VERSION 5.8 ;
BUSBITCHARS "[]" ;
DIVIDERCHAR "/" ;
UNITS
    DATABASE MICRONS 1000 ;
END UNITS

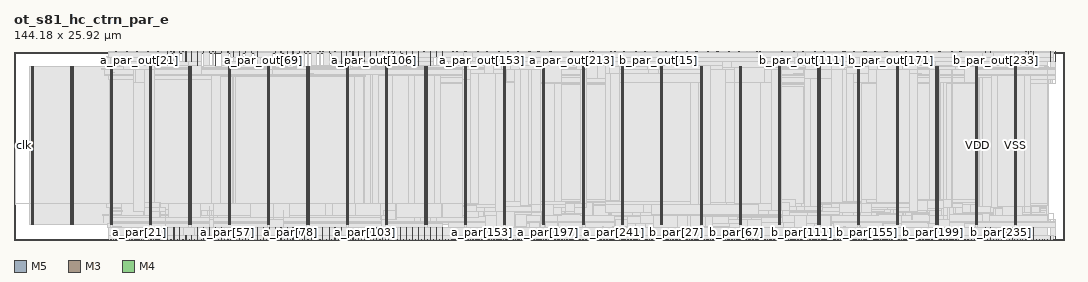
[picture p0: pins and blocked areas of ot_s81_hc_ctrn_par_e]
MACRO ot_s81_hc_ctrn_par_e
  FOREIGN ot_s81_hc_ctrn_par_e 0 0 ;
  CLASS BLOCK ;
  SIZE 144.18 BY 25.92 ;
  PIN a_par[0]
    DIRECTION INPUT ;
    USE SIGNAL ;
    PORT
      LAYER M5 ;
        RECT  13.008 0 13.032 0.084 ;
    END
  END a_par[0]
  PIN a_par[100]
    DIRECTION INPUT ;
    USE SIGNAL ;
    PORT
      LAYER M5 ;
        RECT  46.896 0 46.92 0.084 ;
    END
  END a_par[100]
  PIN a_par[101]
    DIRECTION INPUT ;
    USE SIGNAL ;
    PORT
      LAYER M3 ;
        RECT  47.304 0 47.322 0.038 ;
    END
    PORT
      LAYER M3 ;
        RECT  47.304 0.012 47.322 0.571 ;
    END
  END a_par[101]
  PIN a_par[102]
    DIRECTION INPUT ;
    USE SIGNAL ;
    PORT
      LAYER M5 ;
        RECT  47.76 0 47.784 0.084 ;
    END
  END a_par[102]
  PIN a_par[103]
    DIRECTION INPUT ;
    USE SIGNAL ;
    PORT
      LAYER M3 ;
        RECT  48.168 0 48.186 0.038 ;
    END
    PORT
      LAYER M3 ;
        RECT  48.168 0.012 48.186 0.091 ;
    END
  END a_par[103]
  PIN a_par[104]
    DIRECTION INPUT ;
    USE SIGNAL ;
    PORT
      LAYER M5 ;
        RECT  48.528 0 48.552 0.084 ;
    END
  END a_par[104]
  PIN a_par[105]
    DIRECTION INPUT ;
    USE SIGNAL ;
    PORT
      LAYER M3 ;
        RECT  48.96 0 48.978 0.038 ;
    END
    PORT
      LAYER M3 ;
        RECT  48.96 0.012 48.978 0.091 ;
    END
  END a_par[105]
  PIN a_par[106]
    DIRECTION INPUT ;
    USE SIGNAL ;
    PORT
      LAYER M5 ;
        RECT  49.392 0 49.416 0.084 ;
    END
  END a_par[106]
  PIN a_par[107]
    DIRECTION INPUT ;
    USE SIGNAL ;
    PORT
      LAYER M3 ;
        RECT  49.824 0 49.842 0.038 ;
    END
    PORT
      LAYER M3 ;
        RECT  49.824 0.012 49.842 1.723 ;
    END
  END a_par[107]
  PIN a_par[108]
    DIRECTION INPUT ;
    USE SIGNAL ;
    PORT
      LAYER M5 ;
        RECT  50.256 0 50.28 0.084 ;
    END
  END a_par[108]
  PIN a_par[109]
    DIRECTION INPUT ;
    USE SIGNAL ;
    PORT
      LAYER M3 ;
        RECT  50.58 0 50.598 0.038 ;
    END
    PORT
      LAYER M3 ;
        RECT  50.58 0.012 50.598 1.723 ;
    END
  END a_par[109]
  PIN a_par[10]
    DIRECTION INPUT ;
    USE SIGNAL ;
    PORT
      LAYER M5 ;
        RECT  15.024 0 15.048 0.084 ;
    END
  END a_par[10]
  PIN a_par[110]
    DIRECTION INPUT ;
    USE SIGNAL ;
    PORT
      LAYER M5 ;
        RECT  51.024 0 51.048 0.084 ;
    END
  END a_par[110]
  PIN a_par[111]
    DIRECTION INPUT ;
    USE SIGNAL ;
    PORT
      LAYER M3 ;
        RECT  51.444 0 51.462 0.038 ;
    END
    PORT
      LAYER M3 ;
        RECT  51.444 0.012 51.462 0.091 ;
    END
  END a_par[111]
  PIN a_par[112]
    DIRECTION INPUT ;
    USE SIGNAL ;
    PORT
      LAYER M5 ;
        RECT  51.888 0 51.912 0.084 ;
    END
  END a_par[112]
  PIN a_par[113]
    DIRECTION INPUT ;
    USE SIGNAL ;
    PORT
      LAYER M3 ;
        RECT  52.2 0 52.218 0.038 ;
    END
    PORT
      LAYER M3 ;
        RECT  52.2 0.012 52.218 0.091 ;
    END
  END a_par[113]
  PIN a_par[114]
    DIRECTION INPUT ;
    USE SIGNAL ;
    PORT
      LAYER M5 ;
        RECT  52.656 0 52.68 0.084 ;
    END
  END a_par[114]
  PIN a_par[115]
    DIRECTION INPUT ;
    USE SIGNAL ;
    PORT
      LAYER M3 ;
        RECT  53.064 0 53.082 0.038 ;
    END
    PORT
      LAYER M3 ;
        RECT  53.064 0.012 53.082 1.723 ;
    END
  END a_par[115]
  PIN a_par[116]
    DIRECTION INPUT ;
    USE SIGNAL ;
    PORT
      LAYER M5 ;
        RECT  53.52 0 53.544 0.084 ;
    END
  END a_par[116]
  PIN a_par[117]
    DIRECTION INPUT ;
    USE SIGNAL ;
    PORT
      LAYER M3 ;
        RECT  53.856 0 53.874 0.038 ;
    END
    PORT
      LAYER M3 ;
        RECT  53.856 0.012 53.874 1.723 ;
    END
  END a_par[117]
  PIN a_par[118]
    DIRECTION INPUT ;
    USE SIGNAL ;
    PORT
      LAYER M5 ;
        RECT  54.288 0 54.312 0.084 ;
    END
  END a_par[118]
  PIN a_par[119]
    DIRECTION INPUT ;
    USE SIGNAL ;
    PORT
      LAYER M3 ;
        RECT  54.72 0 54.738 0.038 ;
    END
    PORT
      LAYER M3 ;
        RECT  54.72 0.012 54.738 1.723 ;
    END
  END a_par[119]
  PIN a_par[11]
    DIRECTION INPUT ;
    USE SIGNAL ;
    PORT
      LAYER M3 ;
        RECT  15.264 0 15.282 0.038 ;
    END
  END a_par[11]
  PIN a_par[120]
    DIRECTION INPUT ;
    USE SIGNAL ;
    PORT
      LAYER M5 ;
        RECT  55.152 0 55.176 0.084 ;
    END
  END a_par[120]
  PIN a_par[121]
    DIRECTION INPUT ;
    USE SIGNAL ;
    PORT
      LAYER M3 ;
        RECT  55.476 0 55.494 0.038 ;
    END
    PORT
      LAYER M3 ;
        RECT  55.476 0.012 55.494 1.723 ;
    END
  END a_par[121]
  PIN a_par[122]
    DIRECTION INPUT ;
    USE SIGNAL ;
    PORT
      LAYER M5 ;
        RECT  55.92 0 55.944 0.084 ;
    END
  END a_par[122]
  PIN a_par[123]
    DIRECTION INPUT ;
    USE SIGNAL ;
    PORT
      LAYER M3 ;
        RECT  56.34 0 56.358 0.038 ;
    END
    PORT
      LAYER M3 ;
        RECT  56.34 0.012 56.358 1.723 ;
    END
  END a_par[123]
  PIN a_par[124]
    DIRECTION INPUT ;
    USE SIGNAL ;
    PORT
      LAYER M5 ;
        RECT  56.784 0 56.808 0.084 ;
    END
  END a_par[124]
  PIN a_par[125]
    DIRECTION INPUT ;
    USE SIGNAL ;
    PORT
      LAYER M3 ;
        RECT  57.204 0 57.222 0.038 ;
    END
    PORT
      LAYER M3 ;
        RECT  57.204 0.012 57.222 1.723 ;
    END
  END a_par[125]
  PIN a_par[126]
    DIRECTION INPUT ;
    USE SIGNAL ;
    PORT
      LAYER M5 ;
        RECT  57.552 0 57.576 0.084 ;
    END
  END a_par[126]
  PIN a_par[127]
    DIRECTION INPUT ;
    USE SIGNAL ;
    PORT
      LAYER M3 ;
        RECT  57.96 0 57.978 0.038 ;
    END
    PORT
      LAYER M3 ;
        RECT  57.96 0.012 57.978 1.723 ;
    END
  END a_par[127]
  PIN a_par[128]
    DIRECTION INPUT ;
    USE SIGNAL ;
    PORT
      LAYER M5 ;
        RECT  58.416 0 58.44 0.084 ;
    END
  END a_par[128]
  PIN a_par[129]
    DIRECTION INPUT ;
    USE SIGNAL ;
    PORT
      LAYER M3 ;
        RECT  58.824 0 58.842 0.038 ;
    END
    PORT
      LAYER M3 ;
        RECT  58.824 0.012 58.842 1.723 ;
    END
  END a_par[129]
  PIN a_par[12]
    DIRECTION INPUT ;
    USE SIGNAL ;
    PORT
      LAYER M5 ;
        RECT  15.504 0 15.528 0.084 ;
    END
  END a_par[12]
  PIN a_par[130]
    DIRECTION INPUT ;
    USE SIGNAL ;
    PORT
      LAYER M5 ;
        RECT  59.184 0 59.208 0.084 ;
    END
  END a_par[130]
  PIN a_par[131]
    DIRECTION INPUT ;
    USE SIGNAL ;
    PORT
      LAYER M3 ;
        RECT  59.616 0 59.634 0.038 ;
    END
  END a_par[131]
  PIN a_par[132]
    DIRECTION INPUT ;
    USE SIGNAL ;
    PORT
      LAYER M5 ;
        RECT  60.048 0 60.072 0.084 ;
    END
  END a_par[132]
  PIN a_par[133]
    DIRECTION INPUT ;
    USE SIGNAL ;
    PORT
      LAYER M3 ;
        RECT  60.264 0 60.282 0.038 ;
    END
  END a_par[133]
  PIN a_par[134]
    DIRECTION INPUT ;
    USE SIGNAL ;
    PORT
      LAYER M5 ;
        RECT  60.432 0 60.456 0.084 ;
    END
  END a_par[134]
  PIN a_par[135]
    DIRECTION INPUT ;
    USE SIGNAL ;
    PORT
      LAYER M3 ;
        RECT  60.66 0 60.678 0.038 ;
    END
  END a_par[135]
  PIN a_par[136]
    DIRECTION INPUT ;
    USE SIGNAL ;
    PORT
      LAYER M5 ;
        RECT  60.816 0 60.84 0.084 ;
    END
  END a_par[136]
  PIN a_par[137]
    DIRECTION INPUT ;
    USE SIGNAL ;
    PORT
      LAYER M3 ;
        RECT  61.056 0 61.074 0.038 ;
    END
  END a_par[137]
  PIN a_par[138]
    DIRECTION INPUT ;
    USE SIGNAL ;
    PORT
      LAYER M5 ;
        RECT  61.296 0 61.32 0.084 ;
    END
  END a_par[138]
  PIN a_par[139]
    DIRECTION INPUT ;
    USE SIGNAL ;
    PORT
      LAYER M3 ;
        RECT  61.416 0 61.434 0.038 ;
    END
  END a_par[139]
  PIN a_par[13]
    DIRECTION INPUT ;
    USE SIGNAL ;
    PORT
      LAYER M3 ;
        RECT  15.624 0 15.642 0.038 ;
    END
  END a_par[13]
  PIN a_par[140]
    DIRECTION INPUT ;
    USE SIGNAL ;
    PORT
      LAYER M5 ;
        RECT  61.68 0 61.704 0.084 ;
    END
  END a_par[140]
  PIN a_par[141]
    DIRECTION INPUT ;
    USE SIGNAL ;
    PORT
      LAYER M3 ;
        RECT  61.92 0 61.938 0.038 ;
    END
  END a_par[141]
  PIN a_par[142]
    DIRECTION INPUT ;
    USE SIGNAL ;
    PORT
      LAYER M5 ;
        RECT  62.064 0 62.088 0.084 ;
    END
  END a_par[142]
  PIN a_par[143]
    DIRECTION INPUT ;
    USE SIGNAL ;
    PORT
      LAYER M3 ;
        RECT  62.28 0 62.298 0.038 ;
    END
  END a_par[143]
  PIN a_par[144]
    DIRECTION INPUT ;
    USE SIGNAL ;
    PORT
      LAYER M5 ;
        RECT  62.448 0 62.472 0.084 ;
    END
  END a_par[144]
  PIN a_par[145]
    DIRECTION INPUT ;
    USE SIGNAL ;
    PORT
      LAYER M3 ;
        RECT  62.676 0 62.694 0.038 ;
    END
  END a_par[145]
  PIN a_par[146]
    DIRECTION INPUT ;
    USE SIGNAL ;
    PORT
      LAYER M5 ;
        RECT  62.928 0 62.952 0.084 ;
    END
  END a_par[146]
  PIN a_par[147]
    DIRECTION INPUT ;
    USE SIGNAL ;
    PORT
      LAYER M3 ;
        RECT  63.072 0 63.09 0.038 ;
    END
  END a_par[147]
  PIN a_par[148]
    DIRECTION INPUT ;
    USE SIGNAL ;
    PORT
      LAYER M5 ;
        RECT  63.312 0 63.336 0.084 ;
    END
  END a_par[148]
  PIN a_par[149]
    DIRECTION INPUT ;
    USE SIGNAL ;
    PORT
      LAYER M3 ;
        RECT  63.54 0 63.558 0.038 ;
    END
  END a_par[149]
  PIN a_par[14]
    DIRECTION INPUT ;
    USE SIGNAL ;
    PORT
      LAYER M5 ;
        RECT  15.888 0 15.912 0.084 ;
    END
  END a_par[14]
  PIN a_par[150]
    DIRECTION INPUT ;
    USE SIGNAL ;
    PORT
      LAYER M5 ;
        RECT  63.696 0 63.72 0.084 ;
    END
  END a_par[150]
  PIN a_par[151]
    DIRECTION INPUT ;
    USE SIGNAL ;
    PORT
      LAYER M3 ;
        RECT  63.936 0 63.954 0.038 ;
    END
  END a_par[151]
  PIN a_par[152]
    DIRECTION INPUT ;
    USE SIGNAL ;
    PORT
      LAYER M5 ;
        RECT  64.176 0 64.2 0.084 ;
    END
  END a_par[152]
  PIN a_par[153]
    DIRECTION INPUT ;
    USE SIGNAL ;
    PORT
      LAYER M3 ;
        RECT  64.296 0 64.314 0.038 ;
    END
  END a_par[153]
  PIN a_par[154]
    DIRECTION INPUT ;
    USE SIGNAL ;
    PORT
      LAYER M5 ;
        RECT  64.56 0 64.584 0.084 ;
    END
  END a_par[154]
  PIN a_par[155]
    DIRECTION INPUT ;
    USE SIGNAL ;
    PORT
      LAYER M3 ;
        RECT  64.692 0 64.71 0.038 ;
    END
  END a_par[155]
  PIN a_par[156]
    DIRECTION INPUT ;
    USE SIGNAL ;
    PORT
      LAYER M5 ;
        RECT  64.944 0 64.968 0.084 ;
    END
  END a_par[156]
  PIN a_par[157]
    DIRECTION INPUT ;
    USE SIGNAL ;
    PORT
      LAYER M3 ;
        RECT  65.16 0 65.178 0.038 ;
    END
  END a_par[157]
  PIN a_par[158]
    DIRECTION INPUT ;
    USE SIGNAL ;
    PORT
      LAYER M5 ;
        RECT  65.328 0 65.352 0.084 ;
    END
  END a_par[158]
  PIN a_par[159]
    DIRECTION INPUT ;
    USE SIGNAL ;
    PORT
      LAYER M3 ;
        RECT  65.556 0 65.574 0.038 ;
    END
  END a_par[159]
  PIN a_par[15]
    DIRECTION INPUT ;
    USE SIGNAL ;
    PORT
      LAYER M3 ;
        RECT  16.128 0 16.146 0.038 ;
    END
  END a_par[15]
  PIN a_par[160]
    DIRECTION INPUT ;
    USE SIGNAL ;
    PORT
      LAYER M5 ;
        RECT  65.808 0 65.832 0.084 ;
    END
  END a_par[160]
  PIN a_par[161]
    DIRECTION INPUT ;
    USE SIGNAL ;
    PORT
      LAYER M3 ;
        RECT  65.952 0 65.97 0.038 ;
    END
  END a_par[161]
  PIN a_par[162]
    DIRECTION INPUT ;
    USE SIGNAL ;
    PORT
      LAYER M5 ;
        RECT  66.192 0 66.216 0.084 ;
    END
  END a_par[162]
  PIN a_par[163]
    DIRECTION INPUT ;
    USE SIGNAL ;
    PORT
      LAYER M3 ;
        RECT  66.42 0 66.438 0.038 ;
    END
  END a_par[163]
  PIN a_par[164]
    DIRECTION INPUT ;
    USE SIGNAL ;
    PORT
      LAYER M5 ;
        RECT  66.576 0 66.6 0.084 ;
    END
  END a_par[164]
  PIN a_par[165]
    DIRECTION INPUT ;
    USE SIGNAL ;
    PORT
      LAYER M3 ;
        RECT  66.816 0 66.834 0.038 ;
    END
  END a_par[165]
  PIN a_par[166]
    DIRECTION INPUT ;
    USE SIGNAL ;
    PORT
      LAYER M5 ;
        RECT  66.96 0 66.984 0.084 ;
    END
  END a_par[166]
  PIN a_par[167]
    DIRECTION INPUT ;
    USE SIGNAL ;
    PORT
      LAYER M3 ;
        RECT  67.176 0 67.194 0.038 ;
    END
  END a_par[167]
  PIN a_par[168]
    DIRECTION INPUT ;
    USE SIGNAL ;
    PORT
      LAYER M5 ;
        RECT  67.44 0 67.464 0.084 ;
    END
  END a_par[168]
  PIN a_par[169]
    DIRECTION INPUT ;
    USE SIGNAL ;
    PORT
      LAYER M3 ;
        RECT  67.572 0 67.59 0.038 ;
    END
  END a_par[169]
  PIN a_par[16]
    DIRECTION INPUT ;
    USE SIGNAL ;
    PORT
      LAYER M5 ;
        RECT  16.272 0 16.296 0.084 ;
    END
  END a_par[16]
  PIN a_par[170]
    DIRECTION INPUT ;
    USE SIGNAL ;
    PORT
      LAYER M5 ;
        RECT  67.824 0 67.848 0.084 ;
    END
  END a_par[170]
  PIN a_par[171]
    DIRECTION INPUT ;
    USE SIGNAL ;
    PORT
      LAYER M3 ;
        RECT  68.04 0 68.058 0.038 ;
    END
  END a_par[171]
  PIN a_par[172]
    DIRECTION INPUT ;
    USE SIGNAL ;
    PORT
      LAYER M5 ;
        RECT  68.208 0 68.232 0.084 ;
    END
  END a_par[172]
  PIN a_par[173]
    DIRECTION INPUT ;
    USE SIGNAL ;
    PORT
      LAYER M3 ;
        RECT  68.436 0 68.454 0.038 ;
    END
  END a_par[173]
  PIN a_par[174]
    DIRECTION INPUT ;
    USE SIGNAL ;
    PORT
      LAYER M5 ;
        RECT  68.592 0 68.616 0.084 ;
    END
  END a_par[174]
  PIN a_par[175]
    DIRECTION INPUT ;
    USE SIGNAL ;
    PORT
      LAYER M3 ;
        RECT  68.832 0 68.85 0.038 ;
    END
  END a_par[175]
  PIN a_par[176]
    DIRECTION INPUT ;
    USE SIGNAL ;
    PORT
      LAYER M5 ;
        RECT  69.072 0 69.096 0.084 ;
    END
  END a_par[176]
  PIN a_par[177]
    DIRECTION INPUT ;
    USE SIGNAL ;
    PORT
      LAYER M3 ;
        RECT  69.192 0 69.21 0.038 ;
    END
  END a_par[177]
  PIN a_par[178]
    DIRECTION INPUT ;
    USE SIGNAL ;
    PORT
      LAYER M5 ;
        RECT  69.456 0 69.48 0.084 ;
    END
  END a_par[178]
  PIN a_par[179]
    DIRECTION INPUT ;
    USE SIGNAL ;
    PORT
      LAYER M3 ;
        RECT  69.696 0 69.714 0.038 ;
    END
  END a_par[179]
  PIN a_par[17]
    DIRECTION INPUT ;
    USE SIGNAL ;
    PORT
      LAYER M3 ;
        RECT  16.488 0 16.506 0.038 ;
    END
  END a_par[17]
  PIN a_par[180]
    DIRECTION INPUT ;
    USE SIGNAL ;
    PORT
      LAYER M5 ;
        RECT  69.84 0 69.864 0.084 ;
    END
  END a_par[180]
  PIN a_par[181]
    DIRECTION INPUT ;
    USE SIGNAL ;
    PORT
      LAYER M3 ;
        RECT  70.056 0 70.074 0.038 ;
    END
  END a_par[181]
  PIN a_par[182]
    DIRECTION INPUT ;
    USE SIGNAL ;
    PORT
      LAYER M5 ;
        RECT  70.32 0 70.344 0.084 ;
    END
  END a_par[182]
  PIN a_par[183]
    DIRECTION INPUT ;
    USE SIGNAL ;
    PORT
      LAYER M3 ;
        RECT  70.452 0 70.47 0.038 ;
    END
  END a_par[183]
  PIN a_par[184]
    DIRECTION INPUT ;
    USE SIGNAL ;
    PORT
      LAYER M5 ;
        RECT  70.704 0 70.728 0.084 ;
    END
  END a_par[184]
  PIN a_par[185]
    DIRECTION INPUT ;
    USE SIGNAL ;
    PORT
      LAYER M3 ;
        RECT  70.848 0 70.866 0.038 ;
    END
  END a_par[185]
  PIN a_par[186]
    DIRECTION INPUT ;
    USE SIGNAL ;
    PORT
      LAYER M5 ;
        RECT  71.088 0 71.112 0.084 ;
    END
  END a_par[186]
  PIN a_par[187]
    DIRECTION INPUT ;
    USE SIGNAL ;
    PORT
      LAYER M3 ;
        RECT  71.316 0 71.334 0.038 ;
    END
  END a_par[187]
  PIN a_par[188]
    DIRECTION INPUT ;
    USE SIGNAL ;
    PORT
      LAYER M5 ;
        RECT  71.472 0 71.496 0.084 ;
    END
  END a_par[188]
  PIN a_par[189]
    DIRECTION INPUT ;
    USE SIGNAL ;
    PORT
      LAYER M3 ;
        RECT  71.712 0 71.73 0.038 ;
    END
  END a_par[189]
  PIN a_par[18]
    DIRECTION INPUT ;
    USE SIGNAL ;
    PORT
      LAYER M5 ;
        RECT  16.656 0 16.68 0.084 ;
    END
  END a_par[18]
  PIN a_par[190]
    DIRECTION INPUT ;
    USE SIGNAL ;
    PORT
      LAYER M5 ;
        RECT  71.952 0 71.976 0.084 ;
    END
  END a_par[190]
  PIN a_par[191]
    DIRECTION INPUT ;
    USE SIGNAL ;
    PORT
      LAYER M3 ;
        RECT  72.072 0 72.09 0.038 ;
    END
  END a_par[191]
  PIN a_par[192]
    DIRECTION INPUT ;
    USE SIGNAL ;
    PORT
      LAYER M5 ;
        RECT  72.336 0 72.36 0.084 ;
    END
  END a_par[192]
  PIN a_par[193]
    DIRECTION INPUT ;
    USE SIGNAL ;
    PORT
      LAYER M3 ;
        RECT  72.468 0 72.486 0.038 ;
    END
  END a_par[193]
  PIN a_par[194]
    DIRECTION INPUT ;
    USE SIGNAL ;
    PORT
      LAYER M5 ;
        RECT  72.72 0 72.744 0.084 ;
    END
  END a_par[194]
  PIN a_par[195]
    DIRECTION INPUT ;
    USE SIGNAL ;
    PORT
      LAYER M3 ;
        RECT  72.936 0 72.954 0.038 ;
    END
  END a_par[195]
  PIN a_par[196]
    DIRECTION INPUT ;
    USE SIGNAL ;
    PORT
      LAYER M5 ;
        RECT  73.104 0 73.128 0.084 ;
    END
  END a_par[196]
  PIN a_par[197]
    DIRECTION INPUT ;
    USE SIGNAL ;
    PORT
      LAYER M3 ;
        RECT  73.332 0 73.35 0.038 ;
    END
  END a_par[197]
  PIN a_par[198]
    DIRECTION INPUT ;
    USE SIGNAL ;
    PORT
      LAYER M5 ;
        RECT  73.584 0 73.608 0.084 ;
    END
  END a_par[198]
  PIN a_par[199]
    DIRECTION INPUT ;
    USE SIGNAL ;
    PORT
      LAYER M3 ;
        RECT  73.728 0 73.746 0.038 ;
    END
  END a_par[199]
  PIN a_par[19]
    DIRECTION INPUT ;
    USE SIGNAL ;
    PORT
      LAYER M3 ;
        RECT  16.884 0 16.902 0.038 ;
    END
  END a_par[19]
  PIN a_par[1]
    DIRECTION INPUT ;
    USE SIGNAL ;
    PORT
      LAYER M3 ;
        RECT  13.248 0 13.266 0.038 ;
    END
  END a_par[1]
  PIN a_par[200]
    DIRECTION INPUT ;
    USE SIGNAL ;
    PORT
      LAYER M5 ;
        RECT  73.968 0 73.992 0.084 ;
    END
  END a_par[200]
  PIN a_par[201]
    DIRECTION INPUT ;
    USE SIGNAL ;
    PORT
      LAYER M3 ;
        RECT  74.196 0 74.214 0.038 ;
    END
  END a_par[201]
  PIN a_par[202]
    DIRECTION INPUT ;
    USE SIGNAL ;
    PORT
      LAYER M5 ;
        RECT  74.352 0 74.376 0.084 ;
    END
  END a_par[202]
  PIN a_par[203]
    DIRECTION INPUT ;
    USE SIGNAL ;
    PORT
      LAYER M3 ;
        RECT  74.592 0 74.61 0.038 ;
    END
  END a_par[203]
  PIN a_par[204]
    DIRECTION INPUT ;
    USE SIGNAL ;
    PORT
      LAYER M5 ;
        RECT  74.736 0 74.76 0.084 ;
    END
  END a_par[204]
  PIN a_par[205]
    DIRECTION INPUT ;
    USE SIGNAL ;
    PORT
      LAYER M3 ;
        RECT  74.952 0 74.97 0.038 ;
    END
  END a_par[205]
  PIN a_par[206]
    DIRECTION INPUT ;
    USE SIGNAL ;
    PORT
      LAYER M5 ;
        RECT  75.216 0 75.24 0.084 ;
    END
  END a_par[206]
  PIN a_par[207]
    DIRECTION INPUT ;
    USE SIGNAL ;
    PORT
      LAYER M3 ;
        RECT  75.348 0 75.366 0.038 ;
    END
  END a_par[207]
  PIN a_par[208]
    DIRECTION INPUT ;
    USE SIGNAL ;
    PORT
      LAYER M5 ;
        RECT  75.6 0 75.624 0.084 ;
    END
  END a_par[208]
  PIN a_par[209]
    DIRECTION INPUT ;
    USE SIGNAL ;
    PORT
      LAYER M3 ;
        RECT  75.816 0 75.834 0.038 ;
    END
  END a_par[209]
  PIN a_par[20]
    DIRECTION INPUT ;
    USE SIGNAL ;
    PORT
      LAYER M5 ;
        RECT  17.136 0 17.16 0.084 ;
    END
  END a_par[20]
  PIN a_par[210]
    DIRECTION INPUT ;
    USE SIGNAL ;
    PORT
      LAYER M5 ;
        RECT  75.984 0 76.008 0.084 ;
    END
  END a_par[210]
  PIN a_par[211]
    DIRECTION INPUT ;
    USE SIGNAL ;
    PORT
      LAYER M3 ;
        RECT  76.212 0 76.23 0.038 ;
    END
  END a_par[211]
  PIN a_par[212]
    DIRECTION INPUT ;
    USE SIGNAL ;
    PORT
      LAYER M5 ;
        RECT  76.464 0 76.488 0.084 ;
    END
  END a_par[212]
  PIN a_par[213]
    DIRECTION INPUT ;
    USE SIGNAL ;
    PORT
      LAYER M3 ;
        RECT  76.608 0 76.626 0.038 ;
    END
  END a_par[213]
  PIN a_par[214]
    DIRECTION INPUT ;
    USE SIGNAL ;
    PORT
      LAYER M5 ;
        RECT  76.848 0 76.872 0.084 ;
    END
  END a_par[214]
  PIN a_par[215]
    DIRECTION INPUT ;
    USE SIGNAL ;
    PORT
      LAYER M3 ;
        RECT  76.968 0 76.986 0.038 ;
    END
  END a_par[215]
  PIN a_par[216]
    DIRECTION INPUT ;
    USE SIGNAL ;
    PORT
      LAYER M5 ;
        RECT  77.232 0 77.256 0.084 ;
    END
  END a_par[216]
  PIN a_par[217]
    DIRECTION INPUT ;
    USE SIGNAL ;
    PORT
      LAYER M3 ;
        RECT  77.472 0 77.49 0.038 ;
    END
  END a_par[217]
  PIN a_par[218]
    DIRECTION INPUT ;
    USE SIGNAL ;
    PORT
      LAYER M5 ;
        RECT  77.616 0 77.64 0.084 ;
    END
  END a_par[218]
  PIN a_par[219]
    DIRECTION INPUT ;
    USE SIGNAL ;
    PORT
      LAYER M3 ;
        RECT  77.832 0 77.85 0.038 ;
    END
  END a_par[219]
  PIN a_par[21]
    DIRECTION INPUT ;
    USE SIGNAL ;
    PORT
      LAYER M3 ;
        RECT  17.28 0 17.298 0.038 ;
    END
  END a_par[21]
  PIN a_par[220]
    DIRECTION INPUT ;
    USE SIGNAL ;
    PORT
      LAYER M5 ;
        RECT  78.096 0 78.12 0.084 ;
    END
  END a_par[220]
  PIN a_par[221]
    DIRECTION INPUT ;
    USE SIGNAL ;
    PORT
      LAYER M3 ;
        RECT  78.228 0 78.246 0.038 ;
    END
  END a_par[221]
  PIN a_par[222]
    DIRECTION INPUT ;
    USE SIGNAL ;
    PORT
      LAYER M5 ;
        RECT  78.48 0 78.504 0.084 ;
    END
  END a_par[222]
  PIN a_par[223]
    DIRECTION INPUT ;
    USE SIGNAL ;
    PORT
      LAYER M3 ;
        RECT  78.624 0 78.642 0.038 ;
    END
  END a_par[223]
  PIN a_par[224]
    DIRECTION INPUT ;
    USE SIGNAL ;
    PORT
      LAYER M5 ;
        RECT  78.864 0 78.888 0.084 ;
    END
  END a_par[224]
  PIN a_par[225]
    DIRECTION INPUT ;
    USE SIGNAL ;
    PORT
      LAYER M3 ;
        RECT  79.092 0 79.11 0.038 ;
    END
  END a_par[225]
  PIN a_par[226]
    DIRECTION INPUT ;
    USE SIGNAL ;
    PORT
      LAYER M5 ;
        RECT  79.248 0 79.272 0.084 ;
    END
  END a_par[226]
  PIN a_par[227]
    DIRECTION INPUT ;
    USE SIGNAL ;
    PORT
      LAYER M3 ;
        RECT  79.488 0 79.506 0.038 ;
    END
  END a_par[227]
  PIN a_par[228]
    DIRECTION INPUT ;
    USE SIGNAL ;
    PORT
      LAYER M5 ;
        RECT  79.728 0 79.752 0.084 ;
    END
  END a_par[228]
  PIN a_par[229]
    DIRECTION INPUT ;
    USE SIGNAL ;
    PORT
      LAYER M3 ;
        RECT  79.848 0 79.866 0.038 ;
    END
  END a_par[229]
  PIN a_par[22]
    DIRECTION INPUT ;
    USE SIGNAL ;
    PORT
      LAYER M5 ;
        RECT  17.52 0 17.544 0.084 ;
    END
  END a_par[22]
  PIN a_par[230]
    DIRECTION INPUT ;
    USE SIGNAL ;
    PORT
      LAYER M5 ;
        RECT  80.112 0 80.136 0.084 ;
    END
  END a_par[230]
  PIN a_par[231]
    DIRECTION INPUT ;
    USE SIGNAL ;
    PORT
      LAYER M3 ;
        RECT  80.352 0 80.37 0.038 ;
    END
  END a_par[231]
  PIN a_par[232]
    DIRECTION INPUT ;
    USE SIGNAL ;
    PORT
      LAYER M5 ;
        RECT  80.496 0 80.52 0.084 ;
    END
  END a_par[232]
  PIN a_par[233]
    DIRECTION INPUT ;
    USE SIGNAL ;
    PORT
      LAYER M3 ;
        RECT  80.712 0 80.73 0.038 ;
    END
  END a_par[233]
  PIN a_par[234]
    DIRECTION INPUT ;
    USE SIGNAL ;
    PORT
      LAYER M5 ;
        RECT  80.88 0 80.904 0.084 ;
    END
  END a_par[234]
  PIN a_par[235]
    DIRECTION INPUT ;
    USE SIGNAL ;
    PORT
      LAYER M3 ;
        RECT  81.108 0 81.126 0.038 ;
    END
  END a_par[235]
  PIN a_par[236]
    DIRECTION INPUT ;
    USE SIGNAL ;
    PORT
      LAYER M5 ;
        RECT  81.36 0 81.384 0.084 ;
    END
  END a_par[236]
  PIN a_par[237]
    DIRECTION INPUT ;
    USE SIGNAL ;
    PORT
      LAYER M3 ;
        RECT  81.504 0 81.522 0.038 ;
    END
  END a_par[237]
  PIN a_par[238]
    DIRECTION INPUT ;
    USE SIGNAL ;
    PORT
      LAYER M5 ;
        RECT  81.744 0 81.768 0.084 ;
    END
  END a_par[238]
  PIN a_par[239]
    DIRECTION INPUT ;
    USE SIGNAL ;
    PORT
      LAYER M3 ;
        RECT  81.972 0 81.99 0.038 ;
    END
  END a_par[239]
  PIN a_par[23]
    DIRECTION INPUT ;
    USE SIGNAL ;
    PORT
      LAYER M3 ;
        RECT  17.748 0 17.766 0.038 ;
    END
  END a_par[23]
  PIN a_par[240]
    DIRECTION INPUT ;
    USE SIGNAL ;
    PORT
      LAYER M5 ;
        RECT  82.128 0 82.152 0.084 ;
    END
  END a_par[240]
  PIN a_par[241]
    DIRECTION INPUT ;
    USE SIGNAL ;
    PORT
      LAYER M3 ;
        RECT  82.368 0 82.386 0.038 ;
    END
  END a_par[241]
  PIN a_par[242]
    DIRECTION INPUT ;
    USE SIGNAL ;
    PORT
      LAYER M5 ;
        RECT  82.512 0 82.536 0.084 ;
    END
  END a_par[242]
  PIN a_par[243]
    DIRECTION INPUT ;
    USE SIGNAL ;
    PORT
      LAYER M3 ;
        RECT  82.728 0 82.746 0.038 ;
    END
  END a_par[243]
  PIN a_par[244]
    DIRECTION INPUT ;
    USE SIGNAL ;
    PORT
      LAYER M5 ;
        RECT  82.992 0 83.016 0.084 ;
    END
  END a_par[244]
  PIN a_par[245]
    DIRECTION INPUT ;
    USE SIGNAL ;
    PORT
      LAYER M3 ;
        RECT  83.124 0 83.142 0.038 ;
    END
  END a_par[245]
  PIN a_par[246]
    DIRECTION INPUT ;
    USE SIGNAL ;
    PORT
      LAYER M5 ;
        RECT  83.376 0 83.4 0.084 ;
    END
  END a_par[246]
  PIN a_par[247]
    DIRECTION INPUT ;
    USE SIGNAL ;
    PORT
      LAYER M3 ;
        RECT  83.592 0 83.61 0.038 ;
    END
  END a_par[247]
  PIN a_par[248]
    DIRECTION INPUT ;
    USE SIGNAL ;
    PORT
      LAYER M5 ;
        RECT  83.76 0 83.784 0.084 ;
    END
  END a_par[248]
  PIN a_par[249]
    DIRECTION INPUT ;
    USE SIGNAL ;
    PORT
      LAYER M3 ;
        RECT  83.988 0 84.006 0.038 ;
    END
  END a_par[249]
  PIN a_par[24]
    DIRECTION INPUT ;
    USE SIGNAL ;
    PORT
      LAYER M5 ;
        RECT  17.904 0 17.928 0.084 ;
    END
  END a_par[24]
  PIN a_par[250]
    DIRECTION INPUT ;
    USE SIGNAL ;
    PORT
      LAYER M5 ;
        RECT  84.24 0 84.264 0.084 ;
    END
  END a_par[250]
  PIN a_par[251]
    DIRECTION INPUT ;
    USE SIGNAL ;
    PORT
      LAYER M3 ;
        RECT  84.384 0 84.402 0.038 ;
    END
  END a_par[251]
  PIN a_par[252]
    DIRECTION INPUT ;
    USE SIGNAL ;
    PORT
      LAYER M5 ;
        RECT  84.624 0 84.648 0.084 ;
    END
  END a_par[252]
  PIN a_par[253]
    DIRECTION INPUT ;
    USE SIGNAL ;
    PORT
      LAYER M3 ;
        RECT  84.744 0 84.762 0.038 ;
    END
  END a_par[253]
  PIN a_par[254]
    DIRECTION INPUT ;
    USE SIGNAL ;
    PORT
      LAYER M5 ;
        RECT  85.008 0 85.032 0.084 ;
    END
  END a_par[254]
  PIN a_par[255]
    DIRECTION INPUT ;
    USE SIGNAL ;
    PORT
      LAYER M3 ;
        RECT  85.248 0 85.266 0.038 ;
    END
  END a_par[255]
  PIN a_par[25]
    DIRECTION INPUT ;
    USE SIGNAL ;
    PORT
      LAYER M3 ;
        RECT  18.144 0 18.162 0.038 ;
    END
  END a_par[25]
  PIN a_par[26]
    DIRECTION INPUT ;
    USE SIGNAL ;
    PORT
      LAYER M5 ;
        RECT  18.384 0 18.408 0.084 ;
    END
  END a_par[26]
  PIN a_par[27]
    DIRECTION INPUT ;
    USE SIGNAL ;
    PORT
      LAYER M3 ;
        RECT  18.504 0 18.522 0.038 ;
    END
  END a_par[27]
  PIN a_par[28]
    DIRECTION INPUT ;
    USE SIGNAL ;
    PORT
      LAYER M5 ;
        RECT  18.768 0 18.792 0.084 ;
    END
  END a_par[28]
  PIN a_par[29]
    DIRECTION INPUT ;
    USE SIGNAL ;
    PORT
      LAYER M3 ;
        RECT  18.9 0 18.918 0.038 ;
    END
  END a_par[29]
  PIN a_par[2]
    DIRECTION INPUT ;
    USE SIGNAL ;
    PORT
      LAYER M5 ;
        RECT  13.392 0 13.416 0.084 ;
    END
  END a_par[2]
  PIN a_par[30]
    DIRECTION INPUT ;
    USE SIGNAL ;
    PORT
      LAYER M5 ;
        RECT  19.152 0 19.176 0.084 ;
    END
  END a_par[30]
  PIN a_par[31]
    DIRECTION INPUT ;
    USE SIGNAL ;
    PORT
      LAYER M3 ;
        RECT  19.368 0 19.386 0.038 ;
    END
  END a_par[31]
  PIN a_par[32]
    DIRECTION INPUT ;
    USE SIGNAL ;
    PORT
      LAYER M5 ;
        RECT  19.536 0 19.56 0.084 ;
    END
  END a_par[32]
  PIN a_par[33]
    DIRECTION INPUT ;
    USE SIGNAL ;
    PORT
      LAYER M3 ;
        RECT  19.764 0 19.782 0.038 ;
    END
  END a_par[33]
  PIN a_par[34]
    DIRECTION INPUT ;
    USE SIGNAL ;
    PORT
      LAYER M5 ;
        RECT  20.016 0 20.04 0.084 ;
    END
  END a_par[34]
  PIN a_par[35]
    DIRECTION INPUT ;
    USE SIGNAL ;
    PORT
      LAYER M3 ;
        RECT  20.34 0 20.358 0.038 ;
    END
  END a_par[35]
  PIN a_par[36]
    DIRECTION INPUT ;
    USE SIGNAL ;
    PORT
      LAYER M5 ;
        RECT  20.688 0 20.712 0.084 ;
    END
  END a_par[36]
  PIN a_par[37]
    DIRECTION INPUT ;
    USE SIGNAL ;
    PORT
      LAYER M3 ;
        RECT  21.096 0 21.114 0.038 ;
    END
    PORT
      LAYER M3 ;
        RECT  21.096 0.012 21.114 1.723 ;
    END
  END a_par[37]
  PIN a_par[38]
    DIRECTION INPUT ;
    USE SIGNAL ;
    PORT
      LAYER M5 ;
        RECT  21.552 0 21.576 0.084 ;
    END
  END a_par[38]
  PIN a_par[39]
    DIRECTION INPUT ;
    USE SIGNAL ;
    PORT
      LAYER M3 ;
        RECT  21.96 0 21.978 0.038 ;
    END
    PORT
      LAYER M3 ;
        RECT  21.96 0.012 21.978 1.723 ;
    END
  END a_par[39]
  PIN a_par[3]
    DIRECTION INPUT ;
    USE SIGNAL ;
    PORT
      LAYER M3 ;
        RECT  13.608 0 13.626 0.038 ;
    END
  END a_par[3]
  PIN a_par[40]
    DIRECTION INPUT ;
    USE SIGNAL ;
    PORT
      LAYER M5 ;
        RECT  22.416 0 22.44 0.084 ;
    END
  END a_par[40]
  PIN a_par[41]
    DIRECTION INPUT ;
    USE SIGNAL ;
    PORT
      LAYER M3 ;
        RECT  22.752 0 22.77 0.038 ;
    END
    PORT
      LAYER M3 ;
        RECT  22.752 0.012 22.77 1.723 ;
    END
  END a_par[41]
  PIN a_par[42]
    DIRECTION INPUT ;
    USE SIGNAL ;
    PORT
      LAYER M5 ;
        RECT  23.184 0 23.208 0.084 ;
    END
  END a_par[42]
  PIN a_par[43]
    DIRECTION INPUT ;
    USE SIGNAL ;
    PORT
      LAYER M3 ;
        RECT  23.616 0 23.634 0.038 ;
    END
    PORT
      LAYER M3 ;
        RECT  23.616 0.012 23.634 0.571 ;
    END
  END a_par[43]
  PIN a_par[44]
    DIRECTION INPUT ;
    USE SIGNAL ;
    PORT
      LAYER M5 ;
        RECT  24.048 0 24.072 0.084 ;
    END
  END a_par[44]
  PIN a_par[45]
    DIRECTION INPUT ;
    USE SIGNAL ;
    PORT
      LAYER M3 ;
        RECT  24.372 0 24.39 0.038 ;
    END
    PORT
      LAYER M3 ;
        RECT  24.372 0.012 24.39 0.571 ;
    END
  END a_par[45]
  PIN a_par[46]
    DIRECTION INPUT ;
    USE SIGNAL ;
    PORT
      LAYER M5 ;
        RECT  24.816 0 24.84 0.084 ;
    END
  END a_par[46]
  PIN a_par[47]
    DIRECTION INPUT ;
    USE SIGNAL ;
    PORT
      LAYER M3 ;
        RECT  25.236 0 25.254 0.038 ;
    END
    PORT
      LAYER M3 ;
        RECT  25.236 0.012 25.254 1.723 ;
    END
  END a_par[47]
  PIN a_par[48]
    DIRECTION INPUT ;
    USE SIGNAL ;
    PORT
      LAYER M5 ;
        RECT  25.68 0 25.704 0.084 ;
    END
  END a_par[48]
  PIN a_par[49]
    DIRECTION INPUT ;
    USE SIGNAL ;
    PORT
      LAYER M3 ;
        RECT  25.992 0 26.01 0.038 ;
    END
    PORT
      LAYER M3 ;
        RECT  25.992 0.012 26.01 1.723 ;
    END
  END a_par[49]
  PIN a_par[4]
    DIRECTION INPUT ;
    USE SIGNAL ;
    PORT
      LAYER M5 ;
        RECT  13.872 0 13.896 0.084 ;
    END
  END a_par[4]
  PIN a_par[50]
    DIRECTION INPUT ;
    USE SIGNAL ;
    PORT
      LAYER M5 ;
        RECT  26.448 0 26.472 0.084 ;
    END
  END a_par[50]
  PIN a_par[51]
    DIRECTION INPUT ;
    USE SIGNAL ;
    PORT
      LAYER M3 ;
        RECT  26.856 0 26.874 0.038 ;
    END
    PORT
      LAYER M3 ;
        RECT  26.856 0.012 26.874 1.723 ;
    END
  END a_par[51]
  PIN a_par[52]
    DIRECTION INPUT ;
    USE SIGNAL ;
    PORT
      LAYER M5 ;
        RECT  27.312 0 27.336 0.084 ;
    END
  END a_par[52]
  PIN a_par[53]
    DIRECTION INPUT ;
    USE SIGNAL ;
    PORT
      LAYER M3 ;
        RECT  27.648 0 27.666 0.038 ;
    END
    PORT
      LAYER M3 ;
        RECT  27.648 0.012 27.666 1.723 ;
    END
  END a_par[53]
  PIN a_par[54]
    DIRECTION INPUT ;
    USE SIGNAL ;
    PORT
      LAYER M5 ;
        RECT  28.08 0 28.104 0.084 ;
    END
  END a_par[54]
  PIN a_par[55]
    DIRECTION INPUT ;
    USE SIGNAL ;
    PORT
      LAYER M3 ;
        RECT  28.512 0 28.53 0.038 ;
    END
    PORT
      LAYER M3 ;
        RECT  28.512 0.012 28.53 1.723 ;
    END
  END a_par[55]
  PIN a_par[56]
    DIRECTION INPUT ;
    USE SIGNAL ;
    PORT
      LAYER M5 ;
        RECT  28.944 0 28.968 0.084 ;
    END
  END a_par[56]
  PIN a_par[57]
    DIRECTION INPUT ;
    USE SIGNAL ;
    PORT
      LAYER M3 ;
        RECT  29.376 0 29.394 0.038 ;
    END
    PORT
      LAYER M3 ;
        RECT  29.376 0.012 29.394 0.091 ;
    END
  END a_par[57]
  PIN a_par[58]
    DIRECTION INPUT ;
    USE SIGNAL ;
    PORT
      LAYER M5 ;
        RECT  29.712 0 29.736 0.084 ;
    END
  END a_par[58]
  PIN a_par[59]
    DIRECTION INPUT ;
    USE SIGNAL ;
    PORT
      LAYER M3 ;
        RECT  30.132 0 30.15 0.038 ;
    END
    PORT
      LAYER M3 ;
        RECT  30.132 0.012 30.15 0.091 ;
    END
  END a_par[59]
  PIN a_par[5]
    DIRECTION INPUT ;
    USE SIGNAL ;
    PORT
      LAYER M3 ;
        RECT  14.004 0 14.022 0.038 ;
    END
  END a_par[5]
  PIN a_par[60]
    DIRECTION INPUT ;
    USE SIGNAL ;
    PORT
      LAYER M5 ;
        RECT  30.576 0 30.6 0.084 ;
    END
  END a_par[60]
  PIN a_par[61]
    DIRECTION INPUT ;
    USE SIGNAL ;
    PORT
      LAYER M3 ;
        RECT  30.996 0 31.014 0.038 ;
    END
    PORT
      LAYER M3 ;
        RECT  30.996 0.012 31.014 1.723 ;
    END
  END a_par[61]
  PIN a_par[62]
    DIRECTION INPUT ;
    USE SIGNAL ;
    PORT
      LAYER M5 ;
        RECT  31.344 0 31.368 0.084 ;
    END
  END a_par[62]
  PIN a_par[63]
    DIRECTION INPUT ;
    USE SIGNAL ;
    PORT
      LAYER M3 ;
        RECT  31.752 0 31.77 0.038 ;
    END
    PORT
      LAYER M3 ;
        RECT  31.752 0.012 31.77 1.723 ;
    END
  END a_par[63]
  PIN a_par[64]
    DIRECTION INPUT ;
    USE SIGNAL ;
    PORT
      LAYER M5 ;
        RECT  32.208 0 32.232 0.084 ;
    END
  END a_par[64]
  PIN a_par[65]
    DIRECTION INPUT ;
    USE SIGNAL ;
    PORT
      LAYER M3 ;
        RECT  32.616 0 32.634 0.038 ;
    END
    PORT
      LAYER M3 ;
        RECT  32.616 0.012 32.634 1.723 ;
    END
  END a_par[65]
  PIN a_par[66]
    DIRECTION INPUT ;
    USE SIGNAL ;
    PORT
      LAYER M5 ;
        RECT  32.976 0 33 0.084 ;
    END
  END a_par[66]
  PIN a_par[67]
    DIRECTION INPUT ;
    USE SIGNAL ;
    PORT
      LAYER M3 ;
        RECT  33.408 0 33.426 0.038 ;
    END
    PORT
      LAYER M3 ;
        RECT  33.408 0.012 33.426 1.723 ;
    END
  END a_par[67]
  PIN a_par[68]
    DIRECTION INPUT ;
    USE SIGNAL ;
    PORT
      LAYER M5 ;
        RECT  33.84 0 33.864 0.084 ;
    END
  END a_par[68]
  PIN a_par[69]
    DIRECTION INPUT ;
    USE SIGNAL ;
    PORT
      LAYER M3 ;
        RECT  34.272 0 34.29 0.038 ;
    END
    PORT
      LAYER M3 ;
        RECT  34.272 0.012 34.29 1.723 ;
    END
  END a_par[69]
  PIN a_par[6]
    DIRECTION INPUT ;
    USE SIGNAL ;
    PORT
      LAYER M5 ;
        RECT  14.256 0 14.28 0.084 ;
    END
  END a_par[6]
  PIN a_par[70]
    DIRECTION INPUT ;
    USE SIGNAL ;
    PORT
      LAYER M5 ;
        RECT  34.608 0 34.632 0.084 ;
    END
  END a_par[70]
  PIN a_par[71]
    DIRECTION INPUT ;
    USE SIGNAL ;
    PORT
      LAYER M3 ;
        RECT  35.028 0 35.046 0.038 ;
    END
    PORT
      LAYER M3 ;
        RECT  35.028 0.012 35.046 1.723 ;
    END
  END a_par[71]
  PIN a_par[72]
    DIRECTION INPUT ;
    USE SIGNAL ;
    PORT
      LAYER M5 ;
        RECT  35.472 0 35.496 0.084 ;
    END
  END a_par[72]
  PIN a_par[73]
    DIRECTION INPUT ;
    USE SIGNAL ;
    PORT
      LAYER M3 ;
        RECT  35.892 0 35.91 0.038 ;
    END
    PORT
      LAYER M3 ;
        RECT  35.892 0.012 35.91 1.723 ;
    END
  END a_par[73]
  PIN a_par[74]
    DIRECTION INPUT ;
    USE SIGNAL ;
    PORT
      LAYER M5 ;
        RECT  36.336 0 36.36 0.084 ;
    END
  END a_par[74]
  PIN a_par[75]
    DIRECTION INPUT ;
    USE SIGNAL ;
    PORT
      LAYER M3 ;
        RECT  36.648 0 36.666 0.038 ;
    END
    PORT
      LAYER M3 ;
        RECT  36.648 0.012 36.666 1.723 ;
    END
  END a_par[75]
  PIN a_par[76]
    DIRECTION INPUT ;
    USE SIGNAL ;
    PORT
      LAYER M5 ;
        RECT  37.104 0 37.128 0.084 ;
    END
  END a_par[76]
  PIN a_par[77]
    DIRECTION INPUT ;
    USE SIGNAL ;
    PORT
      LAYER M3 ;
        RECT  37.512 0 37.53 0.038 ;
    END
    PORT
      LAYER M3 ;
        RECT  37.512 0.012 37.53 1.723 ;
    END
  END a_par[77]
  PIN a_par[78]
    DIRECTION INPUT ;
    USE SIGNAL ;
    PORT
      LAYER M5 ;
        RECT  37.968 0 37.992 0.084 ;
    END
  END a_par[78]
  PIN a_par[79]
    DIRECTION INPUT ;
    USE SIGNAL ;
    PORT
      LAYER M3 ;
        RECT  38.304 0 38.322 0.038 ;
    END
    PORT
      LAYER M3 ;
        RECT  38.304 0.012 38.322 1.723 ;
    END
  END a_par[79]
  PIN a_par[7]
    DIRECTION INPUT ;
    USE SIGNAL ;
    PORT
      LAYER M3 ;
        RECT  14.4 0 14.418 0.038 ;
    END
  END a_par[7]
  PIN a_par[80]
    DIRECTION INPUT ;
    USE SIGNAL ;
    PORT
      LAYER M5 ;
        RECT  38.736 0 38.76 0.084 ;
    END
  END a_par[80]
  PIN a_par[81]
    DIRECTION INPUT ;
    USE SIGNAL ;
    PORT
      LAYER M3 ;
        RECT  39.168 0 39.186 0.038 ;
    END
    PORT
      LAYER M3 ;
        RECT  39.168 0.012 39.186 1.723 ;
    END
  END a_par[81]
  PIN a_par[82]
    DIRECTION INPUT ;
    USE SIGNAL ;
    PORT
      LAYER M5 ;
        RECT  39.6 0 39.624 0.084 ;
    END
  END a_par[82]
  PIN a_par[83]
    DIRECTION INPUT ;
    USE SIGNAL ;
    PORT
      LAYER M3 ;
        RECT  39.924 0 39.942 0.038 ;
    END
    PORT
      LAYER M3 ;
        RECT  39.924 0.012 39.942 1.723 ;
    END
  END a_par[83]
  PIN a_par[84]
    DIRECTION INPUT ;
    USE SIGNAL ;
    PORT
      LAYER M5 ;
        RECT  40.368 0 40.392 0.084 ;
    END
  END a_par[84]
  PIN a_par[85]
    DIRECTION INPUT ;
    USE SIGNAL ;
    PORT
      LAYER M3 ;
        RECT  40.788 0 40.806 0.038 ;
    END
    PORT
      LAYER M3 ;
        RECT  40.788 0.012 40.806 1.723 ;
    END
  END a_par[85]
  PIN a_par[86]
    DIRECTION INPUT ;
    USE SIGNAL ;
    PORT
      LAYER M5 ;
        RECT  41.232 0 41.256 0.084 ;
    END
  END a_par[86]
  PIN a_par[87]
    DIRECTION INPUT ;
    USE SIGNAL ;
    PORT
      LAYER M3 ;
        RECT  41.544 0 41.562 0.038 ;
    END
    PORT
      LAYER M3 ;
        RECT  41.544 0.012 41.562 1.723 ;
    END
  END a_par[87]
  PIN a_par[88]
    DIRECTION INPUT ;
    USE SIGNAL ;
    PORT
      LAYER M5 ;
        RECT  42 0 42.024 0.084 ;
    END
  END a_par[88]
  PIN a_par[89]
    DIRECTION INPUT ;
    USE SIGNAL ;
    PORT
      LAYER M3 ;
        RECT  42.408 0 42.426 0.038 ;
    END
    PORT
      LAYER M3 ;
        RECT  42.408 0.012 42.426 1.723 ;
    END
  END a_par[89]
  PIN a_par[8]
    DIRECTION INPUT ;
    USE SIGNAL ;
    PORT
      LAYER M5 ;
        RECT  14.64 0 14.664 0.084 ;
    END
  END a_par[8]
  PIN a_par[90]
    DIRECTION INPUT ;
    USE SIGNAL ;
    PORT
      LAYER M5 ;
        RECT  42.864 0 42.888 0.084 ;
    END
  END a_par[90]
  PIN a_par[91]
    DIRECTION INPUT ;
    USE SIGNAL ;
    PORT
      LAYER M3 ;
        RECT  43.272 0 43.29 0.038 ;
    END
    PORT
      LAYER M3 ;
        RECT  43.272 0.012 43.29 1.723 ;
    END
  END a_par[91]
  PIN a_par[92]
    DIRECTION INPUT ;
    USE SIGNAL ;
    PORT
      LAYER M5 ;
        RECT  43.632 0 43.656 0.084 ;
    END
  END a_par[92]
  PIN a_par[93]
    DIRECTION INPUT ;
    USE SIGNAL ;
    PORT
      LAYER M3 ;
        RECT  44.064 0 44.082 0.038 ;
    END
    PORT
      LAYER M3 ;
        RECT  44.064 0.012 44.082 1.723 ;
    END
  END a_par[93]
  PIN a_par[94]
    DIRECTION INPUT ;
    USE SIGNAL ;
    PORT
      LAYER M5 ;
        RECT  44.496 0 44.52 0.084 ;
    END
  END a_par[94]
  PIN a_par[95]
    DIRECTION INPUT ;
    USE SIGNAL ;
    PORT
      LAYER M3 ;
        RECT  44.928 0 44.946 0.038 ;
    END
    PORT
      LAYER M3 ;
        RECT  44.928 0.012 44.946 1.723 ;
    END
  END a_par[95]
  PIN a_par[96]
    DIRECTION INPUT ;
    USE SIGNAL ;
    PORT
      LAYER M5 ;
        RECT  45.264 0 45.288 0.084 ;
    END
  END a_par[96]
  PIN a_par[97]
    DIRECTION INPUT ;
    USE SIGNAL ;
    PORT
      LAYER M3 ;
        RECT  45.684 0 45.702 0.038 ;
    END
    PORT
      LAYER M3 ;
        RECT  45.684 0.012 45.702 0.031 ;
    END
    PORT
      LAYER M3 ;
        RECT  45.684 0.031 45.774 0.059 ;
    END
  END a_par[97]
  PIN a_par[98]
    DIRECTION INPUT ;
    USE SIGNAL ;
    PORT
      LAYER M5 ;
        RECT  46.128 0 46.152 0.084 ;
    END
  END a_par[98]
  PIN a_par[99]
    DIRECTION INPUT ;
    USE SIGNAL ;
    PORT
      LAYER M3 ;
        RECT  46.548 0 46.566 0.038 ;
    END
    PORT
      LAYER M3 ;
        RECT  46.548 0.012 46.566 0.571 ;
    END
  END a_par[99]
  PIN a_par[9]
    DIRECTION INPUT ;
    USE SIGNAL ;
    PORT
      LAYER M3 ;
        RECT  14.868 0 14.886 0.038 ;
    END
  END a_par[9]
  PIN a_par_out[0]
    DIRECTION OUTPUT ;
    USE SIGNAL ;
    PORT
      LAYER M5 ;
        RECT  13.008 25.836 13.032 25.92 ;
    END
  END a_par_out[0]
  PIN a_par_out[100]
    DIRECTION OUTPUT ;
    USE SIGNAL ;
    PORT
      LAYER M5 ;
        RECT  46.896 25.836 46.92 25.92 ;
    END
  END a_par_out[100]
  PIN a_par_out[101]
    DIRECTION OUTPUT ;
    USE SIGNAL ;
    PORT
      LAYER M3 ;
        RECT  47.304 25.882 47.322 25.92 ;
    END
    PORT
      LAYER M3 ;
        RECT  47.304 24.509 47.322 25.901 ;
    END
  END a_par_out[101]
  PIN a_par_out[102]
    DIRECTION OUTPUT ;
    USE SIGNAL ;
    PORT
      LAYER M5 ;
        RECT  47.76 25.836 47.784 25.92 ;
    END
  END a_par_out[102]
  PIN a_par_out[103]
    DIRECTION OUTPUT ;
    USE SIGNAL ;
    PORT
      LAYER M3 ;
        RECT  48.168 25.882 48.186 25.92 ;
    END
    PORT
      LAYER M3 ;
        RECT  48.168 24.509 48.186 25.901 ;
    END
  END a_par_out[103]
  PIN a_par_out[104]
    DIRECTION OUTPUT ;
    USE SIGNAL ;
    PORT
      LAYER M5 ;
        RECT  48.528 25.836 48.552 25.92 ;
    END
  END a_par_out[104]
  PIN a_par_out[105]
    DIRECTION OUTPUT ;
    USE SIGNAL ;
    PORT
      LAYER M3 ;
        RECT  48.96 25.882 48.978 25.92 ;
    END
    PORT
      LAYER M3 ;
        RECT  48.96 24.509 48.978 25.901 ;
    END
  END a_par_out[105]
  PIN a_par_out[106]
    DIRECTION OUTPUT ;
    USE SIGNAL ;
    PORT
      LAYER M5 ;
        RECT  49.392 25.836 49.416 25.92 ;
    END
  END a_par_out[106]
  PIN a_par_out[107]
    DIRECTION OUTPUT ;
    USE SIGNAL ;
    PORT
      LAYER M3 ;
        RECT  49.824 25.882 49.842 25.92 ;
    END
    PORT
      LAYER M3 ;
        RECT  49.824 24.509 49.842 25.901 ;
    END
  END a_par_out[107]
  PIN a_par_out[108]
    DIRECTION OUTPUT ;
    USE SIGNAL ;
    PORT
      LAYER M5 ;
        RECT  50.256 25.836 50.28 25.92 ;
    END
  END a_par_out[108]
  PIN a_par_out[109]
    DIRECTION OUTPUT ;
    USE SIGNAL ;
    PORT
      LAYER M3 ;
        RECT  50.58 25.882 50.598 25.92 ;
    END
    PORT
      LAYER M3 ;
        RECT  50.58 25.861 50.706 25.889 ;
    END
    PORT
      LAYER M3 ;
        RECT  50.58 25.889 50.598 25.901 ;
    END
  END a_par_out[109]
  PIN a_par_out[10]
    DIRECTION OUTPUT ;
    USE SIGNAL ;
    PORT
      LAYER M5 ;
        RECT  15.024 25.836 15.048 25.92 ;
    END
  END a_par_out[10]
  PIN a_par_out[110]
    DIRECTION OUTPUT ;
    USE SIGNAL ;
    PORT
      LAYER M5 ;
        RECT  51.024 25.836 51.048 25.92 ;
    END
  END a_par_out[110]
  PIN a_par_out[111]
    DIRECTION OUTPUT ;
    USE SIGNAL ;
    PORT
      LAYER M3 ;
        RECT  51.444 25.882 51.462 25.92 ;
    END
    PORT
      LAYER M3 ;
        RECT  51.444 24.461 51.462 25.901 ;
    END
  END a_par_out[111]
  PIN a_par_out[112]
    DIRECTION OUTPUT ;
    USE SIGNAL ;
    PORT
      LAYER M5 ;
        RECT  51.888 25.836 51.912 25.92 ;
    END
  END a_par_out[112]
  PIN a_par_out[113]
    DIRECTION OUTPUT ;
    USE SIGNAL ;
    PORT
      LAYER M3 ;
        RECT  52.2 25.882 52.218 25.92 ;
    END
    PORT
      LAYER M3 ;
        RECT  52.2 25.805 52.218 25.901 ;
    END
  END a_par_out[113]
  PIN a_par_out[114]
    DIRECTION OUTPUT ;
    USE SIGNAL ;
    PORT
      LAYER M5 ;
        RECT  52.656 25.836 52.68 25.92 ;
    END
  END a_par_out[114]
  PIN a_par_out[115]
    DIRECTION OUTPUT ;
    USE SIGNAL ;
    PORT
      LAYER M3 ;
        RECT  53.064 25.882 53.082 25.92 ;
    END
    PORT
      LAYER M3 ;
        RECT  53.064 25.805 53.082 25.901 ;
    END
  END a_par_out[115]
  PIN a_par_out[116]
    DIRECTION OUTPUT ;
    USE SIGNAL ;
    PORT
      LAYER M5 ;
        RECT  53.52 25.836 53.544 25.92 ;
    END
  END a_par_out[116]
  PIN a_par_out[117]
    DIRECTION OUTPUT ;
    USE SIGNAL ;
    PORT
      LAYER M3 ;
        RECT  53.856 25.882 53.874 25.92 ;
    END
    PORT
      LAYER M3 ;
        RECT  53.856 23.933 53.874 25.901 ;
    END
  END a_par_out[117]
  PIN a_par_out[118]
    DIRECTION OUTPUT ;
    USE SIGNAL ;
    PORT
      LAYER M5 ;
        RECT  54.288 25.836 54.312 25.92 ;
    END
  END a_par_out[118]
  PIN a_par_out[119]
    DIRECTION OUTPUT ;
    USE SIGNAL ;
    PORT
      LAYER M3 ;
        RECT  54.72 25.882 54.738 25.92 ;
    END
    PORT
      LAYER M3 ;
        RECT  54.72 24.509 54.738 25.901 ;
    END
  END a_par_out[119]
  PIN a_par_out[11]
    DIRECTION OUTPUT ;
    USE SIGNAL ;
    PORT
      LAYER M3 ;
        RECT  15.264 25.882 15.282 25.92 ;
    END
  END a_par_out[11]
  PIN a_par_out[120]
    DIRECTION OUTPUT ;
    USE SIGNAL ;
    PORT
      LAYER M5 ;
        RECT  55.152 25.836 55.176 25.92 ;
    END
  END a_par_out[120]
  PIN a_par_out[121]
    DIRECTION OUTPUT ;
    USE SIGNAL ;
    PORT
      LAYER M3 ;
        RECT  55.476 25.882 55.494 25.92 ;
    END
    PORT
      LAYER M3 ;
        RECT  55.476 23.933 55.494 25.901 ;
    END
  END a_par_out[121]
  PIN a_par_out[122]
    DIRECTION OUTPUT ;
    USE SIGNAL ;
    PORT
      LAYER M5 ;
        RECT  55.92 25.836 55.944 25.92 ;
    END
  END a_par_out[122]
  PIN a_par_out[123]
    DIRECTION OUTPUT ;
    USE SIGNAL ;
    PORT
      LAYER M3 ;
        RECT  56.34 25.882 56.358 25.92 ;
    END
    PORT
      LAYER M3 ;
        RECT  56.268 25.861 56.358 25.889 ;
    END
    PORT
      LAYER M3 ;
        RECT  56.34 25.889 56.358 25.901 ;
    END
  END a_par_out[123]
  PIN a_par_out[124]
    DIRECTION OUTPUT ;
    USE SIGNAL ;
    PORT
      LAYER M5 ;
        RECT  56.784 25.836 56.808 25.92 ;
    END
  END a_par_out[124]
  PIN a_par_out[125]
    DIRECTION OUTPUT ;
    USE SIGNAL ;
    PORT
      LAYER M3 ;
        RECT  57.204 25.882 57.222 25.92 ;
    END
    PORT
      LAYER M3 ;
        RECT  57.204 23.933 57.222 25.901 ;
    END
  END a_par_out[125]
  PIN a_par_out[126]
    DIRECTION OUTPUT ;
    USE SIGNAL ;
    PORT
      LAYER M5 ;
        RECT  57.552 25.836 57.576 25.92 ;
    END
  END a_par_out[126]
  PIN a_par_out[127]
    DIRECTION OUTPUT ;
    USE SIGNAL ;
    PORT
      LAYER M3 ;
        RECT  57.96 25.882 57.978 25.92 ;
    END
    PORT
      LAYER M3 ;
        RECT  57.96 25.133 57.978 25.901 ;
    END
  END a_par_out[127]
  PIN a_par_out[128]
    DIRECTION OUTPUT ;
    USE SIGNAL ;
    PORT
      LAYER M5 ;
        RECT  58.416 25.836 58.44 25.92 ;
    END
  END a_par_out[128]
  PIN a_par_out[129]
    DIRECTION OUTPUT ;
    USE SIGNAL ;
    PORT
      LAYER M3 ;
        RECT  58.824 25.882 58.842 25.92 ;
    END
    PORT
      LAYER M3 ;
        RECT  58.824 25.133 58.842 25.901 ;
    END
  END a_par_out[129]
  PIN a_par_out[12]
    DIRECTION OUTPUT ;
    USE SIGNAL ;
    PORT
      LAYER M5 ;
        RECT  15.504 25.836 15.528 25.92 ;
    END
  END a_par_out[12]
  PIN a_par_out[130]
    DIRECTION OUTPUT ;
    USE SIGNAL ;
    PORT
      LAYER M5 ;
        RECT  59.184 25.836 59.208 25.92 ;
    END
  END a_par_out[130]
  PIN a_par_out[131]
    DIRECTION OUTPUT ;
    USE SIGNAL ;
    PORT
      LAYER M3 ;
        RECT  59.616 25.882 59.634 25.92 ;
    END
  END a_par_out[131]
  PIN a_par_out[132]
    DIRECTION OUTPUT ;
    USE SIGNAL ;
    PORT
      LAYER M5 ;
        RECT  60.048 25.836 60.072 25.92 ;
    END
  END a_par_out[132]
  PIN a_par_out[133]
    DIRECTION OUTPUT ;
    USE SIGNAL ;
    PORT
      LAYER M3 ;
        RECT  60.264 25.882 60.282 25.92 ;
    END
  END a_par_out[133]
  PIN a_par_out[134]
    DIRECTION OUTPUT ;
    USE SIGNAL ;
    PORT
      LAYER M5 ;
        RECT  60.432 25.836 60.456 25.92 ;
    END
  END a_par_out[134]
  PIN a_par_out[135]
    DIRECTION OUTPUT ;
    USE SIGNAL ;
    PORT
      LAYER M3 ;
        RECT  60.66 25.882 60.678 25.92 ;
    END
  END a_par_out[135]
  PIN a_par_out[136]
    DIRECTION OUTPUT ;
    USE SIGNAL ;
    PORT
      LAYER M5 ;
        RECT  60.816 25.836 60.84 25.92 ;
    END
  END a_par_out[136]
  PIN a_par_out[137]
    DIRECTION OUTPUT ;
    USE SIGNAL ;
    PORT
      LAYER M3 ;
        RECT  61.056 25.882 61.074 25.92 ;
    END
  END a_par_out[137]
  PIN a_par_out[138]
    DIRECTION OUTPUT ;
    USE SIGNAL ;
    PORT
      LAYER M5 ;
        RECT  61.296 25.836 61.32 25.92 ;
    END
  END a_par_out[138]
  PIN a_par_out[139]
    DIRECTION OUTPUT ;
    USE SIGNAL ;
    PORT
      LAYER M3 ;
        RECT  61.416 25.882 61.434 25.92 ;
    END
  END a_par_out[139]
  PIN a_par_out[13]
    DIRECTION OUTPUT ;
    USE SIGNAL ;
    PORT
      LAYER M3 ;
        RECT  15.624 25.882 15.642 25.92 ;
    END
  END a_par_out[13]
  PIN a_par_out[140]
    DIRECTION OUTPUT ;
    USE SIGNAL ;
    PORT
      LAYER M5 ;
        RECT  61.68 25.836 61.704 25.92 ;
    END
  END a_par_out[140]
  PIN a_par_out[141]
    DIRECTION OUTPUT ;
    USE SIGNAL ;
    PORT
      LAYER M3 ;
        RECT  61.92 25.882 61.938 25.92 ;
    END
  END a_par_out[141]
  PIN a_par_out[142]
    DIRECTION OUTPUT ;
    USE SIGNAL ;
    PORT
      LAYER M5 ;
        RECT  62.064 25.836 62.088 25.92 ;
    END
  END a_par_out[142]
  PIN a_par_out[143]
    DIRECTION OUTPUT ;
    USE SIGNAL ;
    PORT
      LAYER M3 ;
        RECT  62.28 25.882 62.298 25.92 ;
    END
  END a_par_out[143]
  PIN a_par_out[144]
    DIRECTION OUTPUT ;
    USE SIGNAL ;
    PORT
      LAYER M5 ;
        RECT  62.448 25.836 62.472 25.92 ;
    END
  END a_par_out[144]
  PIN a_par_out[145]
    DIRECTION OUTPUT ;
    USE SIGNAL ;
    PORT
      LAYER M3 ;
        RECT  62.676 25.882 62.694 25.92 ;
    END
  END a_par_out[145]
  PIN a_par_out[146]
    DIRECTION OUTPUT ;
    USE SIGNAL ;
    PORT
      LAYER M5 ;
        RECT  62.928 25.836 62.952 25.92 ;
    END
  END a_par_out[146]
  PIN a_par_out[147]
    DIRECTION OUTPUT ;
    USE SIGNAL ;
    PORT
      LAYER M3 ;
        RECT  63.072 25.882 63.09 25.92 ;
    END
  END a_par_out[147]
  PIN a_par_out[148]
    DIRECTION OUTPUT ;
    USE SIGNAL ;
    PORT
      LAYER M5 ;
        RECT  63.312 25.836 63.336 25.92 ;
    END
  END a_par_out[148]
  PIN a_par_out[149]
    DIRECTION OUTPUT ;
    USE SIGNAL ;
    PORT
      LAYER M3 ;
        RECT  63.54 25.882 63.558 25.92 ;
    END
  END a_par_out[149]
  PIN a_par_out[14]
    DIRECTION OUTPUT ;
    USE SIGNAL ;
    PORT
      LAYER M5 ;
        RECT  15.888 25.836 15.912 25.92 ;
    END
  END a_par_out[14]
  PIN a_par_out[150]
    DIRECTION OUTPUT ;
    USE SIGNAL ;
    PORT
      LAYER M5 ;
        RECT  63.696 25.836 63.72 25.92 ;
    END
  END a_par_out[150]
  PIN a_par_out[151]
    DIRECTION OUTPUT ;
    USE SIGNAL ;
    PORT
      LAYER M3 ;
        RECT  63.936 25.882 63.954 25.92 ;
    END
  END a_par_out[151]
  PIN a_par_out[152]
    DIRECTION OUTPUT ;
    USE SIGNAL ;
    PORT
      LAYER M5 ;
        RECT  64.176 25.836 64.2 25.92 ;
    END
  END a_par_out[152]
  PIN a_par_out[153]
    DIRECTION OUTPUT ;
    USE SIGNAL ;
    PORT
      LAYER M3 ;
        RECT  64.296 25.882 64.314 25.92 ;
    END
  END a_par_out[153]
  PIN a_par_out[154]
    DIRECTION OUTPUT ;
    USE SIGNAL ;
    PORT
      LAYER M5 ;
        RECT  64.56 25.836 64.584 25.92 ;
    END
  END a_par_out[154]
  PIN a_par_out[155]
    DIRECTION OUTPUT ;
    USE SIGNAL ;
    PORT
      LAYER M3 ;
        RECT  64.692 25.882 64.71 25.92 ;
    END
  END a_par_out[155]
  PIN a_par_out[156]
    DIRECTION OUTPUT ;
    USE SIGNAL ;
    PORT
      LAYER M5 ;
        RECT  64.944 25.836 64.968 25.92 ;
    END
  END a_par_out[156]
  PIN a_par_out[157]
    DIRECTION OUTPUT ;
    USE SIGNAL ;
    PORT
      LAYER M3 ;
        RECT  65.16 25.882 65.178 25.92 ;
    END
  END a_par_out[157]
  PIN a_par_out[158]
    DIRECTION OUTPUT ;
    USE SIGNAL ;
    PORT
      LAYER M5 ;
        RECT  65.328 25.836 65.352 25.92 ;
    END
  END a_par_out[158]
  PIN a_par_out[159]
    DIRECTION OUTPUT ;
    USE SIGNAL ;
    PORT
      LAYER M3 ;
        RECT  65.556 25.882 65.574 25.92 ;
    END
  END a_par_out[159]
  PIN a_par_out[15]
    DIRECTION OUTPUT ;
    USE SIGNAL ;
    PORT
      LAYER M3 ;
        RECT  16.128 25.882 16.146 25.92 ;
    END
  END a_par_out[15]
  PIN a_par_out[160]
    DIRECTION OUTPUT ;
    USE SIGNAL ;
    PORT
      LAYER M5 ;
        RECT  65.808 25.836 65.832 25.92 ;
    END
  END a_par_out[160]
  PIN a_par_out[161]
    DIRECTION OUTPUT ;
    USE SIGNAL ;
    PORT
      LAYER M3 ;
        RECT  65.952 25.882 65.97 25.92 ;
    END
  END a_par_out[161]
  PIN a_par_out[162]
    DIRECTION OUTPUT ;
    USE SIGNAL ;
    PORT
      LAYER M5 ;
        RECT  66.192 25.836 66.216 25.92 ;
    END
  END a_par_out[162]
  PIN a_par_out[163]
    DIRECTION OUTPUT ;
    USE SIGNAL ;
    PORT
      LAYER M3 ;
        RECT  66.42 25.882 66.438 25.92 ;
    END
  END a_par_out[163]
  PIN a_par_out[164]
    DIRECTION OUTPUT ;
    USE SIGNAL ;
    PORT
      LAYER M5 ;
        RECT  66.576 25.836 66.6 25.92 ;
    END
  END a_par_out[164]
  PIN a_par_out[165]
    DIRECTION OUTPUT ;
    USE SIGNAL ;
    PORT
      LAYER M3 ;
        RECT  66.816 25.882 66.834 25.92 ;
    END
  END a_par_out[165]
  PIN a_par_out[166]
    DIRECTION OUTPUT ;
    USE SIGNAL ;
    PORT
      LAYER M5 ;
        RECT  66.96 25.836 66.984 25.92 ;
    END
  END a_par_out[166]
  PIN a_par_out[167]
    DIRECTION OUTPUT ;
    USE SIGNAL ;
    PORT
      LAYER M3 ;
        RECT  67.176 25.882 67.194 25.92 ;
    END
  END a_par_out[167]
  PIN a_par_out[168]
    DIRECTION OUTPUT ;
    USE SIGNAL ;
    PORT
      LAYER M5 ;
        RECT  67.44 25.836 67.464 25.92 ;
    END
  END a_par_out[168]
  PIN a_par_out[169]
    DIRECTION OUTPUT ;
    USE SIGNAL ;
    PORT
      LAYER M3 ;
        RECT  67.572 25.882 67.59 25.92 ;
    END
  END a_par_out[169]
  PIN a_par_out[16]
    DIRECTION OUTPUT ;
    USE SIGNAL ;
    PORT
      LAYER M5 ;
        RECT  16.272 25.836 16.296 25.92 ;
    END
  END a_par_out[16]
  PIN a_par_out[170]
    DIRECTION OUTPUT ;
    USE SIGNAL ;
    PORT
      LAYER M5 ;
        RECT  67.824 25.836 67.848 25.92 ;
    END
  END a_par_out[170]
  PIN a_par_out[171]
    DIRECTION OUTPUT ;
    USE SIGNAL ;
    PORT
      LAYER M3 ;
        RECT  68.04 25.882 68.058 25.92 ;
    END
  END a_par_out[171]
  PIN a_par_out[172]
    DIRECTION OUTPUT ;
    USE SIGNAL ;
    PORT
      LAYER M5 ;
        RECT  68.208 25.836 68.232 25.92 ;
    END
  END a_par_out[172]
  PIN a_par_out[173]
    DIRECTION OUTPUT ;
    USE SIGNAL ;
    PORT
      LAYER M3 ;
        RECT  68.436 25.882 68.454 25.92 ;
    END
  END a_par_out[173]
  PIN a_par_out[174]
    DIRECTION OUTPUT ;
    USE SIGNAL ;
    PORT
      LAYER M5 ;
        RECT  68.592 25.836 68.616 25.92 ;
    END
  END a_par_out[174]
  PIN a_par_out[175]
    DIRECTION OUTPUT ;
    USE SIGNAL ;
    PORT
      LAYER M3 ;
        RECT  68.832 25.882 68.85 25.92 ;
    END
  END a_par_out[175]
  PIN a_par_out[176]
    DIRECTION OUTPUT ;
    USE SIGNAL ;
    PORT
      LAYER M5 ;
        RECT  69.072 25.836 69.096 25.92 ;
    END
  END a_par_out[176]
  PIN a_par_out[177]
    DIRECTION OUTPUT ;
    USE SIGNAL ;
    PORT
      LAYER M3 ;
        RECT  69.192 25.882 69.21 25.92 ;
    END
  END a_par_out[177]
  PIN a_par_out[178]
    DIRECTION OUTPUT ;
    USE SIGNAL ;
    PORT
      LAYER M5 ;
        RECT  69.456 25.836 69.48 25.92 ;
    END
  END a_par_out[178]
  PIN a_par_out[179]
    DIRECTION OUTPUT ;
    USE SIGNAL ;
    PORT
      LAYER M3 ;
        RECT  69.696 25.882 69.714 25.92 ;
    END
  END a_par_out[179]
  PIN a_par_out[17]
    DIRECTION OUTPUT ;
    USE SIGNAL ;
    PORT
      LAYER M3 ;
        RECT  16.488 25.882 16.506 25.92 ;
    END
  END a_par_out[17]
  PIN a_par_out[180]
    DIRECTION OUTPUT ;
    USE SIGNAL ;
    PORT
      LAYER M5 ;
        RECT  69.84 25.836 69.864 25.92 ;
    END
  END a_par_out[180]
  PIN a_par_out[181]
    DIRECTION OUTPUT ;
    USE SIGNAL ;
    PORT
      LAYER M3 ;
        RECT  70.056 25.882 70.074 25.92 ;
    END
  END a_par_out[181]
  PIN a_par_out[182]
    DIRECTION OUTPUT ;
    USE SIGNAL ;
    PORT
      LAYER M5 ;
        RECT  70.32 25.836 70.344 25.92 ;
    END
  END a_par_out[182]
  PIN a_par_out[183]
    DIRECTION OUTPUT ;
    USE SIGNAL ;
    PORT
      LAYER M3 ;
        RECT  70.452 25.882 70.47 25.92 ;
    END
  END a_par_out[183]
  PIN a_par_out[184]
    DIRECTION OUTPUT ;
    USE SIGNAL ;
    PORT
      LAYER M5 ;
        RECT  70.704 25.836 70.728 25.92 ;
    END
  END a_par_out[184]
  PIN a_par_out[185]
    DIRECTION OUTPUT ;
    USE SIGNAL ;
    PORT
      LAYER M3 ;
        RECT  70.848 25.882 70.866 25.92 ;
    END
  END a_par_out[185]
  PIN a_par_out[186]
    DIRECTION OUTPUT ;
    USE SIGNAL ;
    PORT
      LAYER M5 ;
        RECT  71.088 25.836 71.112 25.92 ;
    END
  END a_par_out[186]
  PIN a_par_out[187]
    DIRECTION OUTPUT ;
    USE SIGNAL ;
    PORT
      LAYER M3 ;
        RECT  71.316 25.882 71.334 25.92 ;
    END
  END a_par_out[187]
  PIN a_par_out[188]
    DIRECTION OUTPUT ;
    USE SIGNAL ;
    PORT
      LAYER M5 ;
        RECT  71.472 25.836 71.496 25.92 ;
    END
  END a_par_out[188]
  PIN a_par_out[189]
    DIRECTION OUTPUT ;
    USE SIGNAL ;
    PORT
      LAYER M3 ;
        RECT  71.712 25.882 71.73 25.92 ;
    END
  END a_par_out[189]
  PIN a_par_out[18]
    DIRECTION OUTPUT ;
    USE SIGNAL ;
    PORT
      LAYER M5 ;
        RECT  16.656 25.836 16.68 25.92 ;
    END
  END a_par_out[18]
  PIN a_par_out[190]
    DIRECTION OUTPUT ;
    USE SIGNAL ;
    PORT
      LAYER M5 ;
        RECT  71.952 25.836 71.976 25.92 ;
    END
  END a_par_out[190]
  PIN a_par_out[191]
    DIRECTION OUTPUT ;
    USE SIGNAL ;
    PORT
      LAYER M3 ;
        RECT  72.072 25.882 72.09 25.92 ;
    END
  END a_par_out[191]
  PIN a_par_out[192]
    DIRECTION OUTPUT ;
    USE SIGNAL ;
    PORT
      LAYER M5 ;
        RECT  72.336 25.836 72.36 25.92 ;
    END
  END a_par_out[192]
  PIN a_par_out[193]
    DIRECTION OUTPUT ;
    USE SIGNAL ;
    PORT
      LAYER M3 ;
        RECT  72.468 25.882 72.486 25.92 ;
    END
  END a_par_out[193]
  PIN a_par_out[194]
    DIRECTION OUTPUT ;
    USE SIGNAL ;
    PORT
      LAYER M5 ;
        RECT  72.72 25.836 72.744 25.92 ;
    END
  END a_par_out[194]
  PIN a_par_out[195]
    DIRECTION OUTPUT ;
    USE SIGNAL ;
    PORT
      LAYER M3 ;
        RECT  72.936 25.882 72.954 25.92 ;
    END
  END a_par_out[195]
  PIN a_par_out[196]
    DIRECTION OUTPUT ;
    USE SIGNAL ;
    PORT
      LAYER M5 ;
        RECT  73.104 25.836 73.128 25.92 ;
    END
  END a_par_out[196]
  PIN a_par_out[197]
    DIRECTION OUTPUT ;
    USE SIGNAL ;
    PORT
      LAYER M3 ;
        RECT  73.332 25.882 73.35 25.92 ;
    END
  END a_par_out[197]
  PIN a_par_out[198]
    DIRECTION OUTPUT ;
    USE SIGNAL ;
    PORT
      LAYER M5 ;
        RECT  73.584 25.836 73.608 25.92 ;
    END
  END a_par_out[198]
  PIN a_par_out[199]
    DIRECTION OUTPUT ;
    USE SIGNAL ;
    PORT
      LAYER M3 ;
        RECT  73.728 25.882 73.746 25.92 ;
    END
  END a_par_out[199]
  PIN a_par_out[19]
    DIRECTION OUTPUT ;
    USE SIGNAL ;
    PORT
      LAYER M3 ;
        RECT  16.884 25.882 16.902 25.92 ;
    END
  END a_par_out[19]
  PIN a_par_out[1]
    DIRECTION OUTPUT ;
    USE SIGNAL ;
    PORT
      LAYER M3 ;
        RECT  13.248 25.882 13.266 25.92 ;
    END
  END a_par_out[1]
  PIN a_par_out[200]
    DIRECTION OUTPUT ;
    USE SIGNAL ;
    PORT
      LAYER M5 ;
        RECT  73.968 25.836 73.992 25.92 ;
    END
  END a_par_out[200]
  PIN a_par_out[201]
    DIRECTION OUTPUT ;
    USE SIGNAL ;
    PORT
      LAYER M3 ;
        RECT  74.196 25.882 74.214 25.92 ;
    END
  END a_par_out[201]
  PIN a_par_out[202]
    DIRECTION OUTPUT ;
    USE SIGNAL ;
    PORT
      LAYER M5 ;
        RECT  74.352 25.836 74.376 25.92 ;
    END
  END a_par_out[202]
  PIN a_par_out[203]
    DIRECTION OUTPUT ;
    USE SIGNAL ;
    PORT
      LAYER M3 ;
        RECT  74.592 25.882 74.61 25.92 ;
    END
  END a_par_out[203]
  PIN a_par_out[204]
    DIRECTION OUTPUT ;
    USE SIGNAL ;
    PORT
      LAYER M5 ;
        RECT  74.736 25.836 74.76 25.92 ;
    END
  END a_par_out[204]
  PIN a_par_out[205]
    DIRECTION OUTPUT ;
    USE SIGNAL ;
    PORT
      LAYER M3 ;
        RECT  74.952 25.882 74.97 25.92 ;
    END
  END a_par_out[205]
  PIN a_par_out[206]
    DIRECTION OUTPUT ;
    USE SIGNAL ;
    PORT
      LAYER M5 ;
        RECT  75.216 25.836 75.24 25.92 ;
    END
  END a_par_out[206]
  PIN a_par_out[207]
    DIRECTION OUTPUT ;
    USE SIGNAL ;
    PORT
      LAYER M3 ;
        RECT  75.348 25.882 75.366 25.92 ;
    END
  END a_par_out[207]
  PIN a_par_out[208]
    DIRECTION OUTPUT ;
    USE SIGNAL ;
    PORT
      LAYER M5 ;
        RECT  75.6 25.836 75.624 25.92 ;
    END
  END a_par_out[208]
  PIN a_par_out[209]
    DIRECTION OUTPUT ;
    USE SIGNAL ;
    PORT
      LAYER M3 ;
        RECT  75.816 25.882 75.834 25.92 ;
    END
  END a_par_out[209]
  PIN a_par_out[20]
    DIRECTION OUTPUT ;
    USE SIGNAL ;
    PORT
      LAYER M5 ;
        RECT  17.136 25.836 17.16 25.92 ;
    END
  END a_par_out[20]
  PIN a_par_out[210]
    DIRECTION OUTPUT ;
    USE SIGNAL ;
    PORT
      LAYER M5 ;
        RECT  75.984 25.836 76.008 25.92 ;
    END
  END a_par_out[210]
  PIN a_par_out[211]
    DIRECTION OUTPUT ;
    USE SIGNAL ;
    PORT
      LAYER M3 ;
        RECT  76.212 25.882 76.23 25.92 ;
    END
  END a_par_out[211]
  PIN a_par_out[212]
    DIRECTION OUTPUT ;
    USE SIGNAL ;
    PORT
      LAYER M5 ;
        RECT  76.464 25.836 76.488 25.92 ;
    END
  END a_par_out[212]
  PIN a_par_out[213]
    DIRECTION OUTPUT ;
    USE SIGNAL ;
    PORT
      LAYER M3 ;
        RECT  76.608 25.882 76.626 25.92 ;
    END
  END a_par_out[213]
  PIN a_par_out[214]
    DIRECTION OUTPUT ;
    USE SIGNAL ;
    PORT
      LAYER M5 ;
        RECT  76.848 25.836 76.872 25.92 ;
    END
  END a_par_out[214]
  PIN a_par_out[215]
    DIRECTION OUTPUT ;
    USE SIGNAL ;
    PORT
      LAYER M3 ;
        RECT  76.968 25.882 76.986 25.92 ;
    END
  END a_par_out[215]
  PIN a_par_out[216]
    DIRECTION OUTPUT ;
    USE SIGNAL ;
    PORT
      LAYER M5 ;
        RECT  77.232 25.836 77.256 25.92 ;
    END
  END a_par_out[216]
  PIN a_par_out[217]
    DIRECTION OUTPUT ;
    USE SIGNAL ;
    PORT
      LAYER M3 ;
        RECT  77.472 25.882 77.49 25.92 ;
    END
  END a_par_out[217]
  PIN a_par_out[218]
    DIRECTION OUTPUT ;
    USE SIGNAL ;
    PORT
      LAYER M5 ;
        RECT  77.616 25.836 77.64 25.92 ;
    END
  END a_par_out[218]
  PIN a_par_out[219]
    DIRECTION OUTPUT ;
    USE SIGNAL ;
    PORT
      LAYER M3 ;
        RECT  77.832 25.882 77.85 25.92 ;
    END
  END a_par_out[219]
  PIN a_par_out[21]
    DIRECTION OUTPUT ;
    USE SIGNAL ;
    PORT
      LAYER M3 ;
        RECT  17.28 25.882 17.298 25.92 ;
    END
  END a_par_out[21]
  PIN a_par_out[220]
    DIRECTION OUTPUT ;
    USE SIGNAL ;
    PORT
      LAYER M5 ;
        RECT  78.096 25.836 78.12 25.92 ;
    END
  END a_par_out[220]
  PIN a_par_out[221]
    DIRECTION OUTPUT ;
    USE SIGNAL ;
    PORT
      LAYER M3 ;
        RECT  78.228 25.882 78.246 25.92 ;
    END
  END a_par_out[221]
  PIN a_par_out[222]
    DIRECTION OUTPUT ;
    USE SIGNAL ;
    PORT
      LAYER M5 ;
        RECT  78.48 25.836 78.504 25.92 ;
    END
  END a_par_out[222]
  PIN a_par_out[223]
    DIRECTION OUTPUT ;
    USE SIGNAL ;
    PORT
      LAYER M3 ;
        RECT  78.624 25.882 78.642 25.92 ;
    END
  END a_par_out[223]
  PIN a_par_out[224]
    DIRECTION OUTPUT ;
    USE SIGNAL ;
    PORT
      LAYER M5 ;
        RECT  78.864 25.836 78.888 25.92 ;
    END
  END a_par_out[224]
  PIN a_par_out[225]
    DIRECTION OUTPUT ;
    USE SIGNAL ;
    PORT
      LAYER M3 ;
        RECT  79.092 25.882 79.11 25.92 ;
    END
  END a_par_out[225]
  PIN a_par_out[226]
    DIRECTION OUTPUT ;
    USE SIGNAL ;
    PORT
      LAYER M5 ;
        RECT  79.248 25.836 79.272 25.92 ;
    END
  END a_par_out[226]
  PIN a_par_out[227]
    DIRECTION OUTPUT ;
    USE SIGNAL ;
    PORT
      LAYER M3 ;
        RECT  79.488 25.882 79.506 25.92 ;
    END
  END a_par_out[227]
  PIN a_par_out[228]
    DIRECTION OUTPUT ;
    USE SIGNAL ;
    PORT
      LAYER M5 ;
        RECT  79.728 25.836 79.752 25.92 ;
    END
  END a_par_out[228]
  PIN a_par_out[229]
    DIRECTION OUTPUT ;
    USE SIGNAL ;
    PORT
      LAYER M3 ;
        RECT  79.848 25.882 79.866 25.92 ;
    END
  END a_par_out[229]
  PIN a_par_out[22]
    DIRECTION OUTPUT ;
    USE SIGNAL ;
    PORT
      LAYER M5 ;
        RECT  17.52 25.836 17.544 25.92 ;
    END
  END a_par_out[22]
  PIN a_par_out[230]
    DIRECTION OUTPUT ;
    USE SIGNAL ;
    PORT
      LAYER M5 ;
        RECT  80.112 25.836 80.136 25.92 ;
    END
  END a_par_out[230]
  PIN a_par_out[231]
    DIRECTION OUTPUT ;
    USE SIGNAL ;
    PORT
      LAYER M3 ;
        RECT  80.352 25.882 80.37 25.92 ;
    END
  END a_par_out[231]
  PIN a_par_out[232]
    DIRECTION OUTPUT ;
    USE SIGNAL ;
    PORT
      LAYER M5 ;
        RECT  80.496 25.836 80.52 25.92 ;
    END
  END a_par_out[232]
  PIN a_par_out[233]
    DIRECTION OUTPUT ;
    USE SIGNAL ;
    PORT
      LAYER M3 ;
        RECT  80.712 25.882 80.73 25.92 ;
    END
  END a_par_out[233]
  PIN a_par_out[234]
    DIRECTION OUTPUT ;
    USE SIGNAL ;
    PORT
      LAYER M5 ;
        RECT  80.88 25.836 80.904 25.92 ;
    END
  END a_par_out[234]
  PIN a_par_out[235]
    DIRECTION OUTPUT ;
    USE SIGNAL ;
    PORT
      LAYER M3 ;
        RECT  81.108 25.882 81.126 25.92 ;
    END
  END a_par_out[235]
  PIN a_par_out[236]
    DIRECTION OUTPUT ;
    USE SIGNAL ;
    PORT
      LAYER M5 ;
        RECT  81.36 25.836 81.384 25.92 ;
    END
  END a_par_out[236]
  PIN a_par_out[237]
    DIRECTION OUTPUT ;
    USE SIGNAL ;
    PORT
      LAYER M3 ;
        RECT  81.504 25.882 81.522 25.92 ;
    END
  END a_par_out[237]
  PIN a_par_out[238]
    DIRECTION OUTPUT ;
    USE SIGNAL ;
    PORT
      LAYER M5 ;
        RECT  81.744 25.836 81.768 25.92 ;
    END
  END a_par_out[238]
  PIN a_par_out[239]
    DIRECTION OUTPUT ;
    USE SIGNAL ;
    PORT
      LAYER M3 ;
        RECT  81.972 25.882 81.99 25.92 ;
    END
  END a_par_out[239]
  PIN a_par_out[23]
    DIRECTION OUTPUT ;
    USE SIGNAL ;
    PORT
      LAYER M3 ;
        RECT  17.748 25.882 17.766 25.92 ;
    END
  END a_par_out[23]
  PIN a_par_out[240]
    DIRECTION OUTPUT ;
    USE SIGNAL ;
    PORT
      LAYER M5 ;
        RECT  82.128 25.836 82.152 25.92 ;
    END
  END a_par_out[240]
  PIN a_par_out[241]
    DIRECTION OUTPUT ;
    USE SIGNAL ;
    PORT
      LAYER M3 ;
        RECT  82.368 25.882 82.386 25.92 ;
    END
  END a_par_out[241]
  PIN a_par_out[242]
    DIRECTION OUTPUT ;
    USE SIGNAL ;
    PORT
      LAYER M5 ;
        RECT  82.512 25.836 82.536 25.92 ;
    END
  END a_par_out[242]
  PIN a_par_out[243]
    DIRECTION OUTPUT ;
    USE SIGNAL ;
    PORT
      LAYER M3 ;
        RECT  82.728 25.882 82.746 25.92 ;
    END
  END a_par_out[243]
  PIN a_par_out[244]
    DIRECTION OUTPUT ;
    USE SIGNAL ;
    PORT
      LAYER M5 ;
        RECT  82.992 25.836 83.016 25.92 ;
    END
  END a_par_out[244]
  PIN a_par_out[245]
    DIRECTION OUTPUT ;
    USE SIGNAL ;
    PORT
      LAYER M3 ;
        RECT  83.124 25.882 83.142 25.92 ;
    END
  END a_par_out[245]
  PIN a_par_out[246]
    DIRECTION OUTPUT ;
    USE SIGNAL ;
    PORT
      LAYER M5 ;
        RECT  83.376 25.836 83.4 25.92 ;
    END
  END a_par_out[246]
  PIN a_par_out[247]
    DIRECTION OUTPUT ;
    USE SIGNAL ;
    PORT
      LAYER M3 ;
        RECT  83.592 25.882 83.61 25.92 ;
    END
  END a_par_out[247]
  PIN a_par_out[248]
    DIRECTION OUTPUT ;
    USE SIGNAL ;
    PORT
      LAYER M5 ;
        RECT  83.76 25.836 83.784 25.92 ;
    END
  END a_par_out[248]
  PIN a_par_out[249]
    DIRECTION OUTPUT ;
    USE SIGNAL ;
    PORT
      LAYER M3 ;
        RECT  83.988 25.882 84.006 25.92 ;
    END
  END a_par_out[249]
  PIN a_par_out[24]
    DIRECTION OUTPUT ;
    USE SIGNAL ;
    PORT
      LAYER M5 ;
        RECT  17.904 25.836 17.928 25.92 ;
    END
  END a_par_out[24]
  PIN a_par_out[250]
    DIRECTION OUTPUT ;
    USE SIGNAL ;
    PORT
      LAYER M5 ;
        RECT  84.24 25.836 84.264 25.92 ;
    END
  END a_par_out[250]
  PIN a_par_out[251]
    DIRECTION OUTPUT ;
    USE SIGNAL ;
    PORT
      LAYER M3 ;
        RECT  84.384 25.882 84.402 25.92 ;
    END
  END a_par_out[251]
  PIN a_par_out[252]
    DIRECTION OUTPUT ;
    USE SIGNAL ;
    PORT
      LAYER M5 ;
        RECT  84.624 25.836 84.648 25.92 ;
    END
  END a_par_out[252]
  PIN a_par_out[253]
    DIRECTION OUTPUT ;
    USE SIGNAL ;
    PORT
      LAYER M3 ;
        RECT  84.744 25.882 84.762 25.92 ;
    END
  END a_par_out[253]
  PIN a_par_out[254]
    DIRECTION OUTPUT ;
    USE SIGNAL ;
    PORT
      LAYER M5 ;
        RECT  85.008 25.836 85.032 25.92 ;
    END
  END a_par_out[254]
  PIN a_par_out[255]
    DIRECTION OUTPUT ;
    USE SIGNAL ;
    PORT
      LAYER M3 ;
        RECT  85.248 25.882 85.266 25.92 ;
    END
  END a_par_out[255]
  PIN a_par_out[25]
    DIRECTION OUTPUT ;
    USE SIGNAL ;
    PORT
      LAYER M3 ;
        RECT  18.144 25.882 18.162 25.92 ;
    END
  END a_par_out[25]
  PIN a_par_out[26]
    DIRECTION OUTPUT ;
    USE SIGNAL ;
    PORT
      LAYER M5 ;
        RECT  18.384 25.836 18.408 25.92 ;
    END
  END a_par_out[26]
  PIN a_par_out[27]
    DIRECTION OUTPUT ;
    USE SIGNAL ;
    PORT
      LAYER M3 ;
        RECT  18.504 25.882 18.522 25.92 ;
    END
  END a_par_out[27]
  PIN a_par_out[28]
    DIRECTION OUTPUT ;
    USE SIGNAL ;
    PORT
      LAYER M5 ;
        RECT  18.768 25.836 18.792 25.92 ;
    END
  END a_par_out[28]
  PIN a_par_out[29]
    DIRECTION OUTPUT ;
    USE SIGNAL ;
    PORT
      LAYER M3 ;
        RECT  18.9 25.882 18.918 25.92 ;
    END
  END a_par_out[29]
  PIN a_par_out[2]
    DIRECTION OUTPUT ;
    USE SIGNAL ;
    PORT
      LAYER M5 ;
        RECT  13.392 25.836 13.416 25.92 ;
    END
  END a_par_out[2]
  PIN a_par_out[30]
    DIRECTION OUTPUT ;
    USE SIGNAL ;
    PORT
      LAYER M5 ;
        RECT  19.152 25.836 19.176 25.92 ;
    END
  END a_par_out[30]
  PIN a_par_out[31]
    DIRECTION OUTPUT ;
    USE SIGNAL ;
    PORT
      LAYER M3 ;
        RECT  19.368 25.882 19.386 25.92 ;
    END
  END a_par_out[31]
  PIN a_par_out[32]
    DIRECTION OUTPUT ;
    USE SIGNAL ;
    PORT
      LAYER M5 ;
        RECT  19.536 25.836 19.56 25.92 ;
    END
  END a_par_out[32]
  PIN a_par_out[33]
    DIRECTION OUTPUT ;
    USE SIGNAL ;
    PORT
      LAYER M3 ;
        RECT  19.764 25.882 19.782 25.92 ;
    END
  END a_par_out[33]
  PIN a_par_out[34]
    DIRECTION OUTPUT ;
    USE SIGNAL ;
    PORT
      LAYER M5 ;
        RECT  20.016 25.836 20.04 25.92 ;
    END
  END a_par_out[34]
  PIN a_par_out[35]
    DIRECTION OUTPUT ;
    USE SIGNAL ;
    PORT
      LAYER M3 ;
        RECT  20.34 25.882 20.358 25.92 ;
    END
  END a_par_out[35]
  PIN a_par_out[36]
    DIRECTION OUTPUT ;
    USE SIGNAL ;
    PORT
      LAYER M5 ;
        RECT  20.688 25.836 20.712 25.92 ;
    END
  END a_par_out[36]
  PIN a_par_out[37]
    DIRECTION OUTPUT ;
    USE SIGNAL ;
    PORT
      LAYER M3 ;
        RECT  21.096 25.882 21.114 25.92 ;
    END
    PORT
      LAYER M3 ;
        RECT  21.096 23.933 21.114 25.901 ;
    END
  END a_par_out[37]
  PIN a_par_out[38]
    DIRECTION OUTPUT ;
    USE SIGNAL ;
    PORT
      LAYER M5 ;
        RECT  21.552 25.836 21.576 25.92 ;
    END
  END a_par_out[38]
  PIN a_par_out[39]
    DIRECTION OUTPUT ;
    USE SIGNAL ;
    PORT
      LAYER M3 ;
        RECT  21.96 25.882 21.978 25.92 ;
    END
    PORT
      LAYER M3 ;
        RECT  21.96 25.805 21.978 25.901 ;
    END
  END a_par_out[39]
  PIN a_par_out[3]
    DIRECTION OUTPUT ;
    USE SIGNAL ;
    PORT
      LAYER M3 ;
        RECT  13.608 25.882 13.626 25.92 ;
    END
  END a_par_out[3]
  PIN a_par_out[40]
    DIRECTION OUTPUT ;
    USE SIGNAL ;
    PORT
      LAYER M5 ;
        RECT  22.416 25.836 22.44 25.92 ;
    END
  END a_par_out[40]
  PIN a_par_out[41]
    DIRECTION OUTPUT ;
    USE SIGNAL ;
    PORT
      LAYER M3 ;
        RECT  22.752 25.882 22.77 25.92 ;
    END
    PORT
      LAYER M3 ;
        RECT  22.752 25.805 22.77 25.901 ;
    END
  END a_par_out[41]
  PIN a_par_out[42]
    DIRECTION OUTPUT ;
    USE SIGNAL ;
    PORT
      LAYER M5 ;
        RECT  23.184 25.836 23.208 25.92 ;
    END
  END a_par_out[42]
  PIN a_par_out[43]
    DIRECTION OUTPUT ;
    USE SIGNAL ;
    PORT
      LAYER M3 ;
        RECT  23.616 25.882 23.634 25.92 ;
    END
    PORT
      LAYER M3 ;
        RECT  23.616 24.509 23.634 25.901 ;
    END
  END a_par_out[43]
  PIN a_par_out[44]
    DIRECTION OUTPUT ;
    USE SIGNAL ;
    PORT
      LAYER M5 ;
        RECT  24.048 25.836 24.072 25.92 ;
    END
  END a_par_out[44]
  PIN a_par_out[45]
    DIRECTION OUTPUT ;
    USE SIGNAL ;
    PORT
      LAYER M3 ;
        RECT  24.372 25.882 24.39 25.92 ;
    END
    PORT
      LAYER M3 ;
        RECT  24.372 24.509 24.39 25.901 ;
    END
  END a_par_out[45]
  PIN a_par_out[46]
    DIRECTION OUTPUT ;
    USE SIGNAL ;
    PORT
      LAYER M5 ;
        RECT  24.816 25.836 24.84 25.92 ;
    END
  END a_par_out[46]
  PIN a_par_out[47]
    DIRECTION OUTPUT ;
    USE SIGNAL ;
    PORT
      LAYER M3 ;
        RECT  25.236 25.882 25.254 25.92 ;
    END
    PORT
      LAYER M3 ;
        RECT  25.236 23.933 25.254 25.901 ;
    END
  END a_par_out[47]
  PIN a_par_out[48]
    DIRECTION OUTPUT ;
    USE SIGNAL ;
    PORT
      LAYER M5 ;
        RECT  25.68 25.836 25.704 25.92 ;
    END
  END a_par_out[48]
  PIN a_par_out[49]
    DIRECTION OUTPUT ;
    USE SIGNAL ;
    PORT
      LAYER M3 ;
        RECT  25.992 25.882 26.01 25.92 ;
    END
    PORT
      LAYER M3 ;
        RECT  25.992 25.805 26.01 25.901 ;
    END
  END a_par_out[49]
  PIN a_par_out[4]
    DIRECTION OUTPUT ;
    USE SIGNAL ;
    PORT
      LAYER M5 ;
        RECT  13.872 25.836 13.896 25.92 ;
    END
  END a_par_out[4]
  PIN a_par_out[50]
    DIRECTION OUTPUT ;
    USE SIGNAL ;
    PORT
      LAYER M5 ;
        RECT  26.448 25.836 26.472 25.92 ;
    END
  END a_par_out[50]
  PIN a_par_out[51]
    DIRECTION OUTPUT ;
    USE SIGNAL ;
    PORT
      LAYER M3 ;
        RECT  26.856 25.882 26.874 25.92 ;
    END
    PORT
      LAYER M3 ;
        RECT  26.856 25.805 26.874 25.901 ;
    END
  END a_par_out[51]
  PIN a_par_out[52]
    DIRECTION OUTPUT ;
    USE SIGNAL ;
    PORT
      LAYER M5 ;
        RECT  27.312 25.836 27.336 25.92 ;
    END
  END a_par_out[52]
  PIN a_par_out[53]
    DIRECTION OUTPUT ;
    USE SIGNAL ;
    PORT
      LAYER M3 ;
        RECT  27.648 25.882 27.666 25.92 ;
    END
    PORT
      LAYER M3 ;
        RECT  27.648 23.933 27.666 25.901 ;
    END
  END a_par_out[53]
  PIN a_par_out[54]
    DIRECTION OUTPUT ;
    USE SIGNAL ;
    PORT
      LAYER M5 ;
        RECT  28.08 25.836 28.104 25.92 ;
    END
  END a_par_out[54]
  PIN a_par_out[55]
    DIRECTION OUTPUT ;
    USE SIGNAL ;
    PORT
      LAYER M3 ;
        RECT  28.512 25.882 28.53 25.92 ;
    END
    PORT
      LAYER M3 ;
        RECT  28.512 25.805 28.53 25.901 ;
    END
  END a_par_out[55]
  PIN a_par_out[56]
    DIRECTION OUTPUT ;
    USE SIGNAL ;
    PORT
      LAYER M5 ;
        RECT  28.944 25.836 28.968 25.92 ;
    END
  END a_par_out[56]
  PIN a_par_out[57]
    DIRECTION OUTPUT ;
    USE SIGNAL ;
    PORT
      LAYER M3 ;
        RECT  29.376 25.882 29.394 25.92 ;
    END
    PORT
      LAYER M3 ;
        RECT  29.376 25.805 29.394 25.901 ;
    END
  END a_par_out[57]
  PIN a_par_out[58]
    DIRECTION OUTPUT ;
    USE SIGNAL ;
    PORT
      LAYER M5 ;
        RECT  29.712 25.836 29.736 25.92 ;
    END
  END a_par_out[58]
  PIN a_par_out[59]
    DIRECTION OUTPUT ;
    USE SIGNAL ;
    PORT
      LAYER M3 ;
        RECT  30.132 25.882 30.15 25.92 ;
    END
    PORT
      LAYER M3 ;
        RECT  30.132 25.133 30.15 25.901 ;
    END
  END a_par_out[59]
  PIN a_par_out[5]
    DIRECTION OUTPUT ;
    USE SIGNAL ;
    PORT
      LAYER M3 ;
        RECT  14.004 25.882 14.022 25.92 ;
    END
  END a_par_out[5]
  PIN a_par_out[60]
    DIRECTION OUTPUT ;
    USE SIGNAL ;
    PORT
      LAYER M5 ;
        RECT  30.576 25.836 30.6 25.92 ;
    END
  END a_par_out[60]
  PIN a_par_out[61]
    DIRECTION OUTPUT ;
    USE SIGNAL ;
    PORT
      LAYER M3 ;
        RECT  30.996 25.882 31.014 25.92 ;
    END
    PORT
      LAYER M3 ;
        RECT  30.996 25.133 31.014 25.901 ;
    END
  END a_par_out[61]
  PIN a_par_out[62]
    DIRECTION OUTPUT ;
    USE SIGNAL ;
    PORT
      LAYER M5 ;
        RECT  31.344 25.836 31.368 25.92 ;
    END
  END a_par_out[62]
  PIN a_par_out[63]
    DIRECTION OUTPUT ;
    USE SIGNAL ;
    PORT
      LAYER M3 ;
        RECT  31.752 25.882 31.77 25.92 ;
    END
    PORT
      LAYER M3 ;
        RECT  31.752 25.805 31.77 25.901 ;
    END
  END a_par_out[63]
  PIN a_par_out[64]
    DIRECTION OUTPUT ;
    USE SIGNAL ;
    PORT
      LAYER M5 ;
        RECT  32.208 25.836 32.232 25.92 ;
    END
  END a_par_out[64]
  PIN a_par_out[65]
    DIRECTION OUTPUT ;
    USE SIGNAL ;
    PORT
      LAYER M3 ;
        RECT  32.616 25.882 32.634 25.92 ;
    END
    PORT
      LAYER M3 ;
        RECT  32.616 25.805 32.634 25.901 ;
    END
  END a_par_out[65]
  PIN a_par_out[66]
    DIRECTION OUTPUT ;
    USE SIGNAL ;
    PORT
      LAYER M5 ;
        RECT  32.976 25.836 33 25.92 ;
    END
  END a_par_out[66]
  PIN a_par_out[67]
    DIRECTION OUTPUT ;
    USE SIGNAL ;
    PORT
      LAYER M3 ;
        RECT  33.408 25.882 33.426 25.92 ;
    END
    PORT
      LAYER M3 ;
        RECT  33.408 25.133 33.426 25.901 ;
    END
  END a_par_out[67]
  PIN a_par_out[68]
    DIRECTION OUTPUT ;
    USE SIGNAL ;
    PORT
      LAYER M5 ;
        RECT  33.84 25.836 33.864 25.92 ;
    END
  END a_par_out[68]
  PIN a_par_out[69]
    DIRECTION OUTPUT ;
    USE SIGNAL ;
    PORT
      LAYER M3 ;
        RECT  34.272 25.882 34.29 25.92 ;
    END
    PORT
      LAYER M3 ;
        RECT  34.272 25.889 34.29 25.901 ;
    END
  END a_par_out[69]
  PIN a_par_out[6]
    DIRECTION OUTPUT ;
    USE SIGNAL ;
    PORT
      LAYER M5 ;
        RECT  14.256 25.836 14.28 25.92 ;
    END
  END a_par_out[6]
  PIN a_par_out[70]
    DIRECTION OUTPUT ;
    USE SIGNAL ;
    PORT
      LAYER M5 ;
        RECT  34.608 25.836 34.632 25.92 ;
    END
  END a_par_out[70]
  PIN a_par_out[71]
    DIRECTION OUTPUT ;
    USE SIGNAL ;
    PORT
      LAYER M3 ;
        RECT  35.028 25.882 35.046 25.92 ;
    END
    PORT
      LAYER M3 ;
        RECT  35.028 25.889 35.046 25.901 ;
    END
  END a_par_out[71]
  PIN a_par_out[72]
    DIRECTION OUTPUT ;
    USE SIGNAL ;
    PORT
      LAYER M5 ;
        RECT  35.472 25.836 35.496 25.92 ;
    END
  END a_par_out[72]
  PIN a_par_out[73]
    DIRECTION OUTPUT ;
    USE SIGNAL ;
    PORT
      LAYER M3 ;
        RECT  35.892 25.882 35.91 25.92 ;
    END
    PORT
      LAYER M3 ;
        RECT  35.892 25.805 35.91 25.901 ;
    END
  END a_par_out[73]
  PIN a_par_out[74]
    DIRECTION OUTPUT ;
    USE SIGNAL ;
    PORT
      LAYER M5 ;
        RECT  36.336 25.836 36.36 25.92 ;
    END
  END a_par_out[74]
  PIN a_par_out[75]
    DIRECTION OUTPUT ;
    USE SIGNAL ;
    PORT
      LAYER M3 ;
        RECT  36.648 25.882 36.666 25.92 ;
    END
    PORT
      LAYER M3 ;
        RECT  36.648 25.805 36.666 25.901 ;
    END
  END a_par_out[75]
  PIN a_par_out[76]
    DIRECTION OUTPUT ;
    USE SIGNAL ;
    PORT
      LAYER M5 ;
        RECT  37.104 25.836 37.128 25.92 ;
    END
  END a_par_out[76]
  PIN a_par_out[77]
    DIRECTION OUTPUT ;
    USE SIGNAL ;
    PORT
      LAYER M3 ;
        RECT  37.512 25.882 37.53 25.92 ;
    END
    PORT
      LAYER M3 ;
        RECT  37.512 23.933 37.53 25.901 ;
    END
  END a_par_out[77]
  PIN a_par_out[78]
    DIRECTION OUTPUT ;
    USE SIGNAL ;
    PORT
      LAYER M5 ;
        RECT  37.968 25.836 37.992 25.92 ;
    END
  END a_par_out[78]
  PIN a_par_out[79]
    DIRECTION OUTPUT ;
    USE SIGNAL ;
    PORT
      LAYER M3 ;
        RECT  38.304 25.882 38.322 25.92 ;
    END
    PORT
      LAYER M3 ;
        RECT  38.304 23.933 38.322 25.901 ;
    END
  END a_par_out[79]
  PIN a_par_out[7]
    DIRECTION OUTPUT ;
    USE SIGNAL ;
    PORT
      LAYER M3 ;
        RECT  14.4 25.882 14.418 25.92 ;
    END
  END a_par_out[7]
  PIN a_par_out[80]
    DIRECTION OUTPUT ;
    USE SIGNAL ;
    PORT
      LAYER M5 ;
        RECT  38.736 25.836 38.76 25.92 ;
    END
  END a_par_out[80]
  PIN a_par_out[81]
    DIRECTION OUTPUT ;
    USE SIGNAL ;
    PORT
      LAYER M3 ;
        RECT  39.168 25.882 39.186 25.92 ;
    END
    PORT
      LAYER M3 ;
        RECT  39.168 25.805 39.186 25.901 ;
    END
  END a_par_out[81]
  PIN a_par_out[82]
    DIRECTION OUTPUT ;
    USE SIGNAL ;
    PORT
      LAYER M5 ;
        RECT  39.6 25.836 39.624 25.92 ;
    END
  END a_par_out[82]
  PIN a_par_out[83]
    DIRECTION OUTPUT ;
    USE SIGNAL ;
    PORT
      LAYER M3 ;
        RECT  39.924 25.882 39.942 25.92 ;
    END
    PORT
      LAYER M3 ;
        RECT  39.924 25.805 39.942 25.901 ;
    END
  END a_par_out[83]
  PIN a_par_out[84]
    DIRECTION OUTPUT ;
    USE SIGNAL ;
    PORT
      LAYER M5 ;
        RECT  40.368 25.836 40.392 25.92 ;
    END
  END a_par_out[84]
  PIN a_par_out[85]
    DIRECTION OUTPUT ;
    USE SIGNAL ;
    PORT
      LAYER M3 ;
        RECT  40.788 25.882 40.806 25.92 ;
    END
    PORT
      LAYER M3 ;
        RECT  40.788 25.889 40.806 25.901 ;
    END
  END a_par_out[85]
  PIN a_par_out[86]
    DIRECTION OUTPUT ;
    USE SIGNAL ;
    PORT
      LAYER M5 ;
        RECT  41.232 25.836 41.256 25.92 ;
    END
  END a_par_out[86]
  PIN a_par_out[87]
    DIRECTION OUTPUT ;
    USE SIGNAL ;
    PORT
      LAYER M3 ;
        RECT  41.544 25.882 41.562 25.92 ;
    END
    PORT
      LAYER M3 ;
        RECT  41.544 25.889 41.562 25.901 ;
    END
  END a_par_out[87]
  PIN a_par_out[88]
    DIRECTION OUTPUT ;
    USE SIGNAL ;
    PORT
      LAYER M5 ;
        RECT  42 25.836 42.024 25.92 ;
    END
  END a_par_out[88]
  PIN a_par_out[89]
    DIRECTION OUTPUT ;
    USE SIGNAL ;
    PORT
      LAYER M3 ;
        RECT  42.408 25.882 42.426 25.92 ;
    END
    PORT
      LAYER M3 ;
        RECT  42.408 25.861 42.498 25.889 ;
    END
    PORT
      LAYER M3 ;
        RECT  42.408 25.889 42.426 25.901 ;
    END
  END a_par_out[89]
  PIN a_par_out[8]
    DIRECTION OUTPUT ;
    USE SIGNAL ;
    PORT
      LAYER M5 ;
        RECT  14.64 25.836 14.664 25.92 ;
    END
  END a_par_out[8]
  PIN a_par_out[90]
    DIRECTION OUTPUT ;
    USE SIGNAL ;
    PORT
      LAYER M5 ;
        RECT  42.864 25.836 42.888 25.92 ;
    END
  END a_par_out[90]
  PIN a_par_out[91]
    DIRECTION OUTPUT ;
    USE SIGNAL ;
    PORT
      LAYER M3 ;
        RECT  43.272 25.882 43.29 25.92 ;
    END
    PORT
      LAYER M3 ;
        RECT  43.272 25.805 43.29 25.901 ;
    END
  END a_par_out[91]
  PIN a_par_out[92]
    DIRECTION OUTPUT ;
    USE SIGNAL ;
    PORT
      LAYER M5 ;
        RECT  43.632 25.836 43.656 25.92 ;
    END
  END a_par_out[92]
  PIN a_par_out[93]
    DIRECTION OUTPUT ;
    USE SIGNAL ;
    PORT
      LAYER M3 ;
        RECT  44.064 25.882 44.082 25.92 ;
    END
    PORT
      LAYER M3 ;
        RECT  44.064 25.861 44.154 25.889 ;
    END
    PORT
      LAYER M3 ;
        RECT  44.064 25.889 44.082 25.901 ;
    END
  END a_par_out[93]
  PIN a_par_out[94]
    DIRECTION OUTPUT ;
    USE SIGNAL ;
    PORT
      LAYER M5 ;
        RECT  44.496 25.836 44.52 25.92 ;
    END
  END a_par_out[94]
  PIN a_par_out[95]
    DIRECTION OUTPUT ;
    USE SIGNAL ;
    PORT
      LAYER M3 ;
        RECT  44.928 25.882 44.946 25.92 ;
    END
    PORT
      LAYER M3 ;
        RECT  44.928 23.933 44.946 25.901 ;
    END
  END a_par_out[95]
  PIN a_par_out[96]
    DIRECTION OUTPUT ;
    USE SIGNAL ;
    PORT
      LAYER M5 ;
        RECT  45.264 25.836 45.288 25.92 ;
    END
  END a_par_out[96]
  PIN a_par_out[97]
    DIRECTION OUTPUT ;
    USE SIGNAL ;
    PORT
      LAYER M3 ;
        RECT  45.684 25.882 45.702 25.92 ;
    END
    PORT
      LAYER M3 ;
        RECT  45.684 23.933 45.702 25.901 ;
    END
  END a_par_out[97]
  PIN a_par_out[98]
    DIRECTION OUTPUT ;
    USE SIGNAL ;
    PORT
      LAYER M5 ;
        RECT  46.128 25.836 46.152 25.92 ;
    END
  END a_par_out[98]
  PIN a_par_out[99]
    DIRECTION OUTPUT ;
    USE SIGNAL ;
    PORT
      LAYER M3 ;
        RECT  46.548 25.882 46.566 25.92 ;
    END
    PORT
      LAYER M3 ;
        RECT  46.548 24.509 46.566 25.901 ;
    END
  END a_par_out[99]
  PIN a_par_out[9]
    DIRECTION OUTPUT ;
    USE SIGNAL ;
    PORT
      LAYER M3 ;
        RECT  14.868 25.882 14.886 25.92 ;
    END
  END a_par_out[9]
  PIN b_par[0]
    DIRECTION INPUT ;
    USE SIGNAL ;
    PORT
      LAYER M5 ;
        RECT  85.392 0 85.416 0.084 ;
    END
  END b_par[0]
  PIN b_par[100]
    DIRECTION INPUT ;
    USE SIGNAL ;
    PORT
      LAYER M5 ;
        RECT  105.936 0 105.96 0.084 ;
    END
  END b_par[100]
  PIN b_par[101]
    DIRECTION INPUT ;
    USE SIGNAL ;
    PORT
      LAYER M3 ;
        RECT  106.056 0 106.074 0.038 ;
    END
  END b_par[101]
  PIN b_par[102]
    DIRECTION INPUT ;
    USE SIGNAL ;
    PORT
      LAYER M5 ;
        RECT  106.32 0 106.344 0.084 ;
    END
  END b_par[102]
  PIN b_par[103]
    DIRECTION INPUT ;
    USE SIGNAL ;
    PORT
      LAYER M3 ;
        RECT  106.56 0 106.578 0.038 ;
    END
  END b_par[103]
  PIN b_par[104]
    DIRECTION INPUT ;
    USE SIGNAL ;
    PORT
      LAYER M5 ;
        RECT  106.704 0 106.728 0.084 ;
    END
  END b_par[104]
  PIN b_par[105]
    DIRECTION INPUT ;
    USE SIGNAL ;
    PORT
      LAYER M3 ;
        RECT  106.92 0 106.938 0.038 ;
    END
  END b_par[105]
  PIN b_par[106]
    DIRECTION INPUT ;
    USE SIGNAL ;
    PORT
      LAYER M5 ;
        RECT  107.088 0 107.112 0.084 ;
    END
  END b_par[106]
  PIN b_par[107]
    DIRECTION INPUT ;
    USE SIGNAL ;
    PORT
      LAYER M3 ;
        RECT  107.316 0 107.334 0.038 ;
    END
  END b_par[107]
  PIN b_par[108]
    DIRECTION INPUT ;
    USE SIGNAL ;
    PORT
      LAYER M5 ;
        RECT  107.568 0 107.592 0.084 ;
    END
  END b_par[108]
  PIN b_par[109]
    DIRECTION INPUT ;
    USE SIGNAL ;
    PORT
      LAYER M3 ;
        RECT  107.712 0 107.73 0.038 ;
    END
  END b_par[109]
  PIN b_par[10]
    DIRECTION INPUT ;
    USE SIGNAL ;
    PORT
      LAYER M5 ;
        RECT  87.504 0 87.528 0.084 ;
    END
  END b_par[10]
  PIN b_par[110]
    DIRECTION INPUT ;
    USE SIGNAL ;
    PORT
      LAYER M5 ;
        RECT  107.952 0 107.976 0.084 ;
    END
  END b_par[110]
  PIN b_par[111]
    DIRECTION INPUT ;
    USE SIGNAL ;
    PORT
      LAYER M3 ;
        RECT  108.18 0 108.198 0.038 ;
    END
  END b_par[111]
  PIN b_par[112]
    DIRECTION INPUT ;
    USE SIGNAL ;
    PORT
      LAYER M5 ;
        RECT  108.336 0 108.36 0.084 ;
    END
  END b_par[112]
  PIN b_par[113]
    DIRECTION INPUT ;
    USE SIGNAL ;
    PORT
      LAYER M3 ;
        RECT  108.576 0 108.594 0.038 ;
    END
  END b_par[113]
  PIN b_par[114]
    DIRECTION INPUT ;
    USE SIGNAL ;
    PORT
      LAYER M5 ;
        RECT  108.72 0 108.744 0.084 ;
    END
  END b_par[114]
  PIN b_par[115]
    DIRECTION INPUT ;
    USE SIGNAL ;
    PORT
      LAYER M3 ;
        RECT  108.936 0 108.954 0.038 ;
    END
  END b_par[115]
  PIN b_par[116]
    DIRECTION INPUT ;
    USE SIGNAL ;
    PORT
      LAYER M5 ;
        RECT  109.2 0 109.224 0.084 ;
    END
  END b_par[116]
  PIN b_par[117]
    DIRECTION INPUT ;
    USE SIGNAL ;
    PORT
      LAYER M3 ;
        RECT  109.332 0 109.35 0.038 ;
    END
  END b_par[117]
  PIN b_par[118]
    DIRECTION INPUT ;
    USE SIGNAL ;
    PORT
      LAYER M5 ;
        RECT  109.584 0 109.608 0.084 ;
    END
  END b_par[118]
  PIN b_par[119]
    DIRECTION INPUT ;
    USE SIGNAL ;
    PORT
      LAYER M3 ;
        RECT  109.8 0 109.818 0.038 ;
    END
  END b_par[119]
  PIN b_par[11]
    DIRECTION INPUT ;
    USE SIGNAL ;
    PORT
      LAYER M3 ;
        RECT  87.624 0 87.642 0.038 ;
    END
  END b_par[11]
  PIN b_par[120]
    DIRECTION INPUT ;
    USE SIGNAL ;
    PORT
      LAYER M5 ;
        RECT  109.968 0 109.992 0.084 ;
    END
  END b_par[120]
  PIN b_par[121]
    DIRECTION INPUT ;
    USE SIGNAL ;
    PORT
      LAYER M3 ;
        RECT  110.196 0 110.214 0.038 ;
    END
  END b_par[121]
  PIN b_par[122]
    DIRECTION INPUT ;
    USE SIGNAL ;
    PORT
      LAYER M5 ;
        RECT  110.448 0 110.472 0.084 ;
    END
  END b_par[122]
  PIN b_par[123]
    DIRECTION INPUT ;
    USE SIGNAL ;
    PORT
      LAYER M3 ;
        RECT  110.592 0 110.61 0.038 ;
    END
  END b_par[123]
  PIN b_par[124]
    DIRECTION INPUT ;
    USE SIGNAL ;
    PORT
      LAYER M5 ;
        RECT  110.832 0 110.856 0.084 ;
    END
  END b_par[124]
  PIN b_par[125]
    DIRECTION INPUT ;
    USE SIGNAL ;
    PORT
      LAYER M3 ;
        RECT  110.952 0 110.97 0.038 ;
    END
  END b_par[125]
  PIN b_par[126]
    DIRECTION INPUT ;
    USE SIGNAL ;
    PORT
      LAYER M5 ;
        RECT  111.216 0 111.24 0.084 ;
    END
  END b_par[126]
  PIN b_par[127]
    DIRECTION INPUT ;
    USE SIGNAL ;
    PORT
      LAYER M3 ;
        RECT  111.456 0 111.474 0.038 ;
    END
  END b_par[127]
  PIN b_par[128]
    DIRECTION INPUT ;
    USE SIGNAL ;
    PORT
      LAYER M5 ;
        RECT  111.6 0 111.624 0.084 ;
    END
  END b_par[128]
  PIN b_par[129]
    DIRECTION INPUT ;
    USE SIGNAL ;
    PORT
      LAYER M3 ;
        RECT  111.816 0 111.834 0.038 ;
    END
  END b_par[129]
  PIN b_par[12]
    DIRECTION INPUT ;
    USE SIGNAL ;
    PORT
      LAYER M5 ;
        RECT  87.888 0 87.912 0.084 ;
    END
  END b_par[12]
  PIN b_par[130]
    DIRECTION INPUT ;
    USE SIGNAL ;
    PORT
      LAYER M5 ;
        RECT  112.08 0 112.104 0.084 ;
    END
  END b_par[130]
  PIN b_par[131]
    DIRECTION INPUT ;
    USE SIGNAL ;
    PORT
      LAYER M3 ;
        RECT  112.212 0 112.23 0.038 ;
    END
  END b_par[131]
  PIN b_par[132]
    DIRECTION INPUT ;
    USE SIGNAL ;
    PORT
      LAYER M5 ;
        RECT  112.464 0 112.488 0.084 ;
    END
  END b_par[132]
  PIN b_par[133]
    DIRECTION INPUT ;
    USE SIGNAL ;
    PORT
      LAYER M3 ;
        RECT  112.608 0 112.626 0.038 ;
    END
  END b_par[133]
  PIN b_par[134]
    DIRECTION INPUT ;
    USE SIGNAL ;
    PORT
      LAYER M5 ;
        RECT  112.848 0 112.872 0.084 ;
    END
  END b_par[134]
  PIN b_par[135]
    DIRECTION INPUT ;
    USE SIGNAL ;
    PORT
      LAYER M3 ;
        RECT  113.076 0 113.094 0.038 ;
    END
  END b_par[135]
  PIN b_par[136]
    DIRECTION INPUT ;
    USE SIGNAL ;
    PORT
      LAYER M5 ;
        RECT  113.232 0 113.256 0.084 ;
    END
  END b_par[136]
  PIN b_par[137]
    DIRECTION INPUT ;
    USE SIGNAL ;
    PORT
      LAYER M3 ;
        RECT  113.472 0 113.49 0.038 ;
    END
  END b_par[137]
  PIN b_par[138]
    DIRECTION INPUT ;
    USE SIGNAL ;
    PORT
      LAYER M5 ;
        RECT  113.712 0 113.736 0.084 ;
    END
  END b_par[138]
  PIN b_par[139]
    DIRECTION INPUT ;
    USE SIGNAL ;
    PORT
      LAYER M3 ;
        RECT  113.832 0 113.85 0.038 ;
    END
  END b_par[139]
  PIN b_par[13]
    DIRECTION INPUT ;
    USE SIGNAL ;
    PORT
      LAYER M3 ;
        RECT  88.128 0 88.146 0.038 ;
    END
  END b_par[13]
  PIN b_par[140]
    DIRECTION INPUT ;
    USE SIGNAL ;
    PORT
      LAYER M5 ;
        RECT  114.096 0 114.12 0.084 ;
    END
  END b_par[140]
  PIN b_par[141]
    DIRECTION INPUT ;
    USE SIGNAL ;
    PORT
      LAYER M3 ;
        RECT  114.336 0 114.354 0.038 ;
    END
  END b_par[141]
  PIN b_par[142]
    DIRECTION INPUT ;
    USE SIGNAL ;
    PORT
      LAYER M5 ;
        RECT  114.48 0 114.504 0.084 ;
    END
  END b_par[142]
  PIN b_par[143]
    DIRECTION INPUT ;
    USE SIGNAL ;
    PORT
      LAYER M3 ;
        RECT  114.696 0 114.714 0.038 ;
    END
  END b_par[143]
  PIN b_par[144]
    DIRECTION INPUT ;
    USE SIGNAL ;
    PORT
      LAYER M5 ;
        RECT  114.864 0 114.888 0.084 ;
    END
  END b_par[144]
  PIN b_par[145]
    DIRECTION INPUT ;
    USE SIGNAL ;
    PORT
      LAYER M3 ;
        RECT  115.092 0 115.11 0.038 ;
    END
  END b_par[145]
  PIN b_par[146]
    DIRECTION INPUT ;
    USE SIGNAL ;
    PORT
      LAYER M5 ;
        RECT  115.344 0 115.368 0.084 ;
    END
  END b_par[146]
  PIN b_par[147]
    DIRECTION INPUT ;
    USE SIGNAL ;
    PORT
      LAYER M3 ;
        RECT  115.488 0 115.506 0.038 ;
    END
  END b_par[147]
  PIN b_par[148]
    DIRECTION INPUT ;
    USE SIGNAL ;
    PORT
      LAYER M5 ;
        RECT  115.728 0 115.752 0.084 ;
    END
  END b_par[148]
  PIN b_par[149]
    DIRECTION INPUT ;
    USE SIGNAL ;
    PORT
      LAYER M3 ;
        RECT  115.956 0 115.974 0.038 ;
    END
  END b_par[149]
  PIN b_par[14]
    DIRECTION INPUT ;
    USE SIGNAL ;
    PORT
      LAYER M5 ;
        RECT  88.272 0 88.296 0.084 ;
    END
  END b_par[14]
  PIN b_par[150]
    DIRECTION INPUT ;
    USE SIGNAL ;
    PORT
      LAYER M5 ;
        RECT  116.112 0 116.136 0.084 ;
    END
  END b_par[150]
  PIN b_par[151]
    DIRECTION INPUT ;
    USE SIGNAL ;
    PORT
      LAYER M3 ;
        RECT  116.352 0 116.37 0.038 ;
    END
  END b_par[151]
  PIN b_par[152]
    DIRECTION INPUT ;
    USE SIGNAL ;
    PORT
      LAYER M5 ;
        RECT  116.592 0 116.616 0.084 ;
    END
  END b_par[152]
  PIN b_par[153]
    DIRECTION INPUT ;
    USE SIGNAL ;
    PORT
      LAYER M3 ;
        RECT  116.712 0 116.73 0.038 ;
    END
  END b_par[153]
  PIN b_par[154]
    DIRECTION INPUT ;
    USE SIGNAL ;
    PORT
      LAYER M5 ;
        RECT  116.976 0 117 0.084 ;
    END
  END b_par[154]
  PIN b_par[155]
    DIRECTION INPUT ;
    USE SIGNAL ;
    PORT
      LAYER M3 ;
        RECT  117.108 0 117.126 0.038 ;
    END
  END b_par[155]
  PIN b_par[156]
    DIRECTION INPUT ;
    USE SIGNAL ;
    PORT
      LAYER M5 ;
        RECT  117.36 0 117.384 0.084 ;
    END
  END b_par[156]
  PIN b_par[157]
    DIRECTION INPUT ;
    USE SIGNAL ;
    PORT
      LAYER M3 ;
        RECT  117.576 0 117.594 0.038 ;
    END
  END b_par[157]
  PIN b_par[158]
    DIRECTION INPUT ;
    USE SIGNAL ;
    PORT
      LAYER M5 ;
        RECT  117.744 0 117.768 0.084 ;
    END
  END b_par[158]
  PIN b_par[159]
    DIRECTION INPUT ;
    USE SIGNAL ;
    PORT
      LAYER M3 ;
        RECT  117.972 0 117.99 0.038 ;
    END
  END b_par[159]
  PIN b_par[15]
    DIRECTION INPUT ;
    USE SIGNAL ;
    PORT
      LAYER M3 ;
        RECT  88.488 0 88.506 0.038 ;
    END
  END b_par[15]
  PIN b_par[160]
    DIRECTION INPUT ;
    USE SIGNAL ;
    PORT
      LAYER M5 ;
        RECT  118.224 0 118.248 0.084 ;
    END
  END b_par[160]
  PIN b_par[161]
    DIRECTION INPUT ;
    USE SIGNAL ;
    PORT
      LAYER M3 ;
        RECT  118.368 0 118.386 0.038 ;
    END
  END b_par[161]
  PIN b_par[162]
    DIRECTION INPUT ;
    USE SIGNAL ;
    PORT
      LAYER M5 ;
        RECT  118.608 0 118.632 0.084 ;
    END
  END b_par[162]
  PIN b_par[163]
    DIRECTION INPUT ;
    USE SIGNAL ;
    PORT
      LAYER M3 ;
        RECT  118.728 0 118.746 0.038 ;
    END
  END b_par[163]
  PIN b_par[164]
    DIRECTION INPUT ;
    USE SIGNAL ;
    PORT
      LAYER M5 ;
        RECT  118.992 0 119.016 0.084 ;
    END
  END b_par[164]
  PIN b_par[165]
    DIRECTION INPUT ;
    USE SIGNAL ;
    PORT
      LAYER M3 ;
        RECT  119.232 0 119.25 0.038 ;
    END
  END b_par[165]
  PIN b_par[166]
    DIRECTION INPUT ;
    USE SIGNAL ;
    PORT
      LAYER M5 ;
        RECT  119.376 0 119.4 0.084 ;
    END
  END b_par[166]
  PIN b_par[167]
    DIRECTION INPUT ;
    USE SIGNAL ;
    PORT
      LAYER M3 ;
        RECT  119.592 0 119.61 0.038 ;
    END
  END b_par[167]
  PIN b_par[168]
    DIRECTION INPUT ;
    USE SIGNAL ;
    PORT
      LAYER M5 ;
        RECT  119.856 0 119.88 0.084 ;
    END
  END b_par[168]
  PIN b_par[169]
    DIRECTION INPUT ;
    USE SIGNAL ;
    PORT
      LAYER M3 ;
        RECT  119.988 0 120.006 0.038 ;
    END
  END b_par[169]
  PIN b_par[16]
    DIRECTION INPUT ;
    USE SIGNAL ;
    PORT
      LAYER M5 ;
        RECT  88.656 0 88.68 0.084 ;
    END
  END b_par[16]
  PIN b_par[170]
    DIRECTION INPUT ;
    USE SIGNAL ;
    PORT
      LAYER M5 ;
        RECT  120.24 0 120.264 0.084 ;
    END
  END b_par[170]
  PIN b_par[171]
    DIRECTION INPUT ;
    USE SIGNAL ;
    PORT
      LAYER M3 ;
        RECT  120.456 0 120.474 0.038 ;
    END
  END b_par[171]
  PIN b_par[172]
    DIRECTION INPUT ;
    USE SIGNAL ;
    PORT
      LAYER M5 ;
        RECT  120.624 0 120.648 0.084 ;
    END
  END b_par[172]
  PIN b_par[173]
    DIRECTION INPUT ;
    USE SIGNAL ;
    PORT
      LAYER M3 ;
        RECT  120.852 0 120.87 0.038 ;
    END
  END b_par[173]
  PIN b_par[174]
    DIRECTION INPUT ;
    USE SIGNAL ;
    PORT
      LAYER M5 ;
        RECT  121.008 0 121.032 0.084 ;
    END
  END b_par[174]
  PIN b_par[175]
    DIRECTION INPUT ;
    USE SIGNAL ;
    PORT
      LAYER M3 ;
        RECT  121.248 0 121.266 0.038 ;
    END
  END b_par[175]
  PIN b_par[176]
    DIRECTION INPUT ;
    USE SIGNAL ;
    PORT
      LAYER M5 ;
        RECT  121.488 0 121.512 0.084 ;
    END
  END b_par[176]
  PIN b_par[177]
    DIRECTION INPUT ;
    USE SIGNAL ;
    PORT
      LAYER M3 ;
        RECT  121.608 0 121.626 0.038 ;
    END
  END b_par[177]
  PIN b_par[178]
    DIRECTION INPUT ;
    USE SIGNAL ;
    PORT
      LAYER M5 ;
        RECT  121.872 0 121.896 0.084 ;
    END
  END b_par[178]
  PIN b_par[179]
    DIRECTION INPUT ;
    USE SIGNAL ;
    PORT
      LAYER M3 ;
        RECT  122.112 0 122.13 0.038 ;
    END
  END b_par[179]
  PIN b_par[17]
    DIRECTION INPUT ;
    USE SIGNAL ;
    PORT
      LAYER M3 ;
        RECT  88.884 0 88.902 0.038 ;
    END
  END b_par[17]
  PIN b_par[180]
    DIRECTION INPUT ;
    USE SIGNAL ;
    PORT
      LAYER M5 ;
        RECT  122.256 0 122.28 0.084 ;
    END
  END b_par[180]
  PIN b_par[181]
    DIRECTION INPUT ;
    USE SIGNAL ;
    PORT
      LAYER M3 ;
        RECT  122.472 0 122.49 0.038 ;
    END
  END b_par[181]
  PIN b_par[182]
    DIRECTION INPUT ;
    USE SIGNAL ;
    PORT
      LAYER M5 ;
        RECT  122.64 0 122.664 0.084 ;
    END
  END b_par[182]
  PIN b_par[183]
    DIRECTION INPUT ;
    USE SIGNAL ;
    PORT
      LAYER M3 ;
        RECT  122.868 0 122.886 0.038 ;
    END
  END b_par[183]
  PIN b_par[184]
    DIRECTION INPUT ;
    USE SIGNAL ;
    PORT
      LAYER M5 ;
        RECT  123.12 0 123.144 0.084 ;
    END
  END b_par[184]
  PIN b_par[185]
    DIRECTION INPUT ;
    USE SIGNAL ;
    PORT
      LAYER M3 ;
        RECT  123.264 0 123.282 0.038 ;
    END
  END b_par[185]
  PIN b_par[186]
    DIRECTION INPUT ;
    USE SIGNAL ;
    PORT
      LAYER M5 ;
        RECT  123.504 0 123.528 0.084 ;
    END
  END b_par[186]
  PIN b_par[187]
    DIRECTION INPUT ;
    USE SIGNAL ;
    PORT
      LAYER M3 ;
        RECT  123.732 0 123.75 0.038 ;
    END
  END b_par[187]
  PIN b_par[188]
    DIRECTION INPUT ;
    USE SIGNAL ;
    PORT
      LAYER M5 ;
        RECT  123.888 0 123.912 0.084 ;
    END
  END b_par[188]
  PIN b_par[189]
    DIRECTION INPUT ;
    USE SIGNAL ;
    PORT
      LAYER M3 ;
        RECT  124.128 0 124.146 0.038 ;
    END
  END b_par[189]
  PIN b_par[18]
    DIRECTION INPUT ;
    USE SIGNAL ;
    PORT
      LAYER M5 ;
        RECT  89.136 0 89.16 0.084 ;
    END
  END b_par[18]
  PIN b_par[190]
    DIRECTION INPUT ;
    USE SIGNAL ;
    PORT
      LAYER M5 ;
        RECT  124.368 0 124.392 0.084 ;
    END
  END b_par[190]
  PIN b_par[191]
    DIRECTION INPUT ;
    USE SIGNAL ;
    PORT
      LAYER M3 ;
        RECT  124.488 0 124.506 0.038 ;
    END
  END b_par[191]
  PIN b_par[192]
    DIRECTION INPUT ;
    USE SIGNAL ;
    PORT
      LAYER M5 ;
        RECT  124.752 0 124.776 0.084 ;
    END
  END b_par[192]
  PIN b_par[193]
    DIRECTION INPUT ;
    USE SIGNAL ;
    PORT
      LAYER M3 ;
        RECT  124.884 0 124.902 0.038 ;
    END
  END b_par[193]
  PIN b_par[194]
    DIRECTION INPUT ;
    USE SIGNAL ;
    PORT
      LAYER M5 ;
        RECT  125.136 0 125.16 0.084 ;
    END
  END b_par[194]
  PIN b_par[195]
    DIRECTION INPUT ;
    USE SIGNAL ;
    PORT
      LAYER M3 ;
        RECT  125.352 0 125.37 0.038 ;
    END
  END b_par[195]
  PIN b_par[196]
    DIRECTION INPUT ;
    USE SIGNAL ;
    PORT
      LAYER M5 ;
        RECT  125.52 0 125.544 0.084 ;
    END
  END b_par[196]
  PIN b_par[197]
    DIRECTION INPUT ;
    USE SIGNAL ;
    PORT
      LAYER M3 ;
        RECT  125.748 0 125.766 0.038 ;
    END
  END b_par[197]
  PIN b_par[198]
    DIRECTION INPUT ;
    USE SIGNAL ;
    PORT
      LAYER M5 ;
        RECT  126 0 126.024 0.084 ;
    END
  END b_par[198]
  PIN b_par[199]
    DIRECTION INPUT ;
    USE SIGNAL ;
    PORT
      LAYER M3 ;
        RECT  126.144 0 126.162 0.038 ;
    END
  END b_par[199]
  PIN b_par[19]
    DIRECTION INPUT ;
    USE SIGNAL ;
    PORT
      LAYER M3 ;
        RECT  89.28 0 89.298 0.038 ;
    END
  END b_par[19]
  PIN b_par[1]
    DIRECTION INPUT ;
    USE SIGNAL ;
    PORT
      LAYER M3 ;
        RECT  85.608 0 85.626 0.038 ;
    END
  END b_par[1]
  PIN b_par[200]
    DIRECTION INPUT ;
    USE SIGNAL ;
    PORT
      LAYER M5 ;
        RECT  126.384 0 126.408 0.084 ;
    END
  END b_par[200]
  PIN b_par[201]
    DIRECTION INPUT ;
    USE SIGNAL ;
    PORT
      LAYER M3 ;
        RECT  126.612 0 126.63 0.038 ;
    END
  END b_par[201]
  PIN b_par[202]
    DIRECTION INPUT ;
    USE SIGNAL ;
    PORT
      LAYER M5 ;
        RECT  126.768 0 126.792 0.084 ;
    END
  END b_par[202]
  PIN b_par[203]
    DIRECTION INPUT ;
    USE SIGNAL ;
    PORT
      LAYER M3 ;
        RECT  127.008 0 127.026 0.038 ;
    END
  END b_par[203]
  PIN b_par[204]
    DIRECTION INPUT ;
    USE SIGNAL ;
    PORT
      LAYER M5 ;
        RECT  127.152 0 127.176 0.084 ;
    END
  END b_par[204]
  PIN b_par[205]
    DIRECTION INPUT ;
    USE SIGNAL ;
    PORT
      LAYER M3 ;
        RECT  127.368 0 127.386 0.038 ;
    END
  END b_par[205]
  PIN b_par[206]
    DIRECTION INPUT ;
    USE SIGNAL ;
    PORT
      LAYER M5 ;
        RECT  127.632 0 127.656 0.084 ;
    END
  END b_par[206]
  PIN b_par[207]
    DIRECTION INPUT ;
    USE SIGNAL ;
    PORT
      LAYER M3 ;
        RECT  127.764 0 127.782 0.038 ;
    END
  END b_par[207]
  PIN b_par[208]
    DIRECTION INPUT ;
    USE SIGNAL ;
    PORT
      LAYER M5 ;
        RECT  128.016 0 128.04 0.084 ;
    END
  END b_par[208]
  PIN b_par[209]
    DIRECTION INPUT ;
    USE SIGNAL ;
    PORT
      LAYER M3 ;
        RECT  128.232 0 128.25 0.038 ;
    END
  END b_par[209]
  PIN b_par[20]
    DIRECTION INPUT ;
    USE SIGNAL ;
    PORT
      LAYER M5 ;
        RECT  89.52 0 89.544 0.084 ;
    END
  END b_par[20]
  PIN b_par[210]
    DIRECTION INPUT ;
    USE SIGNAL ;
    PORT
      LAYER M5 ;
        RECT  128.4 0 128.424 0.084 ;
    END
  END b_par[210]
  PIN b_par[211]
    DIRECTION INPUT ;
    USE SIGNAL ;
    PORT
      LAYER M3 ;
        RECT  128.628 0 128.646 0.038 ;
    END
  END b_par[211]
  PIN b_par[212]
    DIRECTION INPUT ;
    USE SIGNAL ;
    PORT
      LAYER M5 ;
        RECT  128.784 0 128.808 0.084 ;
    END
  END b_par[212]
  PIN b_par[213]
    DIRECTION INPUT ;
    USE SIGNAL ;
    PORT
      LAYER M3 ;
        RECT  129.024 0 129.042 0.038 ;
    END
  END b_par[213]
  PIN b_par[214]
    DIRECTION INPUT ;
    USE SIGNAL ;
    PORT
      LAYER M5 ;
        RECT  129.264 0 129.288 0.084 ;
    END
  END b_par[214]
  PIN b_par[215]
    DIRECTION INPUT ;
    USE SIGNAL ;
    PORT
      LAYER M3 ;
        RECT  129.384 0 129.402 0.038 ;
    END
  END b_par[215]
  PIN b_par[216]
    DIRECTION INPUT ;
    USE SIGNAL ;
    PORT
      LAYER M5 ;
        RECT  129.648 0 129.672 0.084 ;
    END
  END b_par[216]
  PIN b_par[217]
    DIRECTION INPUT ;
    USE SIGNAL ;
    PORT
      LAYER M3 ;
        RECT  129.888 0 129.906 0.038 ;
    END
  END b_par[217]
  PIN b_par[218]
    DIRECTION INPUT ;
    USE SIGNAL ;
    PORT
      LAYER M5 ;
        RECT  130.032 0 130.056 0.084 ;
    END
  END b_par[218]
  PIN b_par[219]
    DIRECTION INPUT ;
    USE SIGNAL ;
    PORT
      LAYER M3 ;
        RECT  130.248 0 130.266 0.038 ;
    END
  END b_par[219]
  PIN b_par[21]
    DIRECTION INPUT ;
    USE SIGNAL ;
    PORT
      LAYER M3 ;
        RECT  89.748 0 89.766 0.038 ;
    END
  END b_par[21]
  PIN b_par[220]
    DIRECTION INPUT ;
    USE SIGNAL ;
    PORT
      LAYER M5 ;
        RECT  130.512 0 130.536 0.084 ;
    END
  END b_par[220]
  PIN b_par[221]
    DIRECTION INPUT ;
    USE SIGNAL ;
    PORT
      LAYER M3 ;
        RECT  130.644 0 130.662 0.038 ;
    END
  END b_par[221]
  PIN b_par[222]
    DIRECTION INPUT ;
    USE SIGNAL ;
    PORT
      LAYER M5 ;
        RECT  130.896 0 130.92 0.084 ;
    END
  END b_par[222]
  PIN b_par[223]
    DIRECTION INPUT ;
    USE SIGNAL ;
    PORT
      LAYER M3 ;
        RECT  131.112 0 131.13 0.038 ;
    END
  END b_par[223]
  PIN b_par[224]
    DIRECTION INPUT ;
    USE SIGNAL ;
    PORT
      LAYER M5 ;
        RECT  131.472 0 131.496 0.084 ;
    END
  END b_par[224]
  PIN b_par[225]
    DIRECTION INPUT ;
    USE SIGNAL ;
    PORT
      LAYER M3 ;
        RECT  131.904 0 131.922 0.038 ;
    END
  END b_par[225]
  PIN b_par[226]
    DIRECTION INPUT ;
    USE SIGNAL ;
    PORT
      LAYER M5 ;
        RECT  132.24 0 132.264 0.084 ;
    END
  END b_par[226]
  PIN b_par[227]
    DIRECTION INPUT ;
    USE SIGNAL ;
    PORT
      LAYER M3 ;
        RECT  132.552 0 132.57 0.038 ;
    END
  END b_par[227]
  PIN b_par[228]
    DIRECTION INPUT ;
    USE SIGNAL ;
    PORT
      LAYER M5 ;
        RECT  133.008 0 133.032 0.084 ;
    END
  END b_par[228]
  PIN b_par[229]
    DIRECTION INPUT ;
    USE SIGNAL ;
    PORT
      LAYER M3 ;
        RECT  133.344 0 133.362 0.038 ;
    END
    PORT
      LAYER M3 ;
        RECT  133.344 0.012 133.362 1.723 ;
    END
  END b_par[229]
  PIN b_par[22]
    DIRECTION INPUT ;
    USE SIGNAL ;
    PORT
      LAYER M5 ;
        RECT  89.904 0 89.928 0.084 ;
    END
  END b_par[22]
  PIN b_par[230]
    DIRECTION INPUT ;
    USE SIGNAL ;
    PORT
      LAYER M5 ;
        RECT  133.68 0 133.704 0.084 ;
    END
  END b_par[230]
  PIN b_par[231]
    DIRECTION INPUT ;
    USE SIGNAL ;
    PORT
      LAYER M3 ;
        RECT  134.1 0 134.118 0.038 ;
    END
    PORT
      LAYER M3 ;
        RECT  134.1 0.012 134.118 1.723 ;
    END
  END b_par[231]
  PIN b_par[232]
    DIRECTION INPUT ;
    USE SIGNAL ;
    PORT
      LAYER M5 ;
        RECT  134.448 0 134.472 0.084 ;
    END
  END b_par[232]
  PIN b_par[233]
    DIRECTION INPUT ;
    USE SIGNAL ;
    PORT
      LAYER M3 ;
        RECT  134.856 0 134.874 0.038 ;
    END
  END b_par[233]
  PIN b_par[234]
    DIRECTION INPUT ;
    USE SIGNAL ;
    PORT
      LAYER M5 ;
        RECT  135.216 0 135.24 0.084 ;
    END
  END b_par[234]
  PIN b_par[235]
    DIRECTION INPUT ;
    USE SIGNAL ;
    PORT
      LAYER M3 ;
        RECT  135.54 0 135.558 0.038 ;
    END
  END b_par[235]
  PIN b_par[236]
    DIRECTION INPUT ;
    USE SIGNAL ;
    PORT
      LAYER M5 ;
        RECT  135.984 0 136.008 0.084 ;
    END
  END b_par[236]
  PIN b_par[237]
    DIRECTION INPUT ;
    USE SIGNAL ;
    PORT
      LAYER M3 ;
        RECT  136.296 0 136.314 0.038 ;
    END
    PORT
      LAYER M3 ;
        RECT  136.296 0.012 136.314 1.723 ;
    END
  END b_par[237]
  PIN b_par[238]
    DIRECTION INPUT ;
    USE SIGNAL ;
    PORT
      LAYER M5 ;
        RECT  136.656 0 136.68 0.084 ;
    END
  END b_par[238]
  PIN b_par[239]
    DIRECTION INPUT ;
    USE SIGNAL ;
    PORT
      LAYER M3 ;
        RECT  137.088 0 137.106 0.038 ;
    END
    PORT
      LAYER M3 ;
        RECT  137.088 0.012 137.106 1.723 ;
    END
  END b_par[239]
  PIN b_par[23]
    DIRECTION INPUT ;
    USE SIGNAL ;
    PORT
      LAYER M3 ;
        RECT  90.144 0 90.162 0.038 ;
    END
  END b_par[23]
  PIN b_par[240]
    DIRECTION INPUT ;
    USE SIGNAL ;
    PORT
      LAYER M5 ;
        RECT  137.424 0 137.448 0.084 ;
    END
  END b_par[240]
  PIN b_par[241]
    DIRECTION INPUT ;
    USE SIGNAL ;
    PORT
      LAYER M3 ;
        RECT  137.844 0 137.862 0.038 ;
    END
  END b_par[241]
  PIN b_par[242]
    DIRECTION INPUT ;
    USE SIGNAL ;
    PORT
      LAYER M5 ;
        RECT  138.192 0 138.216 0.084 ;
    END
  END b_par[242]
  PIN b_par[243]
    DIRECTION INPUT ;
    USE SIGNAL ;
    PORT
      LAYER M3 ;
        RECT  138.528 0 138.546 0.038 ;
    END
  END b_par[243]
  PIN b_par[244]
    DIRECTION INPUT ;
    USE SIGNAL ;
    PORT
      LAYER M5 ;
        RECT  138.96 0 138.984 0.084 ;
    END
  END b_par[244]
  PIN b_par[245]
    DIRECTION INPUT ;
    USE SIGNAL ;
    PORT
      LAYER M3 ;
        RECT  139.284 0 139.302 0.038 ;
    END
    PORT
      LAYER M3 ;
        RECT  139.284 0.012 139.302 1.723 ;
    END
  END b_par[245]
  PIN b_par[246]
    DIRECTION INPUT ;
    USE SIGNAL ;
    PORT
      LAYER M5 ;
        RECT  139.632 0 139.656 0.084 ;
    END
  END b_par[246]
  PIN b_par[247]
    DIRECTION INPUT ;
    USE SIGNAL ;
    PORT
      LAYER M3 ;
        RECT  140.04 0 140.058 0.038 ;
    END
    PORT
      LAYER M3 ;
        RECT  140.04 0.012 140.058 1.723 ;
    END
  END b_par[247]
  PIN b_par[248]
    DIRECTION INPUT ;
    USE SIGNAL ;
    PORT
      LAYER M5 ;
        RECT  140.4 0 140.424 0.084 ;
    END
  END b_par[248]
  PIN b_par[249]
    DIRECTION INPUT ;
    USE SIGNAL ;
    PORT
      LAYER M3 ;
        RECT  140.832 0 140.85 0.038 ;
    END
  END b_par[249]
  PIN b_par[24]
    DIRECTION INPUT ;
    USE SIGNAL ;
    PORT
      LAYER M5 ;
        RECT  90.384 0 90.408 0.084 ;
    END
  END b_par[24]
  PIN b_par[250]
    DIRECTION INPUT ;
    USE SIGNAL ;
    PORT
      LAYER M5 ;
        RECT  141.168 0 141.192 0.084 ;
    END
  END b_par[250]
  PIN b_par[251]
    DIRECTION INPUT ;
    USE SIGNAL ;
    PORT
      LAYER M3 ;
        RECT  141.48 0 141.498 0.038 ;
    END
  END b_par[251]
  PIN b_par[252]
    DIRECTION INPUT ;
    USE SIGNAL ;
    PORT
      LAYER M5 ;
        RECT  141.936 0 141.96 0.084 ;
    END
  END b_par[252]
  PIN b_par[253]
    DIRECTION INPUT ;
    USE SIGNAL ;
    PORT
      LAYER M3 ;
        RECT  142.272 0 142.29 0.038 ;
    END
    PORT
      LAYER M3 ;
        RECT  142.272 0.012 142.29 0.523 ;
    END
  END b_par[253]
  PIN b_par[254]
    DIRECTION INPUT ;
    USE SIGNAL ;
    PORT
      LAYER M5 ;
        RECT  142.704 0 142.728 0.084 ;
    END
  END b_par[254]
  PIN b_par[255]
    DIRECTION INPUT ;
    USE SIGNAL ;
    PORT
      LAYER M3 ;
        RECT  143.028 0 143.046 0.038 ;
    END
    PORT
      LAYER M3 ;
        RECT  143.028 0.012 143.046 0.523 ;
    END
  END b_par[255]
  PIN b_par[25]
    DIRECTION INPUT ;
    USE SIGNAL ;
    PORT
      LAYER M3 ;
        RECT  90.504 0 90.522 0.038 ;
    END
  END b_par[25]
  PIN b_par[26]
    DIRECTION INPUT ;
    USE SIGNAL ;
    PORT
      LAYER M5 ;
        RECT  90.768 0 90.792 0.084 ;
    END
  END b_par[26]
  PIN b_par[27]
    DIRECTION INPUT ;
    USE SIGNAL ;
    PORT
      LAYER M3 ;
        RECT  90.9 0 90.918 0.038 ;
    END
  END b_par[27]
  PIN b_par[28]
    DIRECTION INPUT ;
    USE SIGNAL ;
    PORT
      LAYER M5 ;
        RECT  91.152 0 91.176 0.084 ;
    END
  END b_par[28]
  PIN b_par[29]
    DIRECTION INPUT ;
    USE SIGNAL ;
    PORT
      LAYER M3 ;
        RECT  91.368 0 91.386 0.038 ;
    END
  END b_par[29]
  PIN b_par[2]
    DIRECTION INPUT ;
    USE SIGNAL ;
    PORT
      LAYER M5 ;
        RECT  85.872 0 85.896 0.084 ;
    END
  END b_par[2]
  PIN b_par[30]
    DIRECTION INPUT ;
    USE SIGNAL ;
    PORT
      LAYER M5 ;
        RECT  91.536 0 91.56 0.084 ;
    END
  END b_par[30]
  PIN b_par[31]
    DIRECTION INPUT ;
    USE SIGNAL ;
    PORT
      LAYER M3 ;
        RECT  91.764 0 91.782 0.038 ;
    END
  END b_par[31]
  PIN b_par[32]
    DIRECTION INPUT ;
    USE SIGNAL ;
    PORT
      LAYER M5 ;
        RECT  92.016 0 92.04 0.084 ;
    END
  END b_par[32]
  PIN b_par[33]
    DIRECTION INPUT ;
    USE SIGNAL ;
    PORT
      LAYER M3 ;
        RECT  92.16 0 92.178 0.038 ;
    END
  END b_par[33]
  PIN b_par[34]
    DIRECTION INPUT ;
    USE SIGNAL ;
    PORT
      LAYER M5 ;
        RECT  92.4 0 92.424 0.084 ;
    END
  END b_par[34]
  PIN b_par[35]
    DIRECTION INPUT ;
    USE SIGNAL ;
    PORT
      LAYER M3 ;
        RECT  92.52 0 92.538 0.038 ;
    END
  END b_par[35]
  PIN b_par[36]
    DIRECTION INPUT ;
    USE SIGNAL ;
    PORT
      LAYER M5 ;
        RECT  92.784 0 92.808 0.084 ;
    END
  END b_par[36]
  PIN b_par[37]
    DIRECTION INPUT ;
    USE SIGNAL ;
    PORT
      LAYER M3 ;
        RECT  93.024 0 93.042 0.038 ;
    END
  END b_par[37]
  PIN b_par[38]
    DIRECTION INPUT ;
    USE SIGNAL ;
    PORT
      LAYER M5 ;
        RECT  93.168 0 93.192 0.084 ;
    END
  END b_par[38]
  PIN b_par[39]
    DIRECTION INPUT ;
    USE SIGNAL ;
    PORT
      LAYER M3 ;
        RECT  93.384 0 93.402 0.038 ;
    END
  END b_par[39]
  PIN b_par[3]
    DIRECTION INPUT ;
    USE SIGNAL ;
    PORT
      LAYER M3 ;
        RECT  86.004 0 86.022 0.038 ;
    END
  END b_par[3]
  PIN b_par[40]
    DIRECTION INPUT ;
    USE SIGNAL ;
    PORT
      LAYER M5 ;
        RECT  93.648 0 93.672 0.084 ;
    END
  END b_par[40]
  PIN b_par[41]
    DIRECTION INPUT ;
    USE SIGNAL ;
    PORT
      LAYER M3 ;
        RECT  93.78 0 93.798 0.038 ;
    END
  END b_par[41]
  PIN b_par[42]
    DIRECTION INPUT ;
    USE SIGNAL ;
    PORT
      LAYER M5 ;
        RECT  94.032 0 94.056 0.084 ;
    END
  END b_par[42]
  PIN b_par[43]
    DIRECTION INPUT ;
    USE SIGNAL ;
    PORT
      LAYER M3 ;
        RECT  94.248 0 94.266 0.038 ;
    END
  END b_par[43]
  PIN b_par[44]
    DIRECTION INPUT ;
    USE SIGNAL ;
    PORT
      LAYER M5 ;
        RECT  94.416 0 94.44 0.084 ;
    END
  END b_par[44]
  PIN b_par[45]
    DIRECTION INPUT ;
    USE SIGNAL ;
    PORT
      LAYER M3 ;
        RECT  94.644 0 94.662 0.038 ;
    END
  END b_par[45]
  PIN b_par[46]
    DIRECTION INPUT ;
    USE SIGNAL ;
    PORT
      LAYER M5 ;
        RECT  94.8 0 94.824 0.084 ;
    END
  END b_par[46]
  PIN b_par[47]
    DIRECTION INPUT ;
    USE SIGNAL ;
    PORT
      LAYER M3 ;
        RECT  95.04 0 95.058 0.038 ;
    END
  END b_par[47]
  PIN b_par[48]
    DIRECTION INPUT ;
    USE SIGNAL ;
    PORT
      LAYER M5 ;
        RECT  95.28 0 95.304 0.084 ;
    END
  END b_par[48]
  PIN b_par[49]
    DIRECTION INPUT ;
    USE SIGNAL ;
    PORT
      LAYER M3 ;
        RECT  95.4 0 95.418 0.038 ;
    END
  END b_par[49]
  PIN b_par[4]
    DIRECTION INPUT ;
    USE SIGNAL ;
    PORT
      LAYER M5 ;
        RECT  86.256 0 86.28 0.084 ;
    END
  END b_par[4]
  PIN b_par[50]
    DIRECTION INPUT ;
    USE SIGNAL ;
    PORT
      LAYER M5 ;
        RECT  95.664 0 95.688 0.084 ;
    END
  END b_par[50]
  PIN b_par[51]
    DIRECTION INPUT ;
    USE SIGNAL ;
    PORT
      LAYER M3 ;
        RECT  95.904 0 95.922 0.038 ;
    END
  END b_par[51]
  PIN b_par[52]
    DIRECTION INPUT ;
    USE SIGNAL ;
    PORT
      LAYER M5 ;
        RECT  96.048 0 96.072 0.084 ;
    END
  END b_par[52]
  PIN b_par[53]
    DIRECTION INPUT ;
    USE SIGNAL ;
    PORT
      LAYER M3 ;
        RECT  96.264 0 96.282 0.038 ;
    END
  END b_par[53]
  PIN b_par[54]
    DIRECTION INPUT ;
    USE SIGNAL ;
    PORT
      LAYER M5 ;
        RECT  96.528 0 96.552 0.084 ;
    END
  END b_par[54]
  PIN b_par[55]
    DIRECTION INPUT ;
    USE SIGNAL ;
    PORT
      LAYER M3 ;
        RECT  96.66 0 96.678 0.038 ;
    END
  END b_par[55]
  PIN b_par[56]
    DIRECTION INPUT ;
    USE SIGNAL ;
    PORT
      LAYER M5 ;
        RECT  96.912 0 96.936 0.084 ;
    END
  END b_par[56]
  PIN b_par[57]
    DIRECTION INPUT ;
    USE SIGNAL ;
    PORT
      LAYER M3 ;
        RECT  97.056 0 97.074 0.038 ;
    END
  END b_par[57]
  PIN b_par[58]
    DIRECTION INPUT ;
    USE SIGNAL ;
    PORT
      LAYER M5 ;
        RECT  97.296 0 97.32 0.084 ;
    END
  END b_par[58]
  PIN b_par[59]
    DIRECTION INPUT ;
    USE SIGNAL ;
    PORT
      LAYER M3 ;
        RECT  97.524 0 97.542 0.038 ;
    END
  END b_par[59]
  PIN b_par[5]
    DIRECTION INPUT ;
    USE SIGNAL ;
    PORT
      LAYER M3 ;
        RECT  86.472 0 86.49 0.038 ;
    END
  END b_par[5]
  PIN b_par[60]
    DIRECTION INPUT ;
    USE SIGNAL ;
    PORT
      LAYER M5 ;
        RECT  97.68 0 97.704 0.084 ;
    END
  END b_par[60]
  PIN b_par[61]
    DIRECTION INPUT ;
    USE SIGNAL ;
    PORT
      LAYER M3 ;
        RECT  97.92 0 97.938 0.038 ;
    END
  END b_par[61]
  PIN b_par[62]
    DIRECTION INPUT ;
    USE SIGNAL ;
    PORT
      LAYER M5 ;
        RECT  98.16 0 98.184 0.084 ;
    END
  END b_par[62]
  PIN b_par[63]
    DIRECTION INPUT ;
    USE SIGNAL ;
    PORT
      LAYER M3 ;
        RECT  98.28 0 98.298 0.038 ;
    END
  END b_par[63]
  PIN b_par[64]
    DIRECTION INPUT ;
    USE SIGNAL ;
    PORT
      LAYER M5 ;
        RECT  98.544 0 98.568 0.084 ;
    END
  END b_par[64]
  PIN b_par[65]
    DIRECTION INPUT ;
    USE SIGNAL ;
    PORT
      LAYER M3 ;
        RECT  98.676 0 98.694 0.038 ;
    END
  END b_par[65]
  PIN b_par[66]
    DIRECTION INPUT ;
    USE SIGNAL ;
    PORT
      LAYER M5 ;
        RECT  98.928 0 98.952 0.084 ;
    END
  END b_par[66]
  PIN b_par[67]
    DIRECTION INPUT ;
    USE SIGNAL ;
    PORT
      LAYER M3 ;
        RECT  99.144 0 99.162 0.038 ;
    END
  END b_par[67]
  PIN b_par[68]
    DIRECTION INPUT ;
    USE SIGNAL ;
    PORT
      LAYER M5 ;
        RECT  99.312 0 99.336 0.084 ;
    END
  END b_par[68]
  PIN b_par[69]
    DIRECTION INPUT ;
    USE SIGNAL ;
    PORT
      LAYER M3 ;
        RECT  99.54 0 99.558 0.038 ;
    END
  END b_par[69]
  PIN b_par[6]
    DIRECTION INPUT ;
    USE SIGNAL ;
    PORT
      LAYER M5 ;
        RECT  86.64 0 86.664 0.084 ;
    END
  END b_par[6]
  PIN b_par[70]
    DIRECTION INPUT ;
    USE SIGNAL ;
    PORT
      LAYER M5 ;
        RECT  99.792 0 99.816 0.084 ;
    END
  END b_par[70]
  PIN b_par[71]
    DIRECTION INPUT ;
    USE SIGNAL ;
    PORT
      LAYER M3 ;
        RECT  99.936 0 99.954 0.038 ;
    END
  END b_par[71]
  PIN b_par[72]
    DIRECTION INPUT ;
    USE SIGNAL ;
    PORT
      LAYER M5 ;
        RECT  100.176 0 100.2 0.084 ;
    END
  END b_par[72]
  PIN b_par[73]
    DIRECTION INPUT ;
    USE SIGNAL ;
    PORT
      LAYER M3 ;
        RECT  100.404 0 100.422 0.038 ;
    END
  END b_par[73]
  PIN b_par[74]
    DIRECTION INPUT ;
    USE SIGNAL ;
    PORT
      LAYER M5 ;
        RECT  100.56 0 100.584 0.084 ;
    END
  END b_par[74]
  PIN b_par[75]
    DIRECTION INPUT ;
    USE SIGNAL ;
    PORT
      LAYER M3 ;
        RECT  100.8 0 100.818 0.038 ;
    END
  END b_par[75]
  PIN b_par[76]
    DIRECTION INPUT ;
    USE SIGNAL ;
    PORT
      LAYER M5 ;
        RECT  100.944 0 100.968 0.084 ;
    END
  END b_par[76]
  PIN b_par[77]
    DIRECTION INPUT ;
    USE SIGNAL ;
    PORT
      LAYER M3 ;
        RECT  101.16 0 101.178 0.038 ;
    END
  END b_par[77]
  PIN b_par[78]
    DIRECTION INPUT ;
    USE SIGNAL ;
    PORT
      LAYER M5 ;
        RECT  101.424 0 101.448 0.084 ;
    END
  END b_par[78]
  PIN b_par[79]
    DIRECTION INPUT ;
    USE SIGNAL ;
    PORT
      LAYER M3 ;
        RECT  101.556 0 101.574 0.038 ;
    END
  END b_par[79]
  PIN b_par[7]
    DIRECTION INPUT ;
    USE SIGNAL ;
    PORT
      LAYER M3 ;
        RECT  86.868 0 86.886 0.038 ;
    END
  END b_par[7]
  PIN b_par[80]
    DIRECTION INPUT ;
    USE SIGNAL ;
    PORT
      LAYER M5 ;
        RECT  101.808 0 101.832 0.084 ;
    END
  END b_par[80]
  PIN b_par[81]
    DIRECTION INPUT ;
    USE SIGNAL ;
    PORT
      LAYER M3 ;
        RECT  102.024 0 102.042 0.038 ;
    END
  END b_par[81]
  PIN b_par[82]
    DIRECTION INPUT ;
    USE SIGNAL ;
    PORT
      LAYER M5 ;
        RECT  102.192 0 102.216 0.084 ;
    END
  END b_par[82]
  PIN b_par[83]
    DIRECTION INPUT ;
    USE SIGNAL ;
    PORT
      LAYER M3 ;
        RECT  102.42 0 102.438 0.038 ;
    END
  END b_par[83]
  PIN b_par[84]
    DIRECTION INPUT ;
    USE SIGNAL ;
    PORT
      LAYER M5 ;
        RECT  102.576 0 102.6 0.084 ;
    END
  END b_par[84]
  PIN b_par[85]
    DIRECTION INPUT ;
    USE SIGNAL ;
    PORT
      LAYER M3 ;
        RECT  102.816 0 102.834 0.038 ;
    END
  END b_par[85]
  PIN b_par[86]
    DIRECTION INPUT ;
    USE SIGNAL ;
    PORT
      LAYER M5 ;
        RECT  103.056 0 103.08 0.084 ;
    END
  END b_par[86]
  PIN b_par[87]
    DIRECTION INPUT ;
    USE SIGNAL ;
    PORT
      LAYER M3 ;
        RECT  103.176 0 103.194 0.038 ;
    END
  END b_par[87]
  PIN b_par[88]
    DIRECTION INPUT ;
    USE SIGNAL ;
    PORT
      LAYER M5 ;
        RECT  103.44 0 103.464 0.084 ;
    END
  END b_par[88]
  PIN b_par[89]
    DIRECTION INPUT ;
    USE SIGNAL ;
    PORT
      LAYER M3 ;
        RECT  103.68 0 103.698 0.038 ;
    END
  END b_par[89]
  PIN b_par[8]
    DIRECTION INPUT ;
    USE SIGNAL ;
    PORT
      LAYER M5 ;
        RECT  87.024 0 87.048 0.084 ;
    END
  END b_par[8]
  PIN b_par[90]
    DIRECTION INPUT ;
    USE SIGNAL ;
    PORT
      LAYER M5 ;
        RECT  103.824 0 103.848 0.084 ;
    END
  END b_par[90]
  PIN b_par[91]
    DIRECTION INPUT ;
    USE SIGNAL ;
    PORT
      LAYER M3 ;
        RECT  104.04 0 104.058 0.038 ;
    END
  END b_par[91]
  PIN b_par[92]
    DIRECTION INPUT ;
    USE SIGNAL ;
    PORT
      LAYER M5 ;
        RECT  104.304 0 104.328 0.084 ;
    END
  END b_par[92]
  PIN b_par[93]
    DIRECTION INPUT ;
    USE SIGNAL ;
    PORT
      LAYER M3 ;
        RECT  104.436 0 104.454 0.038 ;
    END
  END b_par[93]
  PIN b_par[94]
    DIRECTION INPUT ;
    USE SIGNAL ;
    PORT
      LAYER M5 ;
        RECT  104.688 0 104.712 0.084 ;
    END
  END b_par[94]
  PIN b_par[95]
    DIRECTION INPUT ;
    USE SIGNAL ;
    PORT
      LAYER M3 ;
        RECT  104.832 0 104.85 0.038 ;
    END
  END b_par[95]
  PIN b_par[96]
    DIRECTION INPUT ;
    USE SIGNAL ;
    PORT
      LAYER M5 ;
        RECT  105.072 0 105.096 0.084 ;
    END
  END b_par[96]
  PIN b_par[97]
    DIRECTION INPUT ;
    USE SIGNAL ;
    PORT
      LAYER M3 ;
        RECT  105.3 0 105.318 0.038 ;
    END
  END b_par[97]
  PIN b_par[98]
    DIRECTION INPUT ;
    USE SIGNAL ;
    PORT
      LAYER M5 ;
        RECT  105.456 0 105.48 0.084 ;
    END
  END b_par[98]
  PIN b_par[99]
    DIRECTION INPUT ;
    USE SIGNAL ;
    PORT
      LAYER M3 ;
        RECT  105.696 0 105.714 0.038 ;
    END
  END b_par[99]
  PIN b_par[9]
    DIRECTION INPUT ;
    USE SIGNAL ;
    PORT
      LAYER M3 ;
        RECT  87.264 0 87.282 0.038 ;
    END
  END b_par[9]
  PIN b_par_out[0]
    DIRECTION OUTPUT ;
    USE SIGNAL ;
    PORT
      LAYER M5 ;
        RECT  85.392 25.836 85.416 25.92 ;
    END
  END b_par_out[0]
  PIN b_par_out[100]
    DIRECTION OUTPUT ;
    USE SIGNAL ;
    PORT
      LAYER M5 ;
        RECT  105.936 25.836 105.96 25.92 ;
    END
  END b_par_out[100]
  PIN b_par_out[101]
    DIRECTION OUTPUT ;
    USE SIGNAL ;
    PORT
      LAYER M3 ;
        RECT  106.056 25.882 106.074 25.92 ;
    END
  END b_par_out[101]
  PIN b_par_out[102]
    DIRECTION OUTPUT ;
    USE SIGNAL ;
    PORT
      LAYER M5 ;
        RECT  106.32 25.836 106.344 25.92 ;
    END
  END b_par_out[102]
  PIN b_par_out[103]
    DIRECTION OUTPUT ;
    USE SIGNAL ;
    PORT
      LAYER M3 ;
        RECT  106.56 25.882 106.578 25.92 ;
    END
  END b_par_out[103]
  PIN b_par_out[104]
    DIRECTION OUTPUT ;
    USE SIGNAL ;
    PORT
      LAYER M5 ;
        RECT  106.704 25.836 106.728 25.92 ;
    END
  END b_par_out[104]
  PIN b_par_out[105]
    DIRECTION OUTPUT ;
    USE SIGNAL ;
    PORT
      LAYER M3 ;
        RECT  106.92 25.882 106.938 25.92 ;
    END
  END b_par_out[105]
  PIN b_par_out[106]
    DIRECTION OUTPUT ;
    USE SIGNAL ;
    PORT
      LAYER M5 ;
        RECT  107.088 25.836 107.112 25.92 ;
    END
  END b_par_out[106]
  PIN b_par_out[107]
    DIRECTION OUTPUT ;
    USE SIGNAL ;
    PORT
      LAYER M3 ;
        RECT  107.316 25.882 107.334 25.92 ;
    END
  END b_par_out[107]
  PIN b_par_out[108]
    DIRECTION OUTPUT ;
    USE SIGNAL ;
    PORT
      LAYER M5 ;
        RECT  107.568 25.836 107.592 25.92 ;
    END
  END b_par_out[108]
  PIN b_par_out[109]
    DIRECTION OUTPUT ;
    USE SIGNAL ;
    PORT
      LAYER M3 ;
        RECT  107.712 25.882 107.73 25.92 ;
    END
  END b_par_out[109]
  PIN b_par_out[10]
    DIRECTION OUTPUT ;
    USE SIGNAL ;
    PORT
      LAYER M5 ;
        RECT  87.504 25.836 87.528 25.92 ;
    END
  END b_par_out[10]
  PIN b_par_out[110]
    DIRECTION OUTPUT ;
    USE SIGNAL ;
    PORT
      LAYER M5 ;
        RECT  107.952 25.836 107.976 25.92 ;
    END
  END b_par_out[110]
  PIN b_par_out[111]
    DIRECTION OUTPUT ;
    USE SIGNAL ;
    PORT
      LAYER M3 ;
        RECT  108.18 25.882 108.198 25.92 ;
    END
  END b_par_out[111]
  PIN b_par_out[112]
    DIRECTION OUTPUT ;
    USE SIGNAL ;
    PORT
      LAYER M5 ;
        RECT  108.336 25.836 108.36 25.92 ;
    END
  END b_par_out[112]
  PIN b_par_out[113]
    DIRECTION OUTPUT ;
    USE SIGNAL ;
    PORT
      LAYER M3 ;
        RECT  108.576 25.882 108.594 25.92 ;
    END
  END b_par_out[113]
  PIN b_par_out[114]
    DIRECTION OUTPUT ;
    USE SIGNAL ;
    PORT
      LAYER M5 ;
        RECT  108.72 25.836 108.744 25.92 ;
    END
  END b_par_out[114]
  PIN b_par_out[115]
    DIRECTION OUTPUT ;
    USE SIGNAL ;
    PORT
      LAYER M3 ;
        RECT  108.936 25.882 108.954 25.92 ;
    END
  END b_par_out[115]
  PIN b_par_out[116]
    DIRECTION OUTPUT ;
    USE SIGNAL ;
    PORT
      LAYER M5 ;
        RECT  109.2 25.836 109.224 25.92 ;
    END
  END b_par_out[116]
  PIN b_par_out[117]
    DIRECTION OUTPUT ;
    USE SIGNAL ;
    PORT
      LAYER M3 ;
        RECT  109.332 25.882 109.35 25.92 ;
    END
  END b_par_out[117]
  PIN b_par_out[118]
    DIRECTION OUTPUT ;
    USE SIGNAL ;
    PORT
      LAYER M5 ;
        RECT  109.584 25.836 109.608 25.92 ;
    END
  END b_par_out[118]
  PIN b_par_out[119]
    DIRECTION OUTPUT ;
    USE SIGNAL ;
    PORT
      LAYER M3 ;
        RECT  109.8 25.882 109.818 25.92 ;
    END
  END b_par_out[119]
  PIN b_par_out[11]
    DIRECTION OUTPUT ;
    USE SIGNAL ;
    PORT
      LAYER M3 ;
        RECT  87.624 25.882 87.642 25.92 ;
    END
  END b_par_out[11]
  PIN b_par_out[120]
    DIRECTION OUTPUT ;
    USE SIGNAL ;
    PORT
      LAYER M5 ;
        RECT  109.968 25.836 109.992 25.92 ;
    END
  END b_par_out[120]
  PIN b_par_out[121]
    DIRECTION OUTPUT ;
    USE SIGNAL ;
    PORT
      LAYER M3 ;
        RECT  110.196 25.882 110.214 25.92 ;
    END
  END b_par_out[121]
  PIN b_par_out[122]
    DIRECTION OUTPUT ;
    USE SIGNAL ;
    PORT
      LAYER M5 ;
        RECT  110.448 25.836 110.472 25.92 ;
    END
  END b_par_out[122]
  PIN b_par_out[123]
    DIRECTION OUTPUT ;
    USE SIGNAL ;
    PORT
      LAYER M3 ;
        RECT  110.592 25.882 110.61 25.92 ;
    END
  END b_par_out[123]
  PIN b_par_out[124]
    DIRECTION OUTPUT ;
    USE SIGNAL ;
    PORT
      LAYER M5 ;
        RECT  110.832 25.836 110.856 25.92 ;
    END
  END b_par_out[124]
  PIN b_par_out[125]
    DIRECTION OUTPUT ;
    USE SIGNAL ;
    PORT
      LAYER M3 ;
        RECT  110.952 25.882 110.97 25.92 ;
    END
  END b_par_out[125]
  PIN b_par_out[126]
    DIRECTION OUTPUT ;
    USE SIGNAL ;
    PORT
      LAYER M5 ;
        RECT  111.216 25.836 111.24 25.92 ;
    END
  END b_par_out[126]
  PIN b_par_out[127]
    DIRECTION OUTPUT ;
    USE SIGNAL ;
    PORT
      LAYER M3 ;
        RECT  111.456 25.882 111.474 25.92 ;
    END
  END b_par_out[127]
  PIN b_par_out[128]
    DIRECTION OUTPUT ;
    USE SIGNAL ;
    PORT
      LAYER M5 ;
        RECT  111.6 25.836 111.624 25.92 ;
    END
  END b_par_out[128]
  PIN b_par_out[129]
    DIRECTION OUTPUT ;
    USE SIGNAL ;
    PORT
      LAYER M3 ;
        RECT  111.816 25.882 111.834 25.92 ;
    END
  END b_par_out[129]
  PIN b_par_out[12]
    DIRECTION OUTPUT ;
    USE SIGNAL ;
    PORT
      LAYER M5 ;
        RECT  87.888 25.836 87.912 25.92 ;
    END
  END b_par_out[12]
  PIN b_par_out[130]
    DIRECTION OUTPUT ;
    USE SIGNAL ;
    PORT
      LAYER M5 ;
        RECT  112.08 25.836 112.104 25.92 ;
    END
  END b_par_out[130]
  PIN b_par_out[131]
    DIRECTION OUTPUT ;
    USE SIGNAL ;
    PORT
      LAYER M3 ;
        RECT  112.212 25.882 112.23 25.92 ;
    END
  END b_par_out[131]
  PIN b_par_out[132]
    DIRECTION OUTPUT ;
    USE SIGNAL ;
    PORT
      LAYER M5 ;
        RECT  112.464 25.836 112.488 25.92 ;
    END
  END b_par_out[132]
  PIN b_par_out[133]
    DIRECTION OUTPUT ;
    USE SIGNAL ;
    PORT
      LAYER M3 ;
        RECT  112.608 25.882 112.626 25.92 ;
    END
  END b_par_out[133]
  PIN b_par_out[134]
    DIRECTION OUTPUT ;
    USE SIGNAL ;
    PORT
      LAYER M5 ;
        RECT  112.848 25.836 112.872 25.92 ;
    END
  END b_par_out[134]
  PIN b_par_out[135]
    DIRECTION OUTPUT ;
    USE SIGNAL ;
    PORT
      LAYER M3 ;
        RECT  113.076 25.882 113.094 25.92 ;
    END
  END b_par_out[135]
  PIN b_par_out[136]
    DIRECTION OUTPUT ;
    USE SIGNAL ;
    PORT
      LAYER M5 ;
        RECT  113.232 25.836 113.256 25.92 ;
    END
  END b_par_out[136]
  PIN b_par_out[137]
    DIRECTION OUTPUT ;
    USE SIGNAL ;
    PORT
      LAYER M3 ;
        RECT  113.472 25.882 113.49 25.92 ;
    END
  END b_par_out[137]
  PIN b_par_out[138]
    DIRECTION OUTPUT ;
    USE SIGNAL ;
    PORT
      LAYER M5 ;
        RECT  113.712 25.836 113.736 25.92 ;
    END
  END b_par_out[138]
  PIN b_par_out[139]
    DIRECTION OUTPUT ;
    USE SIGNAL ;
    PORT
      LAYER M3 ;
        RECT  113.832 25.882 113.85 25.92 ;
    END
  END b_par_out[139]
  PIN b_par_out[13]
    DIRECTION OUTPUT ;
    USE SIGNAL ;
    PORT
      LAYER M3 ;
        RECT  88.128 25.882 88.146 25.92 ;
    END
  END b_par_out[13]
  PIN b_par_out[140]
    DIRECTION OUTPUT ;
    USE SIGNAL ;
    PORT
      LAYER M5 ;
        RECT  114.096 25.836 114.12 25.92 ;
    END
  END b_par_out[140]
  PIN b_par_out[141]
    DIRECTION OUTPUT ;
    USE SIGNAL ;
    PORT
      LAYER M3 ;
        RECT  114.336 25.882 114.354 25.92 ;
    END
  END b_par_out[141]
  PIN b_par_out[142]
    DIRECTION OUTPUT ;
    USE SIGNAL ;
    PORT
      LAYER M5 ;
        RECT  114.48 25.836 114.504 25.92 ;
    END
  END b_par_out[142]
  PIN b_par_out[143]
    DIRECTION OUTPUT ;
    USE SIGNAL ;
    PORT
      LAYER M3 ;
        RECT  114.696 25.882 114.714 25.92 ;
    END
  END b_par_out[143]
  PIN b_par_out[144]
    DIRECTION OUTPUT ;
    USE SIGNAL ;
    PORT
      LAYER M5 ;
        RECT  114.864 25.836 114.888 25.92 ;
    END
  END b_par_out[144]
  PIN b_par_out[145]
    DIRECTION OUTPUT ;
    USE SIGNAL ;
    PORT
      LAYER M3 ;
        RECT  115.092 25.882 115.11 25.92 ;
    END
  END b_par_out[145]
  PIN b_par_out[146]
    DIRECTION OUTPUT ;
    USE SIGNAL ;
    PORT
      LAYER M5 ;
        RECT  115.344 25.836 115.368 25.92 ;
    END
  END b_par_out[146]
  PIN b_par_out[147]
    DIRECTION OUTPUT ;
    USE SIGNAL ;
    PORT
      LAYER M3 ;
        RECT  115.488 25.882 115.506 25.92 ;
    END
  END b_par_out[147]
  PIN b_par_out[148]
    DIRECTION OUTPUT ;
    USE SIGNAL ;
    PORT
      LAYER M5 ;
        RECT  115.728 25.836 115.752 25.92 ;
    END
  END b_par_out[148]
  PIN b_par_out[149]
    DIRECTION OUTPUT ;
    USE SIGNAL ;
    PORT
      LAYER M3 ;
        RECT  115.956 25.882 115.974 25.92 ;
    END
  END b_par_out[149]
  PIN b_par_out[14]
    DIRECTION OUTPUT ;
    USE SIGNAL ;
    PORT
      LAYER M5 ;
        RECT  88.272 25.836 88.296 25.92 ;
    END
  END b_par_out[14]
  PIN b_par_out[150]
    DIRECTION OUTPUT ;
    USE SIGNAL ;
    PORT
      LAYER M5 ;
        RECT  116.112 25.836 116.136 25.92 ;
    END
  END b_par_out[150]
  PIN b_par_out[151]
    DIRECTION OUTPUT ;
    USE SIGNAL ;
    PORT
      LAYER M3 ;
        RECT  116.352 25.882 116.37 25.92 ;
    END
  END b_par_out[151]
  PIN b_par_out[152]
    DIRECTION OUTPUT ;
    USE SIGNAL ;
    PORT
      LAYER M5 ;
        RECT  116.592 25.836 116.616 25.92 ;
    END
  END b_par_out[152]
  PIN b_par_out[153]
    DIRECTION OUTPUT ;
    USE SIGNAL ;
    PORT
      LAYER M3 ;
        RECT  116.712 25.882 116.73 25.92 ;
    END
  END b_par_out[153]
  PIN b_par_out[154]
    DIRECTION OUTPUT ;
    USE SIGNAL ;
    PORT
      LAYER M5 ;
        RECT  116.976 25.836 117 25.92 ;
    END
  END b_par_out[154]
  PIN b_par_out[155]
    DIRECTION OUTPUT ;
    USE SIGNAL ;
    PORT
      LAYER M3 ;
        RECT  117.108 25.882 117.126 25.92 ;
    END
  END b_par_out[155]
  PIN b_par_out[156]
    DIRECTION OUTPUT ;
    USE SIGNAL ;
    PORT
      LAYER M5 ;
        RECT  117.36 25.836 117.384 25.92 ;
    END
  END b_par_out[156]
  PIN b_par_out[157]
    DIRECTION OUTPUT ;
    USE SIGNAL ;
    PORT
      LAYER M3 ;
        RECT  117.576 25.882 117.594 25.92 ;
    END
  END b_par_out[157]
  PIN b_par_out[158]
    DIRECTION OUTPUT ;
    USE SIGNAL ;
    PORT
      LAYER M5 ;
        RECT  117.744 25.836 117.768 25.92 ;
    END
  END b_par_out[158]
  PIN b_par_out[159]
    DIRECTION OUTPUT ;
    USE SIGNAL ;
    PORT
      LAYER M3 ;
        RECT  117.972 25.882 117.99 25.92 ;
    END
  END b_par_out[159]
  PIN b_par_out[15]
    DIRECTION OUTPUT ;
    USE SIGNAL ;
    PORT
      LAYER M3 ;
        RECT  88.488 25.882 88.506 25.92 ;
    END
  END b_par_out[15]
  PIN b_par_out[160]
    DIRECTION OUTPUT ;
    USE SIGNAL ;
    PORT
      LAYER M5 ;
        RECT  118.224 25.836 118.248 25.92 ;
    END
  END b_par_out[160]
  PIN b_par_out[161]
    DIRECTION OUTPUT ;
    USE SIGNAL ;
    PORT
      LAYER M3 ;
        RECT  118.368 25.882 118.386 25.92 ;
    END
  END b_par_out[161]
  PIN b_par_out[162]
    DIRECTION OUTPUT ;
    USE SIGNAL ;
    PORT
      LAYER M5 ;
        RECT  118.608 25.836 118.632 25.92 ;
    END
  END b_par_out[162]
  PIN b_par_out[163]
    DIRECTION OUTPUT ;
    USE SIGNAL ;
    PORT
      LAYER M3 ;
        RECT  118.728 25.882 118.746 25.92 ;
    END
  END b_par_out[163]
  PIN b_par_out[164]
    DIRECTION OUTPUT ;
    USE SIGNAL ;
    PORT
      LAYER M5 ;
        RECT  118.992 25.836 119.016 25.92 ;
    END
  END b_par_out[164]
  PIN b_par_out[165]
    DIRECTION OUTPUT ;
    USE SIGNAL ;
    PORT
      LAYER M3 ;
        RECT  119.232 25.882 119.25 25.92 ;
    END
  END b_par_out[165]
  PIN b_par_out[166]
    DIRECTION OUTPUT ;
    USE SIGNAL ;
    PORT
      LAYER M5 ;
        RECT  119.376 25.836 119.4 25.92 ;
    END
  END b_par_out[166]
  PIN b_par_out[167]
    DIRECTION OUTPUT ;
    USE SIGNAL ;
    PORT
      LAYER M3 ;
        RECT  119.592 25.882 119.61 25.92 ;
    END
  END b_par_out[167]
  PIN b_par_out[168]
    DIRECTION OUTPUT ;
    USE SIGNAL ;
    PORT
      LAYER M5 ;
        RECT  119.856 25.836 119.88 25.92 ;
    END
  END b_par_out[168]
  PIN b_par_out[169]
    DIRECTION OUTPUT ;
    USE SIGNAL ;
    PORT
      LAYER M3 ;
        RECT  119.988 25.882 120.006 25.92 ;
    END
  END b_par_out[169]
  PIN b_par_out[16]
    DIRECTION OUTPUT ;
    USE SIGNAL ;
    PORT
      LAYER M5 ;
        RECT  88.656 25.836 88.68 25.92 ;
    END
  END b_par_out[16]
  PIN b_par_out[170]
    DIRECTION OUTPUT ;
    USE SIGNAL ;
    PORT
      LAYER M5 ;
        RECT  120.24 25.836 120.264 25.92 ;
    END
  END b_par_out[170]
  PIN b_par_out[171]
    DIRECTION OUTPUT ;
    USE SIGNAL ;
    PORT
      LAYER M3 ;
        RECT  120.456 25.882 120.474 25.92 ;
    END
  END b_par_out[171]
  PIN b_par_out[172]
    DIRECTION OUTPUT ;
    USE SIGNAL ;
    PORT
      LAYER M5 ;
        RECT  120.624 25.836 120.648 25.92 ;
    END
  END b_par_out[172]
  PIN b_par_out[173]
    DIRECTION OUTPUT ;
    USE SIGNAL ;
    PORT
      LAYER M3 ;
        RECT  120.852 25.882 120.87 25.92 ;
    END
  END b_par_out[173]
  PIN b_par_out[174]
    DIRECTION OUTPUT ;
    USE SIGNAL ;
    PORT
      LAYER M5 ;
        RECT  121.008 25.836 121.032 25.92 ;
    END
  END b_par_out[174]
  PIN b_par_out[175]
    DIRECTION OUTPUT ;
    USE SIGNAL ;
    PORT
      LAYER M3 ;
        RECT  121.248 25.882 121.266 25.92 ;
    END
  END b_par_out[175]
  PIN b_par_out[176]
    DIRECTION OUTPUT ;
    USE SIGNAL ;
    PORT
      LAYER M5 ;
        RECT  121.488 25.836 121.512 25.92 ;
    END
  END b_par_out[176]
  PIN b_par_out[177]
    DIRECTION OUTPUT ;
    USE SIGNAL ;
    PORT
      LAYER M3 ;
        RECT  121.608 25.882 121.626 25.92 ;
    END
  END b_par_out[177]
  PIN b_par_out[178]
    DIRECTION OUTPUT ;
    USE SIGNAL ;
    PORT
      LAYER M5 ;
        RECT  121.872 25.836 121.896 25.92 ;
    END
  END b_par_out[178]
  PIN b_par_out[179]
    DIRECTION OUTPUT ;
    USE SIGNAL ;
    PORT
      LAYER M3 ;
        RECT  122.112 25.882 122.13 25.92 ;
    END
  END b_par_out[179]
  PIN b_par_out[17]
    DIRECTION OUTPUT ;
    USE SIGNAL ;
    PORT
      LAYER M3 ;
        RECT  88.884 25.882 88.902 25.92 ;
    END
  END b_par_out[17]
  PIN b_par_out[180]
    DIRECTION OUTPUT ;
    USE SIGNAL ;
    PORT
      LAYER M5 ;
        RECT  122.256 25.836 122.28 25.92 ;
    END
  END b_par_out[180]
  PIN b_par_out[181]
    DIRECTION OUTPUT ;
    USE SIGNAL ;
    PORT
      LAYER M3 ;
        RECT  122.472 25.882 122.49 25.92 ;
    END
  END b_par_out[181]
  PIN b_par_out[182]
    DIRECTION OUTPUT ;
    USE SIGNAL ;
    PORT
      LAYER M5 ;
        RECT  122.64 25.836 122.664 25.92 ;
    END
  END b_par_out[182]
  PIN b_par_out[183]
    DIRECTION OUTPUT ;
    USE SIGNAL ;
    PORT
      LAYER M3 ;
        RECT  122.868 25.882 122.886 25.92 ;
    END
  END b_par_out[183]
  PIN b_par_out[184]
    DIRECTION OUTPUT ;
    USE SIGNAL ;
    PORT
      LAYER M5 ;
        RECT  123.12 25.836 123.144 25.92 ;
    END
  END b_par_out[184]
  PIN b_par_out[185]
    DIRECTION OUTPUT ;
    USE SIGNAL ;
    PORT
      LAYER M3 ;
        RECT  123.264 25.882 123.282 25.92 ;
    END
  END b_par_out[185]
  PIN b_par_out[186]
    DIRECTION OUTPUT ;
    USE SIGNAL ;
    PORT
      LAYER M5 ;
        RECT  123.504 25.836 123.528 25.92 ;
    END
  END b_par_out[186]
  PIN b_par_out[187]
    DIRECTION OUTPUT ;
    USE SIGNAL ;
    PORT
      LAYER M3 ;
        RECT  123.732 25.882 123.75 25.92 ;
    END
  END b_par_out[187]
  PIN b_par_out[188]
    DIRECTION OUTPUT ;
    USE SIGNAL ;
    PORT
      LAYER M5 ;
        RECT  123.888 25.836 123.912 25.92 ;
    END
  END b_par_out[188]
  PIN b_par_out[189]
    DIRECTION OUTPUT ;
    USE SIGNAL ;
    PORT
      LAYER M3 ;
        RECT  124.128 25.882 124.146 25.92 ;
    END
  END b_par_out[189]
  PIN b_par_out[18]
    DIRECTION OUTPUT ;
    USE SIGNAL ;
    PORT
      LAYER M5 ;
        RECT  89.136 25.836 89.16 25.92 ;
    END
  END b_par_out[18]
  PIN b_par_out[190]
    DIRECTION OUTPUT ;
    USE SIGNAL ;
    PORT
      LAYER M5 ;
        RECT  124.368 25.836 124.392 25.92 ;
    END
  END b_par_out[190]
  PIN b_par_out[191]
    DIRECTION OUTPUT ;
    USE SIGNAL ;
    PORT
      LAYER M3 ;
        RECT  124.488 25.882 124.506 25.92 ;
    END
  END b_par_out[191]
  PIN b_par_out[192]
    DIRECTION OUTPUT ;
    USE SIGNAL ;
    PORT
      LAYER M5 ;
        RECT  124.752 25.836 124.776 25.92 ;
    END
  END b_par_out[192]
  PIN b_par_out[193]
    DIRECTION OUTPUT ;
    USE SIGNAL ;
    PORT
      LAYER M3 ;
        RECT  124.884 25.882 124.902 25.92 ;
    END
  END b_par_out[193]
  PIN b_par_out[194]
    DIRECTION OUTPUT ;
    USE SIGNAL ;
    PORT
      LAYER M5 ;
        RECT  125.136 25.836 125.16 25.92 ;
    END
  END b_par_out[194]
  PIN b_par_out[195]
    DIRECTION OUTPUT ;
    USE SIGNAL ;
    PORT
      LAYER M3 ;
        RECT  125.352 25.882 125.37 25.92 ;
    END
  END b_par_out[195]
  PIN b_par_out[196]
    DIRECTION OUTPUT ;
    USE SIGNAL ;
    PORT
      LAYER M5 ;
        RECT  125.52 25.836 125.544 25.92 ;
    END
  END b_par_out[196]
  PIN b_par_out[197]
    DIRECTION OUTPUT ;
    USE SIGNAL ;
    PORT
      LAYER M3 ;
        RECT  125.748 25.882 125.766 25.92 ;
    END
  END b_par_out[197]
  PIN b_par_out[198]
    DIRECTION OUTPUT ;
    USE SIGNAL ;
    PORT
      LAYER M5 ;
        RECT  126 25.836 126.024 25.92 ;
    END
  END b_par_out[198]
  PIN b_par_out[199]
    DIRECTION OUTPUT ;
    USE SIGNAL ;
    PORT
      LAYER M3 ;
        RECT  126.144 25.882 126.162 25.92 ;
    END
  END b_par_out[199]
  PIN b_par_out[19]
    DIRECTION OUTPUT ;
    USE SIGNAL ;
    PORT
      LAYER M3 ;
        RECT  89.28 25.882 89.298 25.92 ;
    END
  END b_par_out[19]
  PIN b_par_out[1]
    DIRECTION OUTPUT ;
    USE SIGNAL ;
    PORT
      LAYER M3 ;
        RECT  85.608 25.882 85.626 25.92 ;
    END
  END b_par_out[1]
  PIN b_par_out[200]
    DIRECTION OUTPUT ;
    USE SIGNAL ;
    PORT
      LAYER M5 ;
        RECT  126.384 25.836 126.408 25.92 ;
    END
  END b_par_out[200]
  PIN b_par_out[201]
    DIRECTION OUTPUT ;
    USE SIGNAL ;
    PORT
      LAYER M3 ;
        RECT  126.612 25.882 126.63 25.92 ;
    END
  END b_par_out[201]
  PIN b_par_out[202]
    DIRECTION OUTPUT ;
    USE SIGNAL ;
    PORT
      LAYER M5 ;
        RECT  126.768 25.836 126.792 25.92 ;
    END
  END b_par_out[202]
  PIN b_par_out[203]
    DIRECTION OUTPUT ;
    USE SIGNAL ;
    PORT
      LAYER M3 ;
        RECT  127.008 25.882 127.026 25.92 ;
    END
  END b_par_out[203]
  PIN b_par_out[204]
    DIRECTION OUTPUT ;
    USE SIGNAL ;
    PORT
      LAYER M5 ;
        RECT  127.152 25.836 127.176 25.92 ;
    END
  END b_par_out[204]
  PIN b_par_out[205]
    DIRECTION OUTPUT ;
    USE SIGNAL ;
    PORT
      LAYER M3 ;
        RECT  127.368 25.882 127.386 25.92 ;
    END
  END b_par_out[205]
  PIN b_par_out[206]
    DIRECTION OUTPUT ;
    USE SIGNAL ;
    PORT
      LAYER M5 ;
        RECT  127.632 25.836 127.656 25.92 ;
    END
  END b_par_out[206]
  PIN b_par_out[207]
    DIRECTION OUTPUT ;
    USE SIGNAL ;
    PORT
      LAYER M3 ;
        RECT  127.764 25.882 127.782 25.92 ;
    END
  END b_par_out[207]
  PIN b_par_out[208]
    DIRECTION OUTPUT ;
    USE SIGNAL ;
    PORT
      LAYER M5 ;
        RECT  128.016 25.836 128.04 25.92 ;
    END
  END b_par_out[208]
  PIN b_par_out[209]
    DIRECTION OUTPUT ;
    USE SIGNAL ;
    PORT
      LAYER M3 ;
        RECT  128.232 25.882 128.25 25.92 ;
    END
  END b_par_out[209]
  PIN b_par_out[20]
    DIRECTION OUTPUT ;
    USE SIGNAL ;
    PORT
      LAYER M5 ;
        RECT  89.52 25.836 89.544 25.92 ;
    END
  END b_par_out[20]
  PIN b_par_out[210]
    DIRECTION OUTPUT ;
    USE SIGNAL ;
    PORT
      LAYER M5 ;
        RECT  128.4 25.836 128.424 25.92 ;
    END
  END b_par_out[210]
  PIN b_par_out[211]
    DIRECTION OUTPUT ;
    USE SIGNAL ;
    PORT
      LAYER M3 ;
        RECT  128.628 25.882 128.646 25.92 ;
    END
  END b_par_out[211]
  PIN b_par_out[212]
    DIRECTION OUTPUT ;
    USE SIGNAL ;
    PORT
      LAYER M5 ;
        RECT  128.784 25.836 128.808 25.92 ;
    END
  END b_par_out[212]
  PIN b_par_out[213]
    DIRECTION OUTPUT ;
    USE SIGNAL ;
    PORT
      LAYER M3 ;
        RECT  129.024 25.882 129.042 25.92 ;
    END
  END b_par_out[213]
  PIN b_par_out[214]
    DIRECTION OUTPUT ;
    USE SIGNAL ;
    PORT
      LAYER M5 ;
        RECT  129.264 25.836 129.288 25.92 ;
    END
  END b_par_out[214]
  PIN b_par_out[215]
    DIRECTION OUTPUT ;
    USE SIGNAL ;
    PORT
      LAYER M3 ;
        RECT  129.384 25.882 129.402 25.92 ;
    END
  END b_par_out[215]
  PIN b_par_out[216]
    DIRECTION OUTPUT ;
    USE SIGNAL ;
    PORT
      LAYER M5 ;
        RECT  129.648 25.836 129.672 25.92 ;
    END
  END b_par_out[216]
  PIN b_par_out[217]
    DIRECTION OUTPUT ;
    USE SIGNAL ;
    PORT
      LAYER M3 ;
        RECT  129.888 25.882 129.906 25.92 ;
    END
  END b_par_out[217]
  PIN b_par_out[218]
    DIRECTION OUTPUT ;
    USE SIGNAL ;
    PORT
      LAYER M5 ;
        RECT  130.032 25.836 130.056 25.92 ;
    END
  END b_par_out[218]
  PIN b_par_out[219]
    DIRECTION OUTPUT ;
    USE SIGNAL ;
    PORT
      LAYER M3 ;
        RECT  130.248 25.882 130.266 25.92 ;
    END
  END b_par_out[219]
  PIN b_par_out[21]
    DIRECTION OUTPUT ;
    USE SIGNAL ;
    PORT
      LAYER M3 ;
        RECT  89.748 25.882 89.766 25.92 ;
    END
  END b_par_out[21]
  PIN b_par_out[220]
    DIRECTION OUTPUT ;
    USE SIGNAL ;
    PORT
      LAYER M5 ;
        RECT  130.512 25.836 130.536 25.92 ;
    END
  END b_par_out[220]
  PIN b_par_out[221]
    DIRECTION OUTPUT ;
    USE SIGNAL ;
    PORT
      LAYER M3 ;
        RECT  130.644 25.882 130.662 25.92 ;
    END
  END b_par_out[221]
  PIN b_par_out[222]
    DIRECTION OUTPUT ;
    USE SIGNAL ;
    PORT
      LAYER M5 ;
        RECT  130.896 25.836 130.92 25.92 ;
    END
  END b_par_out[222]
  PIN b_par_out[223]
    DIRECTION OUTPUT ;
    USE SIGNAL ;
    PORT
      LAYER M3 ;
        RECT  131.112 25.882 131.13 25.92 ;
    END
  END b_par_out[223]
  PIN b_par_out[224]
    DIRECTION OUTPUT ;
    USE SIGNAL ;
    PORT
      LAYER M5 ;
        RECT  131.472 25.836 131.496 25.92 ;
    END
  END b_par_out[224]
  PIN b_par_out[225]
    DIRECTION OUTPUT ;
    USE SIGNAL ;
    PORT
      LAYER M3 ;
        RECT  131.904 25.882 131.922 25.92 ;
    END
  END b_par_out[225]
  PIN b_par_out[226]
    DIRECTION OUTPUT ;
    USE SIGNAL ;
    PORT
      LAYER M5 ;
        RECT  132.24 25.836 132.264 25.92 ;
    END
  END b_par_out[226]
  PIN b_par_out[227]
    DIRECTION OUTPUT ;
    USE SIGNAL ;
    PORT
      LAYER M3 ;
        RECT  132.552 25.882 132.57 25.92 ;
    END
  END b_par_out[227]
  PIN b_par_out[228]
    DIRECTION OUTPUT ;
    USE SIGNAL ;
    PORT
      LAYER M5 ;
        RECT  133.008 25.836 133.032 25.92 ;
    END
  END b_par_out[228]
  PIN b_par_out[229]
    DIRECTION OUTPUT ;
    USE SIGNAL ;
    PORT
      LAYER M3 ;
        RECT  133.344 25.882 133.362 25.92 ;
    END
    PORT
      LAYER M3 ;
        RECT  133.344 25.805 133.362 25.901 ;
    END
  END b_par_out[229]
  PIN b_par_out[22]
    DIRECTION OUTPUT ;
    USE SIGNAL ;
    PORT
      LAYER M5 ;
        RECT  89.904 25.836 89.928 25.92 ;
    END
  END b_par_out[22]
  PIN b_par_out[230]
    DIRECTION OUTPUT ;
    USE SIGNAL ;
    PORT
      LAYER M5 ;
        RECT  133.68 25.836 133.704 25.92 ;
    END
  END b_par_out[230]
  PIN b_par_out[231]
    DIRECTION OUTPUT ;
    USE SIGNAL ;
    PORT
      LAYER M3 ;
        RECT  134.1 25.882 134.118 25.92 ;
    END
    PORT
      LAYER M3 ;
        RECT  134.1 25.805 134.118 25.901 ;
    END
  END b_par_out[231]
  PIN b_par_out[232]
    DIRECTION OUTPUT ;
    USE SIGNAL ;
    PORT
      LAYER M5 ;
        RECT  134.448 25.836 134.472 25.92 ;
    END
  END b_par_out[232]
  PIN b_par_out[233]
    DIRECTION OUTPUT ;
    USE SIGNAL ;
    PORT
      LAYER M3 ;
        RECT  134.856 25.882 134.874 25.92 ;
    END
  END b_par_out[233]
  PIN b_par_out[234]
    DIRECTION OUTPUT ;
    USE SIGNAL ;
    PORT
      LAYER M5 ;
        RECT  135.216 25.836 135.24 25.92 ;
    END
  END b_par_out[234]
  PIN b_par_out[235]
    DIRECTION OUTPUT ;
    USE SIGNAL ;
    PORT
      LAYER M3 ;
        RECT  135.54 25.882 135.558 25.92 ;
    END
  END b_par_out[235]
  PIN b_par_out[236]
    DIRECTION OUTPUT ;
    USE SIGNAL ;
    PORT
      LAYER M5 ;
        RECT  135.984 25.836 136.008 25.92 ;
    END
  END b_par_out[236]
  PIN b_par_out[237]
    DIRECTION OUTPUT ;
    USE SIGNAL ;
    PORT
      LAYER M3 ;
        RECT  136.296 25.882 136.314 25.92 ;
    END
    PORT
      LAYER M3 ;
        RECT  136.296 25.889 136.314 25.901 ;
    END
  END b_par_out[237]
  PIN b_par_out[238]
    DIRECTION OUTPUT ;
    USE SIGNAL ;
    PORT
      LAYER M5 ;
        RECT  136.656 25.836 136.68 25.92 ;
    END
  END b_par_out[238]
  PIN b_par_out[239]
    DIRECTION OUTPUT ;
    USE SIGNAL ;
    PORT
      LAYER M3 ;
        RECT  137.088 25.882 137.106 25.92 ;
    END
    PORT
      LAYER M3 ;
        RECT  137.088 25.889 137.106 25.901 ;
    END
  END b_par_out[239]
  PIN b_par_out[23]
    DIRECTION OUTPUT ;
    USE SIGNAL ;
    PORT
      LAYER M3 ;
        RECT  90.144 25.882 90.162 25.92 ;
    END
  END b_par_out[23]
  PIN b_par_out[240]
    DIRECTION OUTPUT ;
    USE SIGNAL ;
    PORT
      LAYER M5 ;
        RECT  137.424 25.836 137.448 25.92 ;
    END
  END b_par_out[240]
  PIN b_par_out[241]
    DIRECTION OUTPUT ;
    USE SIGNAL ;
    PORT
      LAYER M3 ;
        RECT  137.844 25.882 137.862 25.92 ;
    END
  END b_par_out[241]
  PIN b_par_out[242]
    DIRECTION OUTPUT ;
    USE SIGNAL ;
    PORT
      LAYER M5 ;
        RECT  138.192 25.836 138.216 25.92 ;
    END
  END b_par_out[242]
  PIN b_par_out[243]
    DIRECTION OUTPUT ;
    USE SIGNAL ;
    PORT
      LAYER M3 ;
        RECT  138.528 25.882 138.546 25.92 ;
    END
  END b_par_out[243]
  PIN b_par_out[244]
    DIRECTION OUTPUT ;
    USE SIGNAL ;
    PORT
      LAYER M5 ;
        RECT  138.96 25.836 138.984 25.92 ;
    END
  END b_par_out[244]
  PIN b_par_out[245]
    DIRECTION OUTPUT ;
    USE SIGNAL ;
    PORT
      LAYER M3 ;
        RECT  139.284 25.882 139.302 25.92 ;
    END
    PORT
      LAYER M3 ;
        RECT  139.284 25.133 139.302 25.901 ;
    END
  END b_par_out[245]
  PIN b_par_out[246]
    DIRECTION OUTPUT ;
    USE SIGNAL ;
    PORT
      LAYER M5 ;
        RECT  139.632 25.836 139.656 25.92 ;
    END
  END b_par_out[246]
  PIN b_par_out[247]
    DIRECTION OUTPUT ;
    USE SIGNAL ;
    PORT
      LAYER M3 ;
        RECT  140.04 25.882 140.058 25.92 ;
    END
    PORT
      LAYER M3 ;
        RECT  140.04 25.133 140.058 25.901 ;
    END
  END b_par_out[247]
  PIN b_par_out[248]
    DIRECTION OUTPUT ;
    USE SIGNAL ;
    PORT
      LAYER M5 ;
        RECT  140.4 25.836 140.424 25.92 ;
    END
  END b_par_out[248]
  PIN b_par_out[249]
    DIRECTION OUTPUT ;
    USE SIGNAL ;
    PORT
      LAYER M3 ;
        RECT  140.832 25.882 140.85 25.92 ;
    END
  END b_par_out[249]
  PIN b_par_out[24]
    DIRECTION OUTPUT ;
    USE SIGNAL ;
    PORT
      LAYER M5 ;
        RECT  90.384 25.836 90.408 25.92 ;
    END
  END b_par_out[24]
  PIN b_par_out[250]
    DIRECTION OUTPUT ;
    USE SIGNAL ;
    PORT
      LAYER M5 ;
        RECT  141.168 25.836 141.192 25.92 ;
    END
  END b_par_out[250]
  PIN b_par_out[251]
    DIRECTION OUTPUT ;
    USE SIGNAL ;
    PORT
      LAYER M3 ;
        RECT  141.48 25.882 141.498 25.92 ;
    END
  END b_par_out[251]
  PIN b_par_out[252]
    DIRECTION OUTPUT ;
    USE SIGNAL ;
    PORT
      LAYER M5 ;
        RECT  141.936 25.836 141.96 25.92 ;
    END
  END b_par_out[252]
  PIN b_par_out[253]
    DIRECTION OUTPUT ;
    USE SIGNAL ;
    PORT
      LAYER M3 ;
        RECT  142.272 25.882 142.29 25.92 ;
    END
    PORT
      LAYER M3 ;
        RECT  142.272 24.557 142.29 25.901 ;
    END
  END b_par_out[253]
  PIN b_par_out[254]
    DIRECTION OUTPUT ;
    USE SIGNAL ;
    PORT
      LAYER M5 ;
        RECT  142.704 25.836 142.728 25.92 ;
    END
  END b_par_out[254]
  PIN b_par_out[255]
    DIRECTION OUTPUT ;
    USE SIGNAL ;
    PORT
      LAYER M3 ;
        RECT  143.028 25.882 143.046 25.92 ;
    END
    PORT
      LAYER M3 ;
        RECT  143.028 24.557 143.046 25.901 ;
    END
  END b_par_out[255]
  PIN b_par_out[25]
    DIRECTION OUTPUT ;
    USE SIGNAL ;
    PORT
      LAYER M3 ;
        RECT  90.504 25.882 90.522 25.92 ;
    END
  END b_par_out[25]
  PIN b_par_out[26]
    DIRECTION OUTPUT ;
    USE SIGNAL ;
    PORT
      LAYER M5 ;
        RECT  90.768 25.836 90.792 25.92 ;
    END
  END b_par_out[26]
  PIN b_par_out[27]
    DIRECTION OUTPUT ;
    USE SIGNAL ;
    PORT
      LAYER M3 ;
        RECT  90.9 25.882 90.918 25.92 ;
    END
  END b_par_out[27]
  PIN b_par_out[28]
    DIRECTION OUTPUT ;
    USE SIGNAL ;
    PORT
      LAYER M5 ;
        RECT  91.152 25.836 91.176 25.92 ;
    END
  END b_par_out[28]
  PIN b_par_out[29]
    DIRECTION OUTPUT ;
    USE SIGNAL ;
    PORT
      LAYER M3 ;
        RECT  91.368 25.882 91.386 25.92 ;
    END
  END b_par_out[29]
  PIN b_par_out[2]
    DIRECTION OUTPUT ;
    USE SIGNAL ;
    PORT
      LAYER M5 ;
        RECT  85.872 25.836 85.896 25.92 ;
    END
  END b_par_out[2]
  PIN b_par_out[30]
    DIRECTION OUTPUT ;
    USE SIGNAL ;
    PORT
      LAYER M5 ;
        RECT  91.536 25.836 91.56 25.92 ;
    END
  END b_par_out[30]
  PIN b_par_out[31]
    DIRECTION OUTPUT ;
    USE SIGNAL ;
    PORT
      LAYER M3 ;
        RECT  91.764 25.882 91.782 25.92 ;
    END
  END b_par_out[31]
  PIN b_par_out[32]
    DIRECTION OUTPUT ;
    USE SIGNAL ;
    PORT
      LAYER M5 ;
        RECT  92.016 25.836 92.04 25.92 ;
    END
  END b_par_out[32]
  PIN b_par_out[33]
    DIRECTION OUTPUT ;
    USE SIGNAL ;
    PORT
      LAYER M3 ;
        RECT  92.16 25.882 92.178 25.92 ;
    END
  END b_par_out[33]
  PIN b_par_out[34]
    DIRECTION OUTPUT ;
    USE SIGNAL ;
    PORT
      LAYER M5 ;
        RECT  92.4 25.836 92.424 25.92 ;
    END
  END b_par_out[34]
  PIN b_par_out[35]
    DIRECTION OUTPUT ;
    USE SIGNAL ;
    PORT
      LAYER M3 ;
        RECT  92.52 25.882 92.538 25.92 ;
    END
  END b_par_out[35]
  PIN b_par_out[36]
    DIRECTION OUTPUT ;
    USE SIGNAL ;
    PORT
      LAYER M5 ;
        RECT  92.784 25.836 92.808 25.92 ;
    END
  END b_par_out[36]
  PIN b_par_out[37]
    DIRECTION OUTPUT ;
    USE SIGNAL ;
    PORT
      LAYER M3 ;
        RECT  93.024 25.882 93.042 25.92 ;
    END
  END b_par_out[37]
  PIN b_par_out[38]
    DIRECTION OUTPUT ;
    USE SIGNAL ;
    PORT
      LAYER M5 ;
        RECT  93.168 25.836 93.192 25.92 ;
    END
  END b_par_out[38]
  PIN b_par_out[39]
    DIRECTION OUTPUT ;
    USE SIGNAL ;
    PORT
      LAYER M3 ;
        RECT  93.384 25.882 93.402 25.92 ;
    END
  END b_par_out[39]
  PIN b_par_out[3]
    DIRECTION OUTPUT ;
    USE SIGNAL ;
    PORT
      LAYER M3 ;
        RECT  86.004 25.882 86.022 25.92 ;
    END
  END b_par_out[3]
  PIN b_par_out[40]
    DIRECTION OUTPUT ;
    USE SIGNAL ;
    PORT
      LAYER M5 ;
        RECT  93.648 25.836 93.672 25.92 ;
    END
  END b_par_out[40]
  PIN b_par_out[41]
    DIRECTION OUTPUT ;
    USE SIGNAL ;
    PORT
      LAYER M3 ;
        RECT  93.78 25.882 93.798 25.92 ;
    END
  END b_par_out[41]
  PIN b_par_out[42]
    DIRECTION OUTPUT ;
    USE SIGNAL ;
    PORT
      LAYER M5 ;
        RECT  94.032 25.836 94.056 25.92 ;
    END
  END b_par_out[42]
  PIN b_par_out[43]
    DIRECTION OUTPUT ;
    USE SIGNAL ;
    PORT
      LAYER M3 ;
        RECT  94.248 25.882 94.266 25.92 ;
    END
  END b_par_out[43]
  PIN b_par_out[44]
    DIRECTION OUTPUT ;
    USE SIGNAL ;
    PORT
      LAYER M5 ;
        RECT  94.416 25.836 94.44 25.92 ;
    END
  END b_par_out[44]
  PIN b_par_out[45]
    DIRECTION OUTPUT ;
    USE SIGNAL ;
    PORT
      LAYER M3 ;
        RECT  94.644 25.882 94.662 25.92 ;
    END
  END b_par_out[45]
  PIN b_par_out[46]
    DIRECTION OUTPUT ;
    USE SIGNAL ;
    PORT
      LAYER M5 ;
        RECT  94.8 25.836 94.824 25.92 ;
    END
  END b_par_out[46]
  PIN b_par_out[47]
    DIRECTION OUTPUT ;
    USE SIGNAL ;
    PORT
      LAYER M3 ;
        RECT  95.04 25.882 95.058 25.92 ;
    END
  END b_par_out[47]
  PIN b_par_out[48]
    DIRECTION OUTPUT ;
    USE SIGNAL ;
    PORT
      LAYER M5 ;
        RECT  95.28 25.836 95.304 25.92 ;
    END
  END b_par_out[48]
  PIN b_par_out[49]
    DIRECTION OUTPUT ;
    USE SIGNAL ;
    PORT
      LAYER M3 ;
        RECT  95.4 25.882 95.418 25.92 ;
    END
  END b_par_out[49]
  PIN b_par_out[4]
    DIRECTION OUTPUT ;
    USE SIGNAL ;
    PORT
      LAYER M5 ;
        RECT  86.256 25.836 86.28 25.92 ;
    END
  END b_par_out[4]
  PIN b_par_out[50]
    DIRECTION OUTPUT ;
    USE SIGNAL ;
    PORT
      LAYER M5 ;
        RECT  95.664 25.836 95.688 25.92 ;
    END
  END b_par_out[50]
  PIN b_par_out[51]
    DIRECTION OUTPUT ;
    USE SIGNAL ;
    PORT
      LAYER M3 ;
        RECT  95.904 25.882 95.922 25.92 ;
    END
  END b_par_out[51]
  PIN b_par_out[52]
    DIRECTION OUTPUT ;
    USE SIGNAL ;
    PORT
      LAYER M5 ;
        RECT  96.048 25.836 96.072 25.92 ;
    END
  END b_par_out[52]
  PIN b_par_out[53]
    DIRECTION OUTPUT ;
    USE SIGNAL ;
    PORT
      LAYER M3 ;
        RECT  96.264 25.882 96.282 25.92 ;
    END
  END b_par_out[53]
  PIN b_par_out[54]
    DIRECTION OUTPUT ;
    USE SIGNAL ;
    PORT
      LAYER M5 ;
        RECT  96.528 25.836 96.552 25.92 ;
    END
  END b_par_out[54]
  PIN b_par_out[55]
    DIRECTION OUTPUT ;
    USE SIGNAL ;
    PORT
      LAYER M3 ;
        RECT  96.66 25.882 96.678 25.92 ;
    END
  END b_par_out[55]
  PIN b_par_out[56]
    DIRECTION OUTPUT ;
    USE SIGNAL ;
    PORT
      LAYER M5 ;
        RECT  96.912 25.836 96.936 25.92 ;
    END
  END b_par_out[56]
  PIN b_par_out[57]
    DIRECTION OUTPUT ;
    USE SIGNAL ;
    PORT
      LAYER M3 ;
        RECT  97.056 25.882 97.074 25.92 ;
    END
  END b_par_out[57]
  PIN b_par_out[58]
    DIRECTION OUTPUT ;
    USE SIGNAL ;
    PORT
      LAYER M5 ;
        RECT  97.296 25.836 97.32 25.92 ;
    END
  END b_par_out[58]
  PIN b_par_out[59]
    DIRECTION OUTPUT ;
    USE SIGNAL ;
    PORT
      LAYER M3 ;
        RECT  97.524 25.882 97.542 25.92 ;
    END
  END b_par_out[59]
  PIN b_par_out[5]
    DIRECTION OUTPUT ;
    USE SIGNAL ;
    PORT
      LAYER M3 ;
        RECT  86.472 25.882 86.49 25.92 ;
    END
  END b_par_out[5]
  PIN b_par_out[60]
    DIRECTION OUTPUT ;
    USE SIGNAL ;
    PORT
      LAYER M5 ;
        RECT  97.68 25.836 97.704 25.92 ;
    END
  END b_par_out[60]
  PIN b_par_out[61]
    DIRECTION OUTPUT ;
    USE SIGNAL ;
    PORT
      LAYER M3 ;
        RECT  97.92 25.882 97.938 25.92 ;
    END
  END b_par_out[61]
  PIN b_par_out[62]
    DIRECTION OUTPUT ;
    USE SIGNAL ;
    PORT
      LAYER M5 ;
        RECT  98.16 25.836 98.184 25.92 ;
    END
  END b_par_out[62]
  PIN b_par_out[63]
    DIRECTION OUTPUT ;
    USE SIGNAL ;
    PORT
      LAYER M3 ;
        RECT  98.28 25.882 98.298 25.92 ;
    END
  END b_par_out[63]
  PIN b_par_out[64]
    DIRECTION OUTPUT ;
    USE SIGNAL ;
    PORT
      LAYER M5 ;
        RECT  98.544 25.836 98.568 25.92 ;
    END
  END b_par_out[64]
  PIN b_par_out[65]
    DIRECTION OUTPUT ;
    USE SIGNAL ;
    PORT
      LAYER M3 ;
        RECT  98.676 25.882 98.694 25.92 ;
    END
  END b_par_out[65]
  PIN b_par_out[66]
    DIRECTION OUTPUT ;
    USE SIGNAL ;
    PORT
      LAYER M5 ;
        RECT  98.928 25.836 98.952 25.92 ;
    END
  END b_par_out[66]
  PIN b_par_out[67]
    DIRECTION OUTPUT ;
    USE SIGNAL ;
    PORT
      LAYER M3 ;
        RECT  99.144 25.882 99.162 25.92 ;
    END
  END b_par_out[67]
  PIN b_par_out[68]
    DIRECTION OUTPUT ;
    USE SIGNAL ;
    PORT
      LAYER M5 ;
        RECT  99.312 25.836 99.336 25.92 ;
    END
  END b_par_out[68]
  PIN b_par_out[69]
    DIRECTION OUTPUT ;
    USE SIGNAL ;
    PORT
      LAYER M3 ;
        RECT  99.54 25.882 99.558 25.92 ;
    END
  END b_par_out[69]
  PIN b_par_out[6]
    DIRECTION OUTPUT ;
    USE SIGNAL ;
    PORT
      LAYER M5 ;
        RECT  86.64 25.836 86.664 25.92 ;
    END
  END b_par_out[6]
  PIN b_par_out[70]
    DIRECTION OUTPUT ;
    USE SIGNAL ;
    PORT
      LAYER M5 ;
        RECT  99.792 25.836 99.816 25.92 ;
    END
  END b_par_out[70]
  PIN b_par_out[71]
    DIRECTION OUTPUT ;
    USE SIGNAL ;
    PORT
      LAYER M3 ;
        RECT  99.936 25.882 99.954 25.92 ;
    END
  END b_par_out[71]
  PIN b_par_out[72]
    DIRECTION OUTPUT ;
    USE SIGNAL ;
    PORT
      LAYER M5 ;
        RECT  100.176 25.836 100.2 25.92 ;
    END
  END b_par_out[72]
  PIN b_par_out[73]
    DIRECTION OUTPUT ;
    USE SIGNAL ;
    PORT
      LAYER M3 ;
        RECT  100.404 25.882 100.422 25.92 ;
    END
  END b_par_out[73]
  PIN b_par_out[74]
    DIRECTION OUTPUT ;
    USE SIGNAL ;
    PORT
      LAYER M5 ;
        RECT  100.56 25.836 100.584 25.92 ;
    END
  END b_par_out[74]
  PIN b_par_out[75]
    DIRECTION OUTPUT ;
    USE SIGNAL ;
    PORT
      LAYER M3 ;
        RECT  100.8 25.882 100.818 25.92 ;
    END
  END b_par_out[75]
  PIN b_par_out[76]
    DIRECTION OUTPUT ;
    USE SIGNAL ;
    PORT
      LAYER M5 ;
        RECT  100.944 25.836 100.968 25.92 ;
    END
  END b_par_out[76]
  PIN b_par_out[77]
    DIRECTION OUTPUT ;
    USE SIGNAL ;
    PORT
      LAYER M3 ;
        RECT  101.16 25.882 101.178 25.92 ;
    END
  END b_par_out[77]
  PIN b_par_out[78]
    DIRECTION OUTPUT ;
    USE SIGNAL ;
    PORT
      LAYER M5 ;
        RECT  101.424 25.836 101.448 25.92 ;
    END
  END b_par_out[78]
  PIN b_par_out[79]
    DIRECTION OUTPUT ;
    USE SIGNAL ;
    PORT
      LAYER M3 ;
        RECT  101.556 25.882 101.574 25.92 ;
    END
  END b_par_out[79]
  PIN b_par_out[7]
    DIRECTION OUTPUT ;
    USE SIGNAL ;
    PORT
      LAYER M3 ;
        RECT  86.868 25.882 86.886 25.92 ;
    END
  END b_par_out[7]
  PIN b_par_out[80]
    DIRECTION OUTPUT ;
    USE SIGNAL ;
    PORT
      LAYER M5 ;
        RECT  101.808 25.836 101.832 25.92 ;
    END
  END b_par_out[80]
  PIN b_par_out[81]
    DIRECTION OUTPUT ;
    USE SIGNAL ;
    PORT
      LAYER M3 ;
        RECT  102.024 25.882 102.042 25.92 ;
    END
  END b_par_out[81]
  PIN b_par_out[82]
    DIRECTION OUTPUT ;
    USE SIGNAL ;
    PORT
      LAYER M5 ;
        RECT  102.192 25.836 102.216 25.92 ;
    END
  END b_par_out[82]
  PIN b_par_out[83]
    DIRECTION OUTPUT ;
    USE SIGNAL ;
    PORT
      LAYER M3 ;
        RECT  102.42 25.882 102.438 25.92 ;
    END
  END b_par_out[83]
  PIN b_par_out[84]
    DIRECTION OUTPUT ;
    USE SIGNAL ;
    PORT
      LAYER M5 ;
        RECT  102.576 25.836 102.6 25.92 ;
    END
  END b_par_out[84]
  PIN b_par_out[85]
    DIRECTION OUTPUT ;
    USE SIGNAL ;
    PORT
      LAYER M3 ;
        RECT  102.816 25.882 102.834 25.92 ;
    END
  END b_par_out[85]
  PIN b_par_out[86]
    DIRECTION OUTPUT ;
    USE SIGNAL ;
    PORT
      LAYER M5 ;
        RECT  103.056 25.836 103.08 25.92 ;
    END
  END b_par_out[86]
  PIN b_par_out[87]
    DIRECTION OUTPUT ;
    USE SIGNAL ;
    PORT
      LAYER M3 ;
        RECT  103.176 25.882 103.194 25.92 ;
    END
  END b_par_out[87]
  PIN b_par_out[88]
    DIRECTION OUTPUT ;
    USE SIGNAL ;
    PORT
      LAYER M5 ;
        RECT  103.44 25.836 103.464 25.92 ;
    END
  END b_par_out[88]
  PIN b_par_out[89]
    DIRECTION OUTPUT ;
    USE SIGNAL ;
    PORT
      LAYER M3 ;
        RECT  103.68 25.882 103.698 25.92 ;
    END
  END b_par_out[89]
  PIN b_par_out[8]
    DIRECTION OUTPUT ;
    USE SIGNAL ;
    PORT
      LAYER M5 ;
        RECT  87.024 25.836 87.048 25.92 ;
    END
  END b_par_out[8]
  PIN b_par_out[90]
    DIRECTION OUTPUT ;
    USE SIGNAL ;
    PORT
      LAYER M5 ;
        RECT  103.824 25.836 103.848 25.92 ;
    END
  END b_par_out[90]
  PIN b_par_out[91]
    DIRECTION OUTPUT ;
    USE SIGNAL ;
    PORT
      LAYER M3 ;
        RECT  104.04 25.882 104.058 25.92 ;
    END
  END b_par_out[91]
  PIN b_par_out[92]
    DIRECTION OUTPUT ;
    USE SIGNAL ;
    PORT
      LAYER M5 ;
        RECT  104.304 25.836 104.328 25.92 ;
    END
  END b_par_out[92]
  PIN b_par_out[93]
    DIRECTION OUTPUT ;
    USE SIGNAL ;
    PORT
      LAYER M3 ;
        RECT  104.436 25.882 104.454 25.92 ;
    END
  END b_par_out[93]
  PIN b_par_out[94]
    DIRECTION OUTPUT ;
    USE SIGNAL ;
    PORT
      LAYER M5 ;
        RECT  104.688 25.836 104.712 25.92 ;
    END
  END b_par_out[94]
  PIN b_par_out[95]
    DIRECTION OUTPUT ;
    USE SIGNAL ;
    PORT
      LAYER M3 ;
        RECT  104.832 25.882 104.85 25.92 ;
    END
  END b_par_out[95]
  PIN b_par_out[96]
    DIRECTION OUTPUT ;
    USE SIGNAL ;
    PORT
      LAYER M5 ;
        RECT  105.072 25.836 105.096 25.92 ;
    END
  END b_par_out[96]
  PIN b_par_out[97]
    DIRECTION OUTPUT ;
    USE SIGNAL ;
    PORT
      LAYER M3 ;
        RECT  105.3 25.882 105.318 25.92 ;
    END
  END b_par_out[97]
  PIN b_par_out[98]
    DIRECTION OUTPUT ;
    USE SIGNAL ;
    PORT
      LAYER M5 ;
        RECT  105.456 25.836 105.48 25.92 ;
    END
  END b_par_out[98]
  PIN b_par_out[99]
    DIRECTION OUTPUT ;
    USE SIGNAL ;
    PORT
      LAYER M3 ;
        RECT  105.696 25.882 105.714 25.92 ;
    END
  END b_par_out[99]
  PIN b_par_out[9]
    DIRECTION OUTPUT ;
    USE SIGNAL ;
    PORT
      LAYER M3 ;
        RECT  87.264 25.882 87.282 25.92 ;
    END
  END b_par_out[9]
  PIN clk
    DIRECTION INPUT ;
    USE SIGNAL ;
    PORT
      LAYER M4 ;
        RECT  0 13.008 0.084 13.032 ;
    END
    PORT
      LAYER M4 ;
        RECT  0.06 13.008 0.227 13.032 ;
    END
  END clk
  PIN VDD
    DIRECTION INOUT ;
    USE POWER ;
    PORT
      LAYER M5 ;
        RECT  137.592 2.151 137.712 23.769 ;
        RECT  132.192 2.151 132.312 23.769 ;
        RECT  126.792 2.151 126.912 23.769 ;
        RECT  121.392 2.151 121.512 23.769 ;
        RECT  115.992 2.151 116.112 23.769 ;
        RECT  110.592 2.151 110.712 23.769 ;
        RECT  105.192 2.151 105.312 23.769 ;
        RECT  99.792 2.151 99.912 23.769 ;
        RECT  94.392 2.151 94.512 23.769 ;
        RECT  88.992 2.151 89.112 23.769 ;
        RECT  83.592 2.151 83.712 23.769 ;
        RECT  78.192 2.151 78.312 23.769 ;
        RECT  72.792 2.151 72.912 23.769 ;
        RECT  67.392 2.151 67.512 23.769 ;
        RECT  61.992 2.151 62.112 23.769 ;
        RECT  56.592 2.151 56.712 23.769 ;
        RECT  51.192 2.151 51.312 23.769 ;
        RECT  45.792 2.151 45.912 23.769 ;
        RECT  40.392 2.151 40.512 23.769 ;
        RECT  34.992 2.151 35.112 23.769 ;
        RECT  29.592 2.151 29.712 23.769 ;
        RECT  24.192 2.151 24.312 23.769 ;
        RECT  18.792 2.151 18.912 23.769 ;
        RECT  13.392 2.151 13.512 23.769 ;
        RECT  7.992 2.151 8.112 23.769 ;
        RECT  2.592 2.151 2.712 23.769 ;
    END
  END VDD
  PIN VSS
    DIRECTION INOUT ;
    USE GROUND ;
    PORT
      LAYER M5 ;
        RECT  137.4 2.137 137.52 23.783 ;
        RECT  132 2.137 132.12 23.783 ;
        RECT  126.6 2.137 126.72 23.783 ;
        RECT  121.2 2.137 121.32 23.783 ;
        RECT  115.8 2.137 115.92 23.783 ;
        RECT  110.4 2.137 110.52 23.783 ;
        RECT  105 2.137 105.12 23.783 ;
        RECT  99.6 2.137 99.72 23.783 ;
        RECT  94.2 2.137 94.32 23.783 ;
        RECT  88.8 2.137 88.92 23.783 ;
        RECT  83.4 2.137 83.52 23.783 ;
        RECT  78 2.137 78.12 23.783 ;
        RECT  72.6 2.137 72.72 23.783 ;
        RECT  67.2 2.137 67.32 23.783 ;
        RECT  61.8 2.137 61.92 23.783 ;
        RECT  56.4 2.137 56.52 23.783 ;
        RECT  51 2.137 51.12 23.783 ;
        RECT  45.6 2.137 45.72 23.783 ;
        RECT  40.2 2.137 40.32 23.783 ;
        RECT  34.8 2.137 34.92 23.783 ;
        RECT  29.4 2.137 29.52 23.783 ;
        RECT  24 2.137 24.12 23.783 ;
        RECT  18.6 2.137 18.72 23.783 ;
        RECT  13.2 2.137 13.32 23.783 ;
        RECT  7.8 2.137 7.92 23.783 ;
        RECT  2.4 2.137 2.52 23.783 ;
    END
  END VSS
  # OT_OBS_CLOSED layer=M5 d_um=1.536 added=167
  OBS
    LAYER RVTN ;
     RECT  2.16 2.16 142.02 2.295 ;
     RECT  2.16 2.565 142.02 2.835 ;
     RECT  2.16 3.105 142.02 3.375 ;
     RECT  2.16 3.645 142.02 3.915 ;
     RECT  2.16 4.185 142.02 4.455 ;
     RECT  2.16 4.725 142.02 4.995 ;
     RECT  2.16 5.265 142.02 5.535 ;
     RECT  2.16 5.805 142.02 6.075 ;
     RECT  2.16 6.345 142.02 6.615 ;
     RECT  2.16 6.885 142.02 7.155 ;
     RECT  2.16 7.425 142.02 7.695 ;
     RECT  2.16 7.965 142.02 8.235 ;
     RECT  2.16 8.505 142.02 8.775 ;
     RECT  2.16 9.045 142.02 9.315 ;
     RECT  2.16 9.585 142.02 9.855 ;
     RECT  2.16 10.125 142.02 10.395 ;
     RECT  2.16 10.665 142.02 10.935 ;
     RECT  2.16 11.205 142.02 11.475 ;
     RECT  2.16 11.745 142.02 12.015 ;
     RECT  2.16 12.285 142.02 12.555 ;
     RECT  2.16 12.825 142.02 13.095 ;
     RECT  2.16 13.365 142.02 13.635 ;
     RECT  2.16 13.905 142.02 14.175 ;
     RECT  2.16 14.445 142.02 14.715 ;
     RECT  2.16 14.985 142.02 15.255 ;
     RECT  2.16 15.525 142.02 15.795 ;
     RECT  2.16 16.065 142.02 16.335 ;
     RECT  2.16 16.605 142.02 16.875 ;
     RECT  2.16 17.145 142.02 17.415 ;
     RECT  2.16 17.685 142.02 17.955 ;
     RECT  2.16 18.225 142.02 18.495 ;
     RECT  2.16 18.765 142.02 19.035 ;
     RECT  2.16 19.305 142.02 19.575 ;
     RECT  2.16 19.845 142.02 20.115 ;
     RECT  2.16 20.385 142.02 20.655 ;
     RECT  2.16 20.925 142.02 21.195 ;
     RECT  2.16 21.465 142.02 21.735 ;
     RECT  2.16 22.005 142.02 22.275 ;
     RECT  2.16 22.545 142.02 22.815 ;
     RECT  2.16 23.085 142.02 23.355 ;
     RECT  2.16 23.625 142.02 23.76 ;
    LAYER RVTP ;
     RECT  2.16 2.295 142.02 2.565 ;
     RECT  2.16 2.835 142.02 3.105 ;
     RECT  2.16 3.375 142.02 3.645 ;
     RECT  2.16 3.915 142.02 4.185 ;
     RECT  2.16 4.455 142.02 4.725 ;
     RECT  2.16 4.995 142.02 5.265 ;
     RECT  2.16 5.535 142.02 5.805 ;
     RECT  2.16 6.075 142.02 6.345 ;
     RECT  2.16 6.615 142.02 6.885 ;
     RECT  2.16 7.155 142.02 7.425 ;
     RECT  2.16 7.695 142.02 7.965 ;
     RECT  2.16 8.235 142.02 8.505 ;
     RECT  2.16 8.775 142.02 9.045 ;
     RECT  2.16 9.315 142.02 9.585 ;
     RECT  2.16 9.855 142.02 10.125 ;
     RECT  2.16 10.395 142.02 10.665 ;
     RECT  2.16 10.935 142.02 11.205 ;
     RECT  2.16 11.475 142.02 11.745 ;
     RECT  2.16 12.015 142.02 12.285 ;
     RECT  2.16 12.555 142.02 12.825 ;
     RECT  2.16 13.095 142.02 13.365 ;
     RECT  2.16 13.635 142.02 13.905 ;
     RECT  2.16 14.175 142.02 14.445 ;
     RECT  2.16 14.715 142.02 14.985 ;
     RECT  2.16 15.255 142.02 15.525 ;
     RECT  2.16 15.795 142.02 16.065 ;
     RECT  2.16 16.335 142.02 16.605 ;
     RECT  2.16 16.875 142.02 17.145 ;
     RECT  2.16 17.415 142.02 17.685 ;
     RECT  2.16 17.955 142.02 18.225 ;
     RECT  2.16 18.495 142.02 18.765 ;
     RECT  2.16 19.035 142.02 19.305 ;
     RECT  2.16 19.575 142.02 19.845 ;
     RECT  2.16 20.115 142.02 20.385 ;
     RECT  2.16 20.655 142.02 20.925 ;
     RECT  2.16 21.195 142.02 21.465 ;
     RECT  2.16 21.735 142.02 22.005 ;
     RECT  2.16 22.275 142.02 22.545 ;
     RECT  2.16 22.815 142.02 23.085 ;
     RECT  2.16 23.355 142.02 23.625 ;
    LAYER M1 ;
     RECT  2.16 2.151 142.02 23.769 ;
    LAYER M2 ;
     RECT  2.16 2.151 13.171 23.769 ;
     RECT  13.171 1.728 13.271 23.769 ;
     RECT  13.171 25.866 13.271 25.884 ;
     RECT  14.287 25.866 14.423 25.884 ;
     RECT  13.271 2.151 14.863 23.769 ;
     RECT  14.863 2.151 15.035 23.814 ;
     RECT  16.411 0.036 16.511 0.054 ;
     RECT  17.995 25.146 18.167 25.164 ;
     RECT  18.895 0.036 18.995 0.054 ;
     RECT  15.035 2.151 19.615 23.769 ;
     RECT  19.615 2.151 19.787 23.922 ;
     RECT  19.787 2.151 20.695 23.769 ;
     RECT  20.695 2.151 21.767 23.814 ;
     RECT  21.767 2.151 29.947 23.769 ;
     RECT  29.947 1.728 30.155 23.769 ;
     RECT  30.155 2.151 31.747 23.769 ;
     RECT  31.747 2.151 31.919 23.922 ;
     RECT  34.267 25.866 35.159 25.884 ;
     RECT  41.467 25.866 41.567 25.884 ;
     RECT  42.403 25.866 42.503 25.884 ;
     RECT  44.059 25.866 44.159 25.884 ;
     RECT  31.919 2.151 45.679 23.769 ;
     RECT  45.679 0.036 45.779 0.054 ;
     RECT  45.679 2.151 45.779 23.922 ;
     RECT  45.779 2.151 47.299 23.769 ;
     RECT  47.299 2.151 47.983 23.814 ;
     RECT  47.983 1.728 48.119 23.814 ;
     RECT  48.119 1.728 48.191 23.769 ;
     RECT  50.575 25.866 50.711 25.884 ;
     RECT  48.191 2.151 51.223 23.769 ;
     RECT  51.223 2.151 52.187 23.814 ;
     RECT  56.263 25.866 56.363 25.884 ;
     RECT  61.231 25.056 61.331 25.074 ;
     RECT  52.187 2.151 61.591 23.769 ;
     RECT  61.771 0.036 61.943 0.054 ;
     RECT  61.591 2.151 61.943 23.85 ;
     RECT  62.275 25.056 62.483 25.074 ;
     RECT  61.943 2.151 63.931 23.769 ;
     RECT  63.931 2.151 64.211 23.814 ;
     RECT  64.687 25.056 65.723 25.074 ;
     RECT  67.099 25.056 67.199 25.074 ;
     RECT  68.827 25.056 68.963 25.074 ;
     RECT  64.211 2.151 71.311 23.769 ;
     RECT  71.311 2.151 71.383 23.922 ;
     RECT  71.383 2.151 71.735 23.994 ;
     RECT  71.735 2.151 76.855 23.769 ;
     RECT  76.855 2.151 77.395 23.814 ;
     RECT  77.395 2.151 77.495 23.886 ;
     RECT  77.495 2.151 78.223 23.769 ;
     RECT  78.223 0.036 78.359 0.054 ;
     RECT  78.223 2.151 78.431 23.814 ;
     RECT  82.363 0.036 82.571 0.054 ;
     RECT  78.431 2.151 83.731 23.769 ;
     RECT  83.731 2.151 84.163 23.814 ;
     RECT  84.163 2.151 84.371 23.922 ;
     RECT  84.371 2.151 84.479 23.814 ;
     RECT  87.259 0.036 87.359 0.054 ;
     RECT  84.479 2.151 87.619 23.769 ;
     RECT  87.619 2.151 88.123 23.814 ;
     RECT  88.123 2.151 88.295 23.886 ;
     RECT  88.771 0.036 88.907 0.054 ;
     RECT  88.295 2.151 89.915 23.85 ;
     RECT  89.915 2.151 94.243 23.769 ;
     RECT  93.775 0.036 94.271 0.054 ;
     RECT  94.243 2.151 94.559 23.85 ;
     RECT  99.463 25.146 99.563 25.164 ;
     RECT  102.343 0.036 102.443 0.054 ;
     RECT  94.559 2.151 103.531 23.769 ;
     RECT  103.531 2.151 103.703 23.814 ;
     RECT  104.431 24.561 104.567 24.579 ;
     RECT  103.703 2.151 106.375 23.769 ;
     RECT  106.375 2.151 106.583 23.994 ;
     RECT  108.571 25.794 108.779 25.812 ;
     RECT  106.583 2.151 109.831 23.769 ;
     RECT  110.875 0.036 110.975 0.054 ;
     RECT  109.831 2.151 111.011 23.814 ;
     RECT  117.859 24.561 117.995 24.579 ;
     RECT  111.011 2.151 118.723 23.769 ;
     RECT  118.723 2.151 118.823 23.958 ;
     RECT  118.823 2.151 119.947 23.922 ;
     RECT  119.947 2.151 120.011 23.958 ;
     RECT  120.011 2.151 120.847 23.769 ;
     RECT  120.847 2.151 121.027 23.958 ;
     RECT  121.027 2.151 121.271 24.039 ;
     RECT  121.243 0.036 121.379 0.054 ;
     RECT  121.271 2.151 122.315 23.958 ;
     RECT  124.879 25.056 125.015 25.074 ;
     RECT  122.315 2.151 125.347 23.769 ;
     RECT  125.347 2.151 126.607 23.814 ;
     RECT  126.535 0.036 126.635 0.054 ;
     RECT  126.751 25.056 127.031 25.074 ;
     RECT  126.607 2.151 127.103 23.85 ;
     RECT  127.103 2.151 127.571 23.814 ;
     RECT  128.155 25.056 128.255 25.074 ;
     RECT  127.571 2.151 128.623 23.769 ;
     RECT  129.811 0.036 129.911 0.054 ;
     RECT  128.623 2.151 130.639 23.814 ;
     RECT  130.639 2.151 130.955 23.886 ;
     RECT  130.955 2.151 132.439 23.769 ;
     RECT  132.439 1.728 132.575 23.769 ;
     RECT  132.547 25.146 132.683 25.164 ;
     RECT  136.291 25.866 136.463 25.884 ;
     RECT  132.575 2.151 137.011 23.769 ;
     RECT  137.011 2.106 138.047 23.769 ;
     RECT  138.047 2.151 142.02 23.769 ;
     RECT  142.02 2.538 142.295 2.826 ;
     RECT  142.02 21.474 142.295 22.572 ;
     RECT  142.295 21.474 142.547 22.032 ;
     RECT  142.02 3.618 142.727 3.636 ;
     RECT  142.295 2.808 143.051 2.826 ;
     RECT  142.547 21.474 143.051 21.492 ;
    LAYER M3 ;
     RECT  59.634 0.012 60.264 0.038 ;
     RECT  60.282 0.012 60.66 0.038 ;
     RECT  60.678 0.012 61.056 0.038 ;
     RECT  61.074 0.012 61.416 0.038 ;
     RECT  61.434 0.012 61.92 0.038 ;
     RECT  61.938 0.012 62.28 0.038 ;
     RECT  62.298 0.012 62.676 0.038 ;
     RECT  62.694 0.012 63.072 0.038 ;
     RECT  63.09 0.012 63.54 0.038 ;
     RECT  63.558 0.012 63.936 0.038 ;
     RECT  63.954 0.012 64.296 0.038 ;
     RECT  64.314 0.012 64.692 0.038 ;
     RECT  64.71 0.012 65.16 0.038 ;
     RECT  65.178 0.012 65.556 0.038 ;
     RECT  65.574 0.012 65.952 0.038 ;
     RECT  65.97 0.012 66.42 0.038 ;
     RECT  66.438 0.012 66.816 0.038 ;
     RECT  66.834 0.012 67.176 0.038 ;
     RECT  67.194 0.012 67.572 0.038 ;
     RECT  67.59 0.012 68.04 0.038 ;
     RECT  68.058 0.012 68.436 0.038 ;
     RECT  68.454 0.012 68.832 0.038 ;
     RECT  68.85 0.012 69.192 0.038 ;
     RECT  69.21 0.012 69.696 0.038 ;
     RECT  69.714 0.012 70.056 0.038 ;
     RECT  70.074 0.012 70.452 0.038 ;
     RECT  70.47 0.012 70.848 0.038 ;
     RECT  70.866 0.012 71.316 0.038 ;
     RECT  71.334 0.012 71.712 0.038 ;
     RECT  71.73 0.012 72.072 0.038 ;
     RECT  72.09 0.012 72.468 0.038 ;
     RECT  72.486 0.012 72.936 0.038 ;
     RECT  72.954 0.012 73.332 0.038 ;
     RECT  73.35 0.012 73.728 0.038 ;
     RECT  73.746 0.012 74.196 0.038 ;
     RECT  74.214 0.012 74.592 0.038 ;
     RECT  74.61 0.012 74.952 0.038 ;
     RECT  74.97 0.012 75.348 0.038 ;
     RECT  75.366 0.012 75.816 0.038 ;
     RECT  75.834 0.012 76.212 0.038 ;
     RECT  76.23 0.012 76.608 0.038 ;
     RECT  76.626 0.012 76.968 0.038 ;
     RECT  76.986 0.012 77.472 0.038 ;
     RECT  77.49 0.012 77.832 0.038 ;
     RECT  77.85 0.012 78.228 0.038 ;
     RECT  78.246 0.012 78.624 0.038 ;
     RECT  78.642 0.012 79.092 0.038 ;
     RECT  79.11 0.012 79.488 0.038 ;
     RECT  79.506 0.012 79.848 0.038 ;
     RECT  79.866 0.012 80.352 0.038 ;
     RECT  80.37 0.012 80.712 0.038 ;
     RECT  80.73 0.012 81.108 0.038 ;
     RECT  81.126 0.012 81.504 0.038 ;
     RECT  81.522 0.012 81.972 0.038 ;
     RECT  81.99 0.012 82.368 0.038 ;
     RECT  82.386 0.012 82.728 0.038 ;
     RECT  82.746 0.012 83.124 0.038 ;
     RECT  83.142 0.012 83.592 0.038 ;
     RECT  83.61 0.012 83.988 0.038 ;
     RECT  84.006 0.012 84.384 0.038 ;
     RECT  84.402 0.012 84.744 0.038 ;
     RECT  84.762 0.012 85.248 0.038 ;
     RECT  85.266 0.012 85.608 0.038 ;
     RECT  85.626 0.012 86.004 0.038 ;
     RECT  86.022 0.012 86.472 0.038 ;
     RECT  86.49 0.012 86.868 0.038 ;
     RECT  86.886 0.012 87.264 0.038 ;
     RECT  87.282 0.012 87.624 0.038 ;
     RECT  87.642 0.012 88.128 0.038 ;
     RECT  88.146 0.012 88.488 0.038 ;
     RECT  88.506 0.012 88.884 0.038 ;
     RECT  88.902 0.012 89.28 0.038 ;
     RECT  89.298 0.012 89.748 0.038 ;
     RECT  89.766 0.012 90.144 0.038 ;
     RECT  90.162 0.012 90.504 0.038 ;
     RECT  90.522 0.012 90.9 0.038 ;
     RECT  90.918 0.012 91.368 0.038 ;
     RECT  91.386 0.012 91.764 0.038 ;
     RECT  91.782 0.012 92.16 0.038 ;
     RECT  92.178 0.012 92.52 0.038 ;
     RECT  92.538 0.012 93.024 0.038 ;
     RECT  93.042 0.012 93.384 0.038 ;
     RECT  93.402 0.012 93.78 0.038 ;
     RECT  93.798 0.012 94.248 0.038 ;
     RECT  94.266 0.012 94.644 0.038 ;
     RECT  94.662 0.012 95.04 0.038 ;
     RECT  95.058 0.012 95.4 0.038 ;
     RECT  95.418 0.012 95.904 0.038 ;
     RECT  95.922 0.012 96.264 0.038 ;
     RECT  96.282 0.012 96.66 0.038 ;
     RECT  96.678 0.012 97.056 0.038 ;
     RECT  97.074 0.012 97.524 0.038 ;
     RECT  97.542 0.012 97.92 0.038 ;
     RECT  97.938 0.012 98.28 0.038 ;
     RECT  98.298 0.012 98.676 0.038 ;
     RECT  98.694 0.012 99.144 0.038 ;
     RECT  99.162 0.012 99.54 0.038 ;
     RECT  99.558 0.012 99.936 0.038 ;
     RECT  99.954 0.012 100.404 0.038 ;
     RECT  100.422 0.012 100.8 0.038 ;
     RECT  100.818 0.012 101.16 0.038 ;
     RECT  101.178 0.012 101.556 0.038 ;
     RECT  101.574 0.012 102.024 0.038 ;
     RECT  102.042 0.012 102.42 0.038 ;
     RECT  102.438 0.012 102.816 0.038 ;
     RECT  102.834 0.012 103.176 0.038 ;
     RECT  103.194 0.012 103.68 0.038 ;
     RECT  103.698 0.012 104.04 0.038 ;
     RECT  104.058 0.012 104.436 0.038 ;
     RECT  104.454 0.012 104.832 0.038 ;
     RECT  104.85 0.012 105.3 0.038 ;
     RECT  105.318 0.012 105.696 0.038 ;
     RECT  105.714 0.012 106.056 0.038 ;
     RECT  106.074 0.012 106.56 0.038 ;
     RECT  106.578 0.012 106.92 0.038 ;
     RECT  106.938 0.012 107.316 0.038 ;
     RECT  107.334 0.012 107.712 0.038 ;
     RECT  107.73 0.012 108.18 0.038 ;
     RECT  108.198 0.012 108.576 0.038 ;
     RECT  108.594 0.012 108.936 0.038 ;
     RECT  108.954 0.012 109.332 0.038 ;
     RECT  109.35 0.012 109.8 0.038 ;
     RECT  109.818 0.012 110.196 0.038 ;
     RECT  110.214 0.012 110.592 0.038 ;
     RECT  110.61 0.012 110.952 0.038 ;
     RECT  110.97 0.012 111.456 0.038 ;
     RECT  111.474 0.012 111.816 0.038 ;
     RECT  111.834 0.012 112.212 0.038 ;
     RECT  112.23 0.012 112.608 0.038 ;
     RECT  112.626 0.012 113.076 0.038 ;
     RECT  113.094 0.012 113.472 0.038 ;
     RECT  113.49 0.012 113.832 0.038 ;
     RECT  113.85 0.012 114.336 0.038 ;
     RECT  114.354 0.012 114.696 0.038 ;
     RECT  114.714 0.012 115.092 0.038 ;
     RECT  115.11 0.012 115.488 0.038 ;
     RECT  115.506 0.012 115.956 0.038 ;
     RECT  115.974 0.012 116.352 0.038 ;
     RECT  116.37 0.012 116.712 0.038 ;
     RECT  116.73 0.012 117.108 0.038 ;
     RECT  117.126 0.012 117.576 0.038 ;
     RECT  117.594 0.012 117.972 0.038 ;
     RECT  117.99 0.012 118.368 0.038 ;
     RECT  118.386 0.012 118.728 0.038 ;
     RECT  118.746 0.012 119.232 0.038 ;
     RECT  119.25 0.012 119.592 0.038 ;
     RECT  119.61 0.012 119.988 0.038 ;
     RECT  120.006 0.012 120.456 0.038 ;
     RECT  120.474 0.012 120.852 0.038 ;
     RECT  120.87 0.012 121.248 0.038 ;
     RECT  121.266 0.012 121.608 0.038 ;
     RECT  121.626 0.012 122.112 0.038 ;
     RECT  122.13 0.012 122.472 0.038 ;
     RECT  122.49 0.012 122.868 0.038 ;
     RECT  122.886 0.012 123.264 0.038 ;
     RECT  123.282 0.012 123.732 0.038 ;
     RECT  123.75 0.012 124.128 0.038 ;
     RECT  124.146 0.012 124.488 0.038 ;
     RECT  124.506 0.012 124.884 0.038 ;
     RECT  124.902 0.012 125.352 0.038 ;
     RECT  125.37 0.012 125.748 0.038 ;
     RECT  125.766 0.012 126.144 0.038 ;
     RECT  126.162 0.012 126.612 0.038 ;
     RECT  126.63 0.012 127.008 0.038 ;
     RECT  127.026 0.012 127.368 0.038 ;
     RECT  127.386 0.012 127.764 0.038 ;
     RECT  127.782 0.012 128.232 0.038 ;
     RECT  128.25 0.012 128.628 0.038 ;
     RECT  128.646 0.012 129.024 0.038 ;
     RECT  129.042 0.012 129.384 0.038 ;
     RECT  129.402 0.012 129.888 0.038 ;
     RECT  129.906 0.012 130.248 0.038 ;
     RECT  130.266 0.012 130.644 0.038 ;
     RECT  130.662 0.012 131.112 0.038 ;
     RECT  59.616 0.038 131.13 0.077 ;
     RECT  96.264 0.077 105.318 0.557 ;
     RECT  108.18 0.077 131.13 0.557 ;
     RECT  13.266 0.012 13.608 0.038 ;
     RECT  13.626 0.012 14.004 0.038 ;
     RECT  14.022 0.012 14.4 0.038 ;
     RECT  14.418 0.012 14.868 0.038 ;
     RECT  14.886 0.012 15.264 0.038 ;
     RECT  15.282 0.012 15.624 0.038 ;
     RECT  15.642 0.012 16.128 0.038 ;
     RECT  16.146 0.012 16.488 0.038 ;
     RECT  16.506 0.012 16.884 0.038 ;
     RECT  16.902 0.012 17.28 0.038 ;
     RECT  17.298 0.012 17.748 0.038 ;
     RECT  17.766 0.012 18.144 0.038 ;
     RECT  18.162 0.012 18.504 0.038 ;
     RECT  18.522 0.012 18.9 0.038 ;
     RECT  18.918 0.012 19.368 0.038 ;
     RECT  19.386 0.012 19.764 0.038 ;
     RECT  19.782 0.012 20.34 0.038 ;
     RECT  13.248 0.038 20.358 1.723 ;
     RECT  23.616 0.571 24.39 1.723 ;
     RECT  29.376 0.091 30.15 1.723 ;
     RECT  45.756 0.059 45.774 1.723 ;
     RECT  46.548 0.571 47.322 1.723 ;
     RECT  48.168 0.091 48.978 1.723 ;
     RECT  51.444 0.091 52.218 1.723 ;
     RECT  59.616 0.077 64.71 1.723 ;
     RECT  65.556 0.077 92.286 1.723 ;
     RECT  93.024 0.077 95.418 1.723 ;
     RECT  96.264 0.557 102.834 1.723 ;
     RECT  103.68 0.557 105.318 1.723 ;
     RECT  106.056 0.077 107.334 1.723 ;
     RECT  108.18 0.557 108.594 1.723 ;
     RECT  109.332 0.557 131.13 1.723 ;
     RECT  131.922 0.012 132.552 0.038 ;
     RECT  131.904 0.038 132.57 1.723 ;
     RECT  134.874 0.012 135.54 0.038 ;
     RECT  134.856 0.038 135.558 1.723 ;
     RECT  137.862 0.012 138.528 0.038 ;
     RECT  137.844 0.038 138.546 1.723 ;
     RECT  140.85 0.012 141.48 0.038 ;
     RECT  140.832 0.038 141.498 1.723 ;
     RECT  142.272 0.523 143.046 1.723 ;
     RECT  12.888 1.723 58.842 2.255 ;
     RECT  13.104 2.255 58.842 2.371 ;
     RECT  59.616 1.723 143.046 2.371 ;
     RECT  2.415 2.143 2.505 2.413 ;
     RECT  7.815 2.143 7.905 2.413 ;
     RECT  13.104 2.371 143.046 2.489 ;
     RECT  133.956 2.489 143.046 2.561 ;
     RECT  142.704 2.561 143.046 2.831 ;
     RECT  13.104 2.489 55.062 3.065 ;
     RECT  12.276 2.371 12.294 3.181 ;
     RECT  133.956 2.561 141.966 3.299 ;
     RECT  12.24 3.181 12.294 3.307 ;
     RECT  13.104 3.065 27.054 3.307 ;
     RECT  12.24 3.307 27.054 3.335 ;
     RECT  135.72 3.299 141.966 3.371 ;
     RECT  27.936 3.065 55.062 3.379 ;
     RECT  55.872 2.489 57.222 3.379 ;
     RECT  12.24 3.335 25.758 3.403 ;
     RECT  12.096 3.403 25.758 3.437 ;
     RECT  133.956 3.299 134.766 3.437 ;
     RECT  27.936 3.379 57.222 3.451 ;
     RECT  57.96 2.489 133.002 3.451 ;
     RECT  12.096 3.437 12.258 3.569 ;
     RECT  135.72 3.371 141.894 3.569 ;
     RECT  142.704 2.831 142.722 3.641 ;
     RECT  27.936 3.451 133.002 3.685 ;
     RECT  133.956 3.437 134.658 3.685 ;
     RECT  27.936 3.685 134.658 3.839 ;
     RECT  26.532 3.335 27.054 3.991 ;
     RECT  27.936 3.839 48.258 3.991 ;
     RECT  26.532 3.991 48.258 4.109 ;
     RECT  48.996 3.839 134.658 4.109 ;
     RECT  26.532 4.109 45.897 4.115 ;
     RECT  135.72 3.569 141.786 4.117 ;
     RECT  52.02 4.109 87.354 4.168 ;
     RECT  13.068 3.437 25.758 4.261 ;
     RECT  26.532 4.115 27.054 4.261 ;
     RECT  88.092 4.109 134.658 4.261 ;
     RECT  135.576 4.117 141.786 4.261 ;
     RECT  54.936 4.168 87.354 4.289 ;
     RECT  48.996 4.109 51.297 4.445 ;
     RECT  28.368 4.115 45.897 4.451 ;
     RECT  88.092 4.261 141.786 4.493 ;
     RECT  13.068 4.261 27.054 4.507 ;
     RECT  88.092 4.493 134.226 4.541 ;
     RECT  12.744 4.507 27.054 4.559 ;
     RECT  135 4.493 141.786 4.649 ;
     RECT  88.092 4.541 132.297 4.685 ;
     RECT  58.5 4.289 87.354 4.733 ;
     RECT  139.572 4.649 141.786 4.801 ;
     RECT  69.66 4.733 87.354 4.843 ;
     RECT  88.092 4.685 108.414 4.843 ;
     RECT  69.66 4.843 108.414 4.877 ;
     RECT  88.02 4.877 108.414 4.919 ;
     RECT  94.176 4.919 103.734 4.955 ;
     RECT  88.092 4.919 93.258 4.973 ;
     RECT  94.176 4.955 103.698 4.973 ;
     RECT  139.572 4.801 141.858 5.071 ;
     RECT  69.66 4.877 87.246 5.117 ;
     RECT  72.252 5.117 87.246 5.189 ;
     RECT  109.332 4.685 132.297 5.189 ;
     RECT  72.252 5.189 85.842 5.225 ;
     RECT  72.252 5.225 85.77 5.495 ;
     RECT  112.608 5.189 132.297 5.501 ;
     RECT  123.156 5.501 132.297 5.531 ;
     RECT  104.58 4.919 108.414 21.091 ;
     RECT  82.188 5.495 85.77 21.115 ;
     RECT  86.616 5.189 87.246 21.115 ;
     RECT  82.188 21.115 87.246 21.127 ;
     RECT  88.236 4.973 93.258 21.127 ;
     RECT  69.66 5.117 71.514 21.361 ;
     RECT  72.252 5.495 81.378 21.361 ;
     RECT  104.58 21.091 108.486 21.361 ;
     RECT  109.332 5.189 111.69 21.361 ;
     RECT  123.156 5.531 127.278 21.469 ;
     RECT  58.5 4.733 68.886 21.505 ;
     RECT  69.66 21.361 81.378 21.505 ;
     RECT  82.188 21.127 93.258 21.505 ;
     RECT  94.176 4.973 99.897 21.541 ;
     RECT  100.836 4.973 103.698 21.541 ;
     RECT  104.58 21.361 111.798 21.541 ;
     RECT  112.608 5.501 121.878 21.541 ;
     RECT  128.088 5.531 132.297 21.541 ;
     RECT  139.572 5.071 141.93 21.541 ;
     RECT  58.5 21.505 93.258 21.631 ;
     RECT  94.032 21.541 99.897 21.631 ;
     RECT  100.692 21.541 103.698 21.631 ;
     RECT  104.544 21.541 121.878 21.631 ;
     RECT  122.616 21.469 127.278 21.631 ;
     RECT  58.5 21.631 99.897 21.667 ;
     RECT  100.692 21.631 103.77 21.667 ;
     RECT  104.544 21.631 127.278 21.667 ;
     RECT  128.016 21.541 132.297 21.667 ;
     RECT  139.572 21.541 141.966 22.009 ;
     RECT  143.028 21.469 143.046 22.009 ;
     RECT  13.068 4.559 27.054 22.081 ;
     RECT  58.5 21.667 132.297 22.315 ;
     RECT  133.02 4.541 134.226 22.315 ;
     RECT  28.368 4.451 29.697 22.441 ;
     RECT  30.456 4.451 45.897 22.441 ;
     RECT  46.728 4.109 47.97 22.441 ;
     RECT  28.368 22.441 47.97 22.477 ;
     RECT  12.996 22.081 27.054 22.549 ;
     RECT  50.004 4.445 51.297 22.549 ;
     RECT  52.02 4.168 54.198 22.549 ;
     RECT  12.996 22.549 27.594 22.585 ;
     RECT  28.368 22.477 48.222 22.585 ;
     RECT  50.004 22.549 54.198 22.585 ;
     RECT  54.936 4.289 57.69 22.585 ;
     RECT  58.5 22.315 134.226 22.585 ;
     RECT  135 4.649 138.798 22.585 ;
     RECT  139.572 22.009 143.046 22.585 ;
     RECT  12.996 22.585 48.222 22.621 ;
     RECT  50.004 22.585 134.226 22.621 ;
     RECT  135 22.585 143.046 22.621 ;
     RECT  48.996 4.445 49.23 22.711 ;
     RECT  50.004 22.621 143.046 22.711 ;
     RECT  12.492 22.621 48.222 22.783 ;
     RECT  48.996 22.711 143.046 22.783 ;
     RECT  12.492 22.783 143.046 23.395 ;
     RECT  2.415 2.413 2.697 23.507 ;
     RECT  7.815 2.413 8.097 23.507 ;
     RECT  11.952 23.395 143.046 23.549 ;
     RECT  12.6 23.549 143.046 23.585 ;
     RECT  12.6 23.585 45.774 23.621 ;
     RECT  46.548 23.585 143.046 23.621 ;
     RECT  28.44 23.621 35.154 23.657 ;
     RECT  12.708 23.621 27.666 23.729 ;
     RECT  35.892 23.621 45.774 23.729 ;
     RECT  46.548 23.621 55.494 23.729 ;
     RECT  2.415 23.507 2.505 23.777 ;
     RECT  7.815 23.507 7.905 23.777 ;
     RECT  48.096 23.729 53.874 23.819 ;
     RECT  39.168 23.729 44.154 23.885 ;
     RECT  44.928 23.729 45.774 23.927 ;
     RECT  12.708 23.729 25.254 23.933 ;
     RECT  25.992 23.729 27.666 23.933 ;
     RECT  28.44 23.657 33.858 23.933 ;
     RECT  37.512 23.729 38.322 23.933 ;
     RECT  40.788 23.885 44.154 23.933 ;
     RECT  44.928 23.927 45.702 23.933 ;
     RECT  48.168 23.819 53.874 23.933 ;
     RECT  54.684 23.729 55.494 23.933 ;
     RECT  56.268 23.621 98.694 23.933 ;
     RECT  99.468 23.621 141.498 23.933 ;
     RECT  48.168 23.933 51.462 24.461 ;
     RECT  21.96 23.933 24.39 24.509 ;
     RECT  28.44 23.933 32.634 24.509 ;
     RECT  46.548 23.729 47.322 24.509 ;
     RECT  48.168 24.461 50.706 24.509 ;
     RECT  54.684 23.933 54.738 24.509 ;
     RECT  131.904 23.933 138.546 24.557 ;
     RECT  142.272 23.621 143.046 24.557 ;
     RECT  131.904 24.557 135.558 25.085 ;
     RECT  136.44 24.557 138.546 25.085 ;
     RECT  12.708 23.933 20.358 25.133 ;
     RECT  30.132 24.509 32.634 25.133 ;
     RECT  33.408 23.933 33.858 25.133 ;
     RECT  57.96 23.933 58.842 25.133 ;
     RECT  139.284 23.933 140.058 25.133 ;
     RECT  131.904 25.085 134.118 25.169 ;
     RECT  21.96 24.509 22.77 25.805 ;
     RECT  25.992 23.933 26.874 25.805 ;
     RECT  28.44 24.509 29.394 25.805 ;
     RECT  31.752 25.133 32.634 25.805 ;
     RECT  35.892 23.729 36.666 25.805 ;
     RECT  39.168 23.885 39.942 25.805 ;
     RECT  42.48 23.933 43.29 25.805 ;
     RECT  52.2 23.933 53.082 25.805 ;
     RECT  133.344 25.169 134.118 25.805 ;
     RECT  59.616 23.933 98.694 25.819 ;
     RECT  99.468 23.933 131.13 25.819 ;
     RECT  34.704 23.657 35.154 25.861 ;
     RECT  42.48 25.805 42.498 25.861 ;
     RECT  44.136 23.933 44.154 25.861 ;
     RECT  50.688 24.509 50.706 25.861 ;
     RECT  56.268 23.933 56.286 25.861 ;
     RECT  136.44 25.085 137.106 25.861 ;
     RECT  13.176 25.133 20.358 25.882 ;
     RECT  13.176 25.882 13.248 25.889 ;
     RECT  13.266 25.882 13.608 25.889 ;
     RECT  13.626 25.882 14.004 25.889 ;
     RECT  14.022 25.882 14.4 25.889 ;
     RECT  14.418 25.882 14.868 25.889 ;
     RECT  14.886 25.882 15.264 25.889 ;
     RECT  15.282 25.882 15.624 25.889 ;
     RECT  15.642 25.882 16.128 25.889 ;
     RECT  16.146 25.882 16.488 25.889 ;
     RECT  16.506 25.882 16.884 25.889 ;
     RECT  16.902 25.882 17.28 25.889 ;
     RECT  17.298 25.882 17.748 25.889 ;
     RECT  17.766 25.882 18.144 25.889 ;
     RECT  18.162 25.882 18.504 25.889 ;
     RECT  18.522 25.882 18.9 25.889 ;
     RECT  18.918 25.882 19.368 25.889 ;
     RECT  19.386 25.882 19.764 25.889 ;
     RECT  19.782 25.882 20.34 25.889 ;
     RECT  34.272 25.861 35.154 25.882 ;
     RECT  34.29 25.882 35.028 25.889 ;
     RECT  35.046 25.882 35.154 25.889 ;
     RECT  40.788 23.933 41.562 25.882 ;
     RECT  40.806 25.882 41.544 25.889 ;
     RECT  136.296 25.861 137.106 25.882 ;
     RECT  136.314 25.882 137.088 25.889 ;
     RECT  13.266 25.889 13.608 25.901 ;
     RECT  13.626 25.889 14.004 25.901 ;
     RECT  14.022 25.889 14.4 25.901 ;
     RECT  14.418 25.889 14.868 25.901 ;
     RECT  14.886 25.889 15.264 25.901 ;
     RECT  15.282 25.889 15.624 25.901 ;
     RECT  15.642 25.889 16.128 25.901 ;
     RECT  16.146 25.889 16.488 25.901 ;
     RECT  16.506 25.889 16.884 25.901 ;
     RECT  16.902 25.889 17.28 25.901 ;
     RECT  17.298 25.889 17.748 25.901 ;
     RECT  17.766 25.889 18.144 25.901 ;
     RECT  18.162 25.889 18.504 25.901 ;
     RECT  18.522 25.889 18.9 25.901 ;
     RECT  18.918 25.889 19.368 25.901 ;
     RECT  19.386 25.889 19.764 25.901 ;
     RECT  19.782 25.889 20.34 25.901 ;
     RECT  59.616 25.819 131.13 25.882 ;
     RECT  59.634 25.882 60.264 25.901 ;
     RECT  60.282 25.882 60.66 25.901 ;
     RECT  60.678 25.882 61.056 25.901 ;
     RECT  61.074 25.882 61.416 25.901 ;
     RECT  61.434 25.882 61.92 25.901 ;
     RECT  61.938 25.882 62.28 25.901 ;
     RECT  62.298 25.882 62.676 25.901 ;
     RECT  62.694 25.882 63.072 25.901 ;
     RECT  63.09 25.882 63.54 25.901 ;
     RECT  63.558 25.882 63.936 25.901 ;
     RECT  63.954 25.882 64.296 25.901 ;
     RECT  64.314 25.882 64.692 25.901 ;
     RECT  64.71 25.882 65.16 25.901 ;
     RECT  65.178 25.882 65.556 25.901 ;
     RECT  65.574 25.882 65.952 25.901 ;
     RECT  65.97 25.882 66.42 25.901 ;
     RECT  66.438 25.882 66.816 25.901 ;
     RECT  66.834 25.882 67.176 25.901 ;
     RECT  67.194 25.882 67.572 25.901 ;
     RECT  67.59 25.882 68.04 25.901 ;
     RECT  68.058 25.882 68.436 25.901 ;
     RECT  68.454 25.882 68.832 25.901 ;
     RECT  68.85 25.882 69.192 25.901 ;
     RECT  69.21 25.882 69.696 25.901 ;
     RECT  69.714 25.882 70.056 25.901 ;
     RECT  70.074 25.882 70.452 25.901 ;
     RECT  70.47 25.882 70.848 25.901 ;
     RECT  70.866 25.882 71.316 25.901 ;
     RECT  71.334 25.882 71.712 25.901 ;
     RECT  71.73 25.882 72.072 25.901 ;
     RECT  72.09 25.882 72.468 25.901 ;
     RECT  72.486 25.882 72.936 25.901 ;
     RECT  72.954 25.882 73.332 25.901 ;
     RECT  73.35 25.882 73.728 25.901 ;
     RECT  73.746 25.882 74.196 25.901 ;
     RECT  74.214 25.882 74.592 25.901 ;
     RECT  74.61 25.882 74.952 25.901 ;
     RECT  74.97 25.882 75.348 25.901 ;
     RECT  75.366 25.882 75.816 25.901 ;
     RECT  75.834 25.882 76.212 25.901 ;
     RECT  76.23 25.882 76.608 25.901 ;
     RECT  76.626 25.882 76.968 25.901 ;
     RECT  76.986 25.882 77.472 25.901 ;
     RECT  77.49 25.882 77.832 25.901 ;
     RECT  77.85 25.882 78.228 25.901 ;
     RECT  78.246 25.882 78.624 25.901 ;
     RECT  78.642 25.882 79.092 25.901 ;
     RECT  79.11 25.882 79.488 25.901 ;
     RECT  79.506 25.882 79.848 25.901 ;
     RECT  79.866 25.882 80.352 25.901 ;
     RECT  80.37 25.882 80.712 25.901 ;
     RECT  80.73 25.882 81.108 25.901 ;
     RECT  81.126 25.882 81.504 25.901 ;
     RECT  81.522 25.882 81.972 25.901 ;
     RECT  81.99 25.882 82.368 25.901 ;
     RECT  82.386 25.882 82.728 25.901 ;
     RECT  82.746 25.882 83.124 25.901 ;
     RECT  83.142 25.882 83.592 25.901 ;
     RECT  83.61 25.882 83.988 25.901 ;
     RECT  84.006 25.882 84.384 25.901 ;
     RECT  84.402 25.882 84.744 25.901 ;
     RECT  84.762 25.882 85.248 25.901 ;
     RECT  85.266 25.882 85.608 25.901 ;
     RECT  85.626 25.882 86.004 25.901 ;
     RECT  86.022 25.882 86.472 25.901 ;
     RECT  86.49 25.882 86.868 25.901 ;
     RECT  86.886 25.882 87.264 25.901 ;
     RECT  87.282 25.882 87.624 25.901 ;
     RECT  87.642 25.882 88.128 25.901 ;
     RECT  88.146 25.882 88.488 25.901 ;
     RECT  88.506 25.882 88.884 25.901 ;
     RECT  88.902 25.882 89.28 25.901 ;
     RECT  89.298 25.882 89.748 25.901 ;
     RECT  89.766 25.882 90.144 25.901 ;
     RECT  90.162 25.882 90.504 25.901 ;
     RECT  90.522 25.882 90.9 25.901 ;
     RECT  90.918 25.882 91.368 25.901 ;
     RECT  91.386 25.882 91.764 25.901 ;
     RECT  91.782 25.882 92.16 25.901 ;
     RECT  92.178 25.882 92.52 25.901 ;
     RECT  92.538 25.882 93.024 25.901 ;
     RECT  93.042 25.882 93.384 25.901 ;
     RECT  93.402 25.882 93.78 25.901 ;
     RECT  93.798 25.882 94.248 25.901 ;
     RECT  94.266 25.882 94.644 25.901 ;
     RECT  94.662 25.882 95.04 25.901 ;
     RECT  95.058 25.882 95.4 25.901 ;
     RECT  95.418 25.882 95.904 25.901 ;
     RECT  95.922 25.882 96.264 25.901 ;
     RECT  96.282 25.882 96.66 25.901 ;
     RECT  96.678 25.882 97.056 25.901 ;
     RECT  97.074 25.882 97.524 25.901 ;
     RECT  97.542 25.882 97.92 25.901 ;
     RECT  97.938 25.882 98.28 25.901 ;
     RECT  98.298 25.882 98.676 25.901 ;
     RECT  98.694 25.882 99.144 25.901 ;
     RECT  99.162 25.882 99.54 25.901 ;
     RECT  99.558 25.882 99.936 25.901 ;
     RECT  99.954 25.882 100.404 25.901 ;
     RECT  100.422 25.882 100.8 25.901 ;
     RECT  100.818 25.882 101.16 25.901 ;
     RECT  101.178 25.882 101.556 25.901 ;
     RECT  101.574 25.882 102.024 25.901 ;
     RECT  102.042 25.882 102.42 25.901 ;
     RECT  102.438 25.882 102.816 25.901 ;
     RECT  102.834 25.882 103.176 25.901 ;
     RECT  103.194 25.882 103.68 25.901 ;
     RECT  103.698 25.882 104.04 25.901 ;
     RECT  104.058 25.882 104.436 25.901 ;
     RECT  104.454 25.882 104.832 25.901 ;
     RECT  104.85 25.882 105.3 25.901 ;
     RECT  105.318 25.882 105.696 25.901 ;
     RECT  105.714 25.882 106.056 25.901 ;
     RECT  106.074 25.882 106.56 25.901 ;
     RECT  106.578 25.882 106.92 25.901 ;
     RECT  106.938 25.882 107.316 25.901 ;
     RECT  107.334 25.882 107.712 25.901 ;
     RECT  107.73 25.882 108.18 25.901 ;
     RECT  108.198 25.882 108.576 25.901 ;
     RECT  108.594 25.882 108.936 25.901 ;
     RECT  108.954 25.882 109.332 25.901 ;
     RECT  109.35 25.882 109.8 25.901 ;
     RECT  109.818 25.882 110.196 25.901 ;
     RECT  110.214 25.882 110.592 25.901 ;
     RECT  110.61 25.882 110.952 25.901 ;
     RECT  110.97 25.882 111.456 25.901 ;
     RECT  111.474 25.882 111.816 25.901 ;
     RECT  111.834 25.882 112.212 25.901 ;
     RECT  112.23 25.882 112.608 25.901 ;
     RECT  112.626 25.882 113.076 25.901 ;
     RECT  113.094 25.882 113.472 25.901 ;
     RECT  113.49 25.882 113.832 25.901 ;
     RECT  113.85 25.882 114.336 25.901 ;
     RECT  114.354 25.882 114.696 25.901 ;
     RECT  114.714 25.882 115.092 25.901 ;
     RECT  115.11 25.882 115.488 25.901 ;
     RECT  115.506 25.882 115.956 25.901 ;
     RECT  115.974 25.882 116.352 25.901 ;
     RECT  116.37 25.882 116.712 25.901 ;
     RECT  116.73 25.882 117.108 25.901 ;
     RECT  117.126 25.882 117.576 25.901 ;
     RECT  117.594 25.882 117.972 25.901 ;
     RECT  117.99 25.882 118.368 25.901 ;
     RECT  118.386 25.882 118.728 25.901 ;
     RECT  118.746 25.882 119.232 25.901 ;
     RECT  119.25 25.882 119.592 25.901 ;
     RECT  119.61 25.882 119.988 25.901 ;
     RECT  120.006 25.882 120.456 25.901 ;
     RECT  120.474 25.882 120.852 25.901 ;
     RECT  120.87 25.882 121.248 25.901 ;
     RECT  121.266 25.882 121.608 25.901 ;
     RECT  121.626 25.882 122.112 25.901 ;
     RECT  122.13 25.882 122.472 25.901 ;
     RECT  122.49 25.882 122.868 25.901 ;
     RECT  122.886 25.882 123.264 25.901 ;
     RECT  123.282 25.882 123.732 25.901 ;
     RECT  123.75 25.882 124.128 25.901 ;
     RECT  124.146 25.882 124.488 25.901 ;
     RECT  124.506 25.882 124.884 25.901 ;
     RECT  124.902 25.882 125.352 25.901 ;
     RECT  125.37 25.882 125.748 25.901 ;
     RECT  125.766 25.882 126.144 25.901 ;
     RECT  126.162 25.882 126.612 25.901 ;
     RECT  126.63 25.882 127.008 25.901 ;
     RECT  127.026 25.882 127.368 25.901 ;
     RECT  127.386 25.882 127.764 25.901 ;
     RECT  127.782 25.882 128.232 25.901 ;
     RECT  128.25 25.882 128.628 25.901 ;
     RECT  128.646 25.882 129.024 25.901 ;
     RECT  129.042 25.882 129.384 25.901 ;
     RECT  129.402 25.882 129.888 25.901 ;
     RECT  129.906 25.882 130.248 25.901 ;
     RECT  130.266 25.882 130.644 25.901 ;
     RECT  130.662 25.882 131.112 25.901 ;
     RECT  131.904 25.169 132.57 25.882 ;
     RECT  131.922 25.882 132.552 25.901 ;
     RECT  134.856 25.085 135.558 25.882 ;
     RECT  134.874 25.882 135.54 25.901 ;
     RECT  137.844 25.085 138.546 25.882 ;
     RECT  137.862 25.882 138.528 25.901 ;
     RECT  140.832 23.933 141.498 25.882 ;
     RECT  140.85 25.882 141.48 25.901 ;
    LAYER M4 ;
     RECT  0.181 4.944 2.408 4.968 ;
     RECT  2.408 2.148 2.512 23.772 ;
     RECT  2.512 2.418 2.704 23.502 ;
     RECT  2.704 4.944 7.808 4.968 ;
     RECT  7.808 2.148 7.912 23.772 ;
     RECT  7.912 2.418 8.104 23.502 ;
     RECT  8.104 4.944 12.733 4.968 ;
     RECT  12.697 25.104 12.805 25.128 ;
     RECT  12.805 25.056 13.043 25.128 ;
     RECT  12.877 1.728 13.208 1.752 ;
     RECT  12.085 3.408 13.208 3.432 ;
     RECT  12.733 4.512 13.208 4.968 ;
     RECT  13.208 1.728 13.312 23.772 ;
     RECT  13.312 1.728 13.504 23.502 ;
     RECT  13.504 22.992 13.853 23.016 ;
     RECT  13.043 25.104 13.907 25.128 ;
     RECT  14.245 25.776 14.429 25.8 ;
     RECT  13.504 1.728 14.629 1.752 ;
     RECT  14.629 1.728 14.717 1.8 ;
     RECT  13.504 3.408 14.76 3.432 ;
     RECT  13.504 4.512 14.76 4.968 ;
     RECT  14.629 23.904 14.825 23.928 ;
     RECT  14.893 0.576 15.059 0.6 ;
     RECT  16.189 25.104 16.307 25.128 ;
     RECT  14.857 23.376 16.453 23.4 ;
     RECT  16.645 21.648 17.089 21.672 ;
     RECT  17.089 21.648 17.093 22.248 ;
     RECT  17.093 22.224 17.237 22.248 ;
     RECT  17.117 23.904 17.665 23.928 ;
     RECT  14.76 3.408 17.804 4.968 ;
     RECT  17.665 23.424 17.845 23.928 ;
     RECT  17.845 23.376 17.917 23.928 ;
     RECT  17.893 25.056 17.917 25.08 ;
     RECT  17.917 23.376 18.173 25.08 ;
     RECT  18.173 23.376 18.419 24.552 ;
     RECT  14.717 1.728 18.608 1.752 ;
     RECT  17.804 3.312 18.608 4.968 ;
     RECT  18.419 23.376 18.608 23.88 ;
     RECT  18.608 1.728 18.904 23.88 ;
     RECT  19.141 25.776 19.289 25.8 ;
     RECT  18.904 23.376 19.369 23.88 ;
     RECT  18.904 3.072 19.964 4.968 ;
     RECT  19.964 3.072 20.051 5.16 ;
     RECT  20.257 22.704 20.441 22.728 ;
     RECT  20.051 3.072 21.193 3.096 ;
     RECT  20.051 4.224 21.193 4.968 ;
     RECT  19.493 23.904 21.593 23.928 ;
     RECT  22.405 25.776 22.709 25.8 ;
     RECT  18.904 1.728 23.221 1.752 ;
     RECT  21.193 3.072 24.008 4.968 ;
     RECT  23.165 24.48 24.008 24.504 ;
     RECT  23.965 0.576 24.083 0.6 ;
     RECT  24.008 2.148 24.304 24.504 ;
     RECT  24.304 23.904 24.365 24.504 ;
     RECT  24.365 23.904 24.869 23.928 ;
     RECT  24.304 3.072 25.661 4.968 ;
     RECT  26.437 25.776 26.633 25.8 ;
     RECT  25.669 22.752 27.029 22.776 ;
     RECT  25.661 3.072 27.349 3.096 ;
     RECT  25.661 4.08 27.349 4.968 ;
     RECT  27.269 23.904 27.353 23.928 ;
     RECT  27.349 2.832 27.436 4.968 ;
     RECT  24.805 1.728 28.979 1.752 ;
     RECT  28.069 25.776 29.009 25.8 ;
     RECT  27.436 3.312 29.408 4.968 ;
     RECT  29.408 2.148 29.512 23.772 ;
     RECT  29.512 2.418 29.704 23.502 ;
     RECT  29.545 0.096 29.747 0.12 ;
     RECT  29.701 24.48 29.981 24.504 ;
     RECT  30.524 25.104 31.379 25.128 ;
     RECT  32.165 25.776 32.249 25.8 ;
     RECT  29.704 3.312 32.533 4.968 ;
     RECT  32.957 23.904 33.041 23.928 ;
     RECT  33.788 25.104 33.875 25.128 ;
     RECT  30.481 1.728 34.808 1.752 ;
     RECT  32.533 3.12 34.808 4.968 ;
     RECT  34.597 23.376 34.808 23.4 ;
     RECT  34.808 1.728 34.912 23.772 ;
     RECT  34.912 1.728 35.104 23.502 ;
     RECT  35.104 2.832 35.651 4.968 ;
     RECT  36.325 25.776 36.461 25.8 ;
     RECT  35.104 22.752 36.749 22.776 ;
     RECT  35.651 3.12 37.793 4.968 ;
     RECT  37.093 23.904 38.189 23.928 ;
     RECT  38.581 23.376 38.771 23.4 ;
     RECT  39.589 25.776 39.701 25.8 ;
     RECT  35.104 1.728 40.208 1.752 ;
     RECT  37.793 3.408 40.208 4.968 ;
     RECT  40.093 23.856 40.208 23.88 ;
     RECT  40.208 1.728 40.403 23.88 ;
     RECT  40.403 1.728 40.504 23.502 ;
     RECT  40.504 22.896 41.177 22.92 ;
     RECT  41.221 25.776 41.573 25.8 ;
     RECT  41.989 23.904 42.185 23.928 ;
     RECT  40.504 3.408 42.757 4.968 ;
     RECT  42.853 25.776 42.977 25.8 ;
     RECT  42.757 3.312 43.733 4.968 ;
     RECT  43.621 23.904 45.317 23.928 ;
     RECT  40.504 1.728 45.608 1.752 ;
     RECT  43.733 3.408 45.608 4.968 ;
     RECT  45.608 1.728 45.712 23.772 ;
     RECT  45.712 1.728 45.904 23.502 ;
     RECT  45.904 23.376 46.163 23.4 ;
     RECT  45.904 1.728 46.181 1.752 ;
     RECT  45.904 3.408 46.897 4.968 ;
     RECT  46.789 0.576 46.931 0.6 ;
     RECT  46.885 24.48 47.045 24.504 ;
     RECT  47.545 1.728 47.795 1.752 ;
     RECT  47.653 23.376 47.795 23.4 ;
     RECT  48.301 0.096 48.563 0.12 ;
     RECT  48.517 24.48 50.291 24.504 ;
     RECT  46.897 3.312 50.353 4.968 ;
     RECT  49.381 1.728 51.008 1.752 ;
     RECT  50.353 2.832 51.008 4.968 ;
     RECT  50.965 24.432 51.008 24.456 ;
     RECT  51.008 1.728 51.059 24.456 ;
     RECT  51.059 2.148 51.112 23.928 ;
     RECT  51.112 2.418 51.304 23.928 ;
     RECT  51.793 0.096 51.923 0.12 ;
     RECT  51.304 23.904 51.941 23.928 ;
     RECT  51.304 3.312 52.405 4.968 ;
     RECT  52.405 2.832 52.489 4.968 ;
     RECT  52.645 25.776 52.913 25.8 ;
     RECT  53.509 23.904 53.597 23.928 ;
     RECT  54.277 24.48 54.713 24.504 ;
     RECT  52.613 1.728 56.408 1.752 ;
     RECT  52.489 3.072 56.408 4.968 ;
     RECT  55.681 22.752 56.408 22.776 ;
     RECT  55.141 23.904 56.408 23.928 ;
     RECT  56.408 1.728 56.704 23.928 ;
     RECT  56.704 23.904 57.601 23.928 ;
     RECT  58.345 25.104 58.451 25.128 ;
     RECT  56.704 3.072 58.637 4.968 ;
     RECT  58.637 3.12 58.645 4.968 ;
     RECT  58.645 3.12 58.781 5.064 ;
     RECT  59.173 23.904 59.285 23.928 ;
     RECT  60.037 24.528 60.467 25.08 ;
     RECT  60.467 25.056 60.869 25.08 ;
     RECT  61.297 25.728 61.573 25.752 ;
     RECT  58.781 3.12 61.621 4.968 ;
     RECT  61.253 23.904 61.621 23.928 ;
     RECT  61.621 23.376 61.649 23.928 ;
     RECT  61.649 23.376 61.733 24.504 ;
     RECT  56.704 1.728 61.808 1.752 ;
     RECT  61.621 3.12 61.808 5.064 ;
     RECT  61.573 22.032 61.808 22.056 ;
     RECT  61.733 23.376 61.808 23.772 ;
     RECT  61.808 1.728 61.912 23.772 ;
     RECT  61.573 25.728 62.099 25.8 ;
     RECT  61.912 1.728 62.104 23.502 ;
     RECT  62.104 22.032 62.273 22.056 ;
     RECT  62.099 25.728 62.483 25.752 ;
     RECT  62.104 23.376 62.677 23.4 ;
     RECT  63.241 0.096 63.347 0.12 ;
     RECT  62.917 24.48 63.353 24.504 ;
     RECT  62.104 3.072 63.749 5.112 ;
     RECT  63.665 25.776 63.749 25.8 ;
     RECT  63.781 22.8 63.865 22.824 ;
     RECT  64.165 25.056 64.253 25.08 ;
     RECT  63.749 3.216 64.469 5.112 ;
     RECT  62.104 1.728 64.753 1.752 ;
     RECT  64.469 3.216 64.753 5.064 ;
     RECT  64.549 21.648 64.753 21.672 ;
     RECT  64.753 1.728 64.837 5.064 ;
     RECT  64.753 21.648 64.979 22.248 ;
     RECT  65.132 0.048 65.219 0.072 ;
     RECT  64.979 21.648 65.261 22.152 ;
     RECT  65.317 24.912 65.405 24.936 ;
     RECT  64.429 23.376 65.513 23.4 ;
     RECT  64.837 2.88 65.545 5.064 ;
     RECT  65.545 2.88 65.621 5.16 ;
     RECT  65.621 3.312 65.629 5.16 ;
     RECT  64.837 1.728 65.845 1.752 ;
     RECT  65.845 1.728 65.932 2.232 ;
     RECT  65.261 22.128 65.941 22.152 ;
     RECT  65.629 3.312 66.035 5.064 ;
     RECT  65.941 22.128 66.125 22.824 ;
     RECT  66.125 22.8 66.131 22.824 ;
     RECT  66.181 23.952 66.341 23.976 ;
     RECT  66.035 3.408 66.661 5.064 ;
     RECT  66.565 23.904 66.701 23.928 ;
     RECT  65.932 1.728 67.208 1.752 ;
     RECT  66.661 3.408 67.208 5.208 ;
     RECT  66.949 23.472 67.208 23.772 ;
     RECT  67.208 1.728 67.504 23.772 ;
     RECT  67.504 1.728 67.565 1.992 ;
     RECT  67.429 25.776 67.619 25.8 ;
     RECT  67.504 21.648 67.667 23.772 ;
     RECT  67.667 23.376 67.805 23.772 ;
     RECT  67.805 23.376 67.889 23.928 ;
     RECT  67.667 21.648 67.961 21.672 ;
     RECT  67.504 3.696 68.099 5.208 ;
     RECT  67.565 1.728 68.773 1.752 ;
     RECT  67.889 23.376 68.821 23.4 ;
     RECT  68.581 25.056 68.825 25.08 ;
     RECT  68.773 1.728 68.861 2.712 ;
     RECT  68.821 22.8 69.404 23.4 ;
     RECT  69.061 24.48 69.404 24.504 ;
     RECT  69.404 22.8 69.481 24.504 ;
     RECT  69.481 23.376 69.491 24.504 ;
     RECT  68.099 3.696 69.493 5.064 ;
     RECT  69.491 23.376 69.553 23.4 ;
     RECT  69.493 3.552 69.937 5.064 ;
     RECT  69.491 24.48 69.977 24.504 ;
     RECT  69.613 21.696 70.157 21.72 ;
     RECT  68.861 1.728 70.309 1.848 ;
     RECT  69.937 3.504 70.477 5.064 ;
     RECT  70.309 25.056 70.589 25.08 ;
     RECT  70.477 3.408 70.691 5.064 ;
     RECT  70.309 1.728 70.733 2.232 ;
     RECT  70.685 25.776 70.769 25.8 ;
     RECT  70.691 3.408 71.029 5.112 ;
     RECT  70.693 23.376 71.101 23.4 ;
     RECT  71.029 3.312 71.489 5.112 ;
     RECT  71.077 24.48 71.561 24.504 ;
     RECT  70.733 1.728 72.205 1.752 ;
     RECT  71.9 23.952 72.205 23.976 ;
     RECT  71.489 3.6 72.469 5.112 ;
     RECT  72.205 23.376 72.529 23.976 ;
     RECT  72.205 1.728 72.608 2.28 ;
     RECT  72.469 3.408 72.608 5.112 ;
     RECT  72.529 22.8 72.608 23.976 ;
     RECT  72.608 1.728 72.709 23.976 ;
     RECT  72.709 1.728 72.712 24.552 ;
     RECT  72.712 24.48 72.796 24.552 ;
     RECT  72.712 1.728 72.904 23.502 ;
     RECT  72.904 1.728 73.001 2.28 ;
     RECT  72.796 24.48 73.505 24.504 ;
     RECT  72.904 3.312 73.523 5.208 ;
     RECT  73.957 23.904 74.045 23.928 ;
     RECT  72.904 21.552 74.117 21.576 ;
     RECT  73.523 3.312 74.195 5.112 ;
     RECT  74.195 3.312 74.261 5.064 ;
     RECT  74.113 23.376 74.581 23.4 ;
     RECT  73.001 1.728 74.629 1.752 ;
     RECT  74.581 22.8 74.675 23.4 ;
     RECT  74.341 21.36 74.693 21.384 ;
     RECT  74.629 1.728 74.729 2.28 ;
     RECT  74.725 25.776 74.945 25.8 ;
     RECT  74.261 3.36 75.203 5.064 ;
     RECT  74.675 23.376 75.203 23.4 ;
     RECT  75.193 21.648 75.277 21.672 ;
     RECT  75.203 3.6 75.596 5.064 ;
     RECT  75.596 3.6 75.683 5.208 ;
     RECT  75.589 23.904 76.412 23.928 ;
     RECT  76.412 23.904 76.499 24.552 ;
     RECT  76.499 23.904 76.889 23.928 ;
     RECT  77.564 25.104 77.651 25.128 ;
     RECT  75.683 3.6 77.797 5.064 ;
     RECT  77.18 23.376 77.845 23.4 ;
     RECT  74.729 1.728 78.008 1.752 ;
     RECT  77.797 3.312 78.008 5.064 ;
     RECT  77.845 22.8 78.008 23.4 ;
     RECT  78.008 1.728 78.085 23.772 ;
     RECT  78.085 1.728 78.304 24.504 ;
     RECT  78.304 23.28 78.401 24.504 ;
     RECT  78.304 1.728 78.515 2.28 ;
     RECT  78.304 22.224 78.556 22.248 ;
     RECT  78.401 23.376 78.563 24.504 ;
     RECT  78.563 23.424 78.659 24.504 ;
     RECT  78.304 3.312 79.373 5.208 ;
     RECT  79.373 3.312 79.553 5.064 ;
     RECT  78.659 23.904 79.805 24.504 ;
     RECT  79.805 24.48 80.669 24.504 ;
     RECT  78.515 1.728 80.869 1.752 ;
     RECT  80.869 1.728 80.957 1.8 ;
     RECT  80.869 23.904 80.957 23.928 ;
     RECT  80.101 22.224 80.993 22.248 ;
     RECT  81.241 23.376 81.497 23.496 ;
     RECT  79.553 3.312 81.565 4.68 ;
     RECT  81.565 3.312 81.709 5.16 ;
     RECT  81.709 3.312 81.925 5.352 ;
     RECT  81.497 23.376 81.925 23.4 ;
     RECT  81.925 22.8 82.009 23.4 ;
     RECT  80.957 1.728 82.249 1.752 ;
     RECT  81.925 3.312 82.465 5.688 ;
     RECT  82.117 24.48 82.501 24.504 ;
     RECT  82.249 1.728 82.549 1.8 ;
     RECT  82.465 2.832 82.549 5.688 ;
     RECT  82.501 24.48 82.649 24.552 ;
     RECT  82.009 23.28 82.981 23.4 ;
     RECT  82.981 23.28 83.221 23.928 ;
     RECT  82.549 1.728 83.408 5.688 ;
     RECT  83.221 22.8 83.408 23.928 ;
     RECT  83.365 25.776 83.603 25.8 ;
     RECT  83.408 1.728 83.704 23.928 ;
     RECT  83.704 23.376 83.749 23.928 ;
     RECT  83.749 23.376 83.836 23.976 ;
     RECT  83.704 1.728 84.275 5.208 ;
     RECT  84.275 3.216 84.737 5.208 ;
     RECT  83.836 23.376 85.021 23.928 ;
     RECT  84.275 1.728 85.043 1.752 ;
     RECT  85.021 22.8 85.249 23.928 ;
     RECT  85.249 23.376 85.34 23.928 ;
     RECT  84.737 3.312 85.957 5.208 ;
     RECT  85.333 21.12 86.177 21.144 ;
     RECT  85.34 2.256 86.245 2.28 ;
     RECT  85.34 23.376 86.291 23.976 ;
     RECT  86.245 1.728 86.675 2.28 ;
     RECT  85.957 3.312 86.825 5.4 ;
     RECT  86.291 23.376 87.157 23.928 ;
     RECT  87.157 23.904 87.221 23.928 ;
     RECT  87.253 0.576 87.539 0.6 ;
     RECT  85.861 22.128 87.541 22.152 ;
     RECT  87.461 24.48 87.545 24.504 ;
     RECT  86.675 1.728 87.721 1.752 ;
     RECT  87.541 22.128 87.833 22.824 ;
     RECT  87.877 25.008 88.229 25.08 ;
     RECT  88.229 25.008 88.337 25.032 ;
     RECT  87.833 22.8 88.549 22.824 ;
     RECT  87.721 1.728 88.808 2.28 ;
     RECT  86.825 3.312 88.808 5.208 ;
     RECT  88.645 21.696 88.808 21.72 ;
     RECT  88.549 22.8 88.808 23.4 ;
     RECT  88.808 1.728 88.912 23.772 ;
     RECT  88.912 1.728 89.104 23.502 ;
     RECT  89.125 24.48 89.273 24.504 ;
     RECT  89.477 25.776 89.561 25.8 ;
     RECT  89.104 3.216 89.669 5.208 ;
     RECT  89.104 22.752 89.939 23.4 ;
     RECT  89.104 1.728 90.083 2.232 ;
     RECT  89.939 23.376 90.709 23.4 ;
     RECT  90.373 24.48 90.709 24.504 ;
     RECT  90.709 23.376 90.803 24.504 ;
     RECT  90.803 23.376 90.925 23.4 ;
     RECT  89.669 3.312 90.961 5.208 ;
     RECT  90.083 1.728 91.141 1.752 ;
     RECT  90.961 3.264 91.141 5.208 ;
     RECT  90.925 22.8 91.141 23.4 ;
     RECT  91.141 1.728 91.217 5.208 ;
     RECT  91.217 1.728 91.325 5.112 ;
     RECT  90.803 24.48 91.721 24.504 ;
     RECT  91.141 22.224 92.005 23.4 ;
     RECT  91.325 3.264 92.329 5.112 ;
     RECT  92.329 3.264 92.413 5.16 ;
     RECT  92.257 0.096 92.435 0.12 ;
     RECT  91.325 1.728 92.54 1.752 ;
     RECT  92.413 3.264 92.54 5.112 ;
     RECT  92.492 0.048 92.579 0.072 ;
     RECT  92.005 21.648 92.585 23.4 ;
     RECT  92.389 25.776 92.801 25.8 ;
     RECT  92.54 1.728 92.915 5.112 ;
     RECT  92.915 1.728 92.989 2.28 ;
     RECT  92.585 21.984 93.637 23.4 ;
     RECT  93.637 21.648 93.98 23.4 ;
     RECT  92.989 1.728 94.208 1.752 ;
     RECT  92.915 3.312 94.208 5.112 ;
     RECT  93.98 21.552 94.208 23.4 ;
     RECT  94.208 1.728 94.405 23.772 ;
     RECT  94.405 1.728 94.504 24.504 ;
     RECT  94.504 23.904 94.925 24.504 ;
     RECT  94.504 1.728 95.357 4.92 ;
     RECT  94.925 23.904 95.605 23.928 ;
     RECT  95.357 1.728 95.753 1.8 ;
     RECT  95.605 23.376 95.753 23.928 ;
     RECT  95.357 2.832 95.893 4.92 ;
     RECT  95.753 23.376 95.929 23.4 ;
     RECT  95.852 0.048 95.939 0.072 ;
     RECT  95.633 21.648 96.257 21.672 ;
     RECT  95.893 2.832 96.365 5.112 ;
     RECT  95.929 22.8 96.517 23.4 ;
     RECT  96.365 3.264 96.62 5.112 ;
     RECT  95.753 1.728 96.793 1.752 ;
     RECT  96.517 22.752 96.833 23.4 ;
     RECT  96.793 1.728 96.877 2.28 ;
     RECT  96.62 3.264 96.949 5.16 ;
     RECT  96.877 1.728 97.049 2.232 ;
     RECT  96.901 25.056 97.229 25.08 ;
     RECT  97.253 21.648 97.337 21.672 ;
     RECT  96.949 3.264 97.625 5.4 ;
     RECT  97.261 0.096 97.715 0.12 ;
     RECT  97.625 3.264 97.852 5.16 ;
     RECT  97.049 2.208 97.861 2.232 ;
     RECT  97.852 3.264 97.861 4.872 ;
     RECT  97.861 2.208 98.195 4.872 ;
     RECT  96.833 23.376 98.492 23.4 ;
     RECT  97.669 24.48 98.492 24.504 ;
     RECT  98.492 23.376 98.525 24.504 ;
     RECT  98.525 23.376 98.579 23.736 ;
     RECT  97.405 22.224 98.917 22.248 ;
     RECT  98.195 2.88 98.965 4.872 ;
     RECT  99.116 25.824 99.203 25.848 ;
     RECT  98.965 2.88 99.277 5.112 ;
     RECT  99.277 2.832 99.36 5.112 ;
     RECT  98.521 1.728 99.608 1.752 ;
     RECT  99.36 2.784 99.608 5.112 ;
     RECT  98.917 21.648 99.608 22.248 ;
     RECT  98.579 23.376 99.608 23.448 ;
     RECT  99.608 1.728 99.781 23.772 ;
     RECT  99.301 25.056 99.781 25.08 ;
     RECT  99.781 1.728 99.904 25.08 ;
     RECT  99.904 23.376 100.115 25.08 ;
     RECT  100.115 24.48 100.325 25.08 ;
     RECT  100.325 24.48 100.721 24.504 ;
     RECT  99.904 1.728 100.765 2.28 ;
     RECT  100.115 23.376 101.113 23.4 ;
     RECT  99.904 3.36 101.125 4.968 ;
     RECT  101.125 3.312 101.149 4.968 ;
     RECT  101.149 2.832 101.233 4.968 ;
     RECT  101.233 3.12 101.269 4.968 ;
     RECT  101.113 22.8 101.737 23.4 ;
     RECT  101.797 24.48 101.945 24.504 ;
     RECT  100.925 21.648 101.981 21.672 ;
     RECT  101.269 3.12 102.035 5.4 ;
     RECT  101.737 23.376 102.149 23.4 ;
     RECT  102.149 23.376 102.233 23.928 ;
     RECT  102.233 23.376 102.563 23.496 ;
     RECT  102.563 23.472 102.611 23.496 ;
     RECT  100.765 1.728 103.093 1.752 ;
     RECT  102.035 3.264 103.133 5.4 ;
     RECT  103.121 0.528 103.205 0.552 ;
     RECT  103.093 1.728 103.501 2.232 ;
     RECT  103.501 2.208 103.772 2.232 ;
     RECT  103.772 2.208 103.781 2.28 ;
     RECT  103.045 21.648 103.781 21.672 ;
     RECT  103.429 23.712 103.781 23.736 ;
     RECT  103.813 25.056 103.925 25.08 ;
     RECT  103.133 3.264 104.197 4.92 ;
     RECT  104.281 0.096 104.365 0.12 ;
     RECT  103.781 2.256 104.561 2.28 ;
     RECT  104.197 3.264 104.561 5.112 ;
     RECT  104.293 24.48 104.825 24.504 ;
     RECT  104.561 2.256 104.869 5.112 ;
     RECT  104.869 2.256 105.008 5.496 ;
     RECT  104.029 23.376 105.008 23.4 ;
     RECT  105.008 2.148 105.061 23.928 ;
     RECT  105.061 1.728 105.304 23.928 ;
     RECT  105.304 23.568 105.443 23.928 ;
     RECT  105.304 1.728 105.683 2.328 ;
     RECT  105.637 0.048 105.725 0.072 ;
     RECT  105.443 23.856 105.865 23.928 ;
     RECT  105.865 23.856 105.971 24.552 ;
     RECT  105.971 23.856 106.013 24.504 ;
     RECT  106.013 23.904 106.769 24.504 ;
     RECT  105.683 1.728 107.125 1.752 ;
     RECT  106.769 23.904 107.165 23.928 ;
     RECT  107.053 22.896 107.233 22.92 ;
     RECT  107.233 22.8 107.309 22.92 ;
     RECT  105.304 3.312 107.345 5.496 ;
     RECT  107.125 1.728 107.365 2.232 ;
     RECT  107.345 3.312 107.365 4.968 ;
     RECT  107.557 25.056 107.669 25.08 ;
     RECT  107.66 0.048 107.747 0.072 ;
     RECT  107.365 1.728 108.083 4.968 ;
     RECT  107.941 25.728 108.281 25.8 ;
     RECT  107.309 22.8 108.457 22.824 ;
     RECT  108.281 25.728 108.605 25.752 ;
     RECT  108.457 22.8 108.709 23.4 ;
     RECT  108.805 0.528 108.965 0.552 ;
     RECT  108.709 22.8 108.997 23.928 ;
     RECT  108.997 22.752 109.181 23.928 ;
     RECT  108.083 3.312 109.381 4.968 ;
     RECT  109.181 23.376 109.433 23.928 ;
     RECT  108.083 1.728 109.619 1.752 ;
     RECT  109.573 24.48 110.009 24.504 ;
     RECT  109.897 2.016 110.408 2.28 ;
     RECT  109.381 3.312 110.408 5.064 ;
     RECT  110.252 22.128 110.408 22.152 ;
     RECT  109.433 23.376 110.408 23.4 ;
     RECT  110.293 25.776 110.483 25.8 ;
     RECT  110.408 2.016 110.704 23.772 ;
     RECT  110.704 3.312 110.729 5.064 ;
     RECT  110.704 23.376 111.185 23.772 ;
     RECT  110.704 21.648 111.377 21.672 ;
     RECT  110.729 3.312 111.769 4.968 ;
     RECT  111.185 23.376 112.069 23.928 ;
     RECT  110.821 1.728 112.165 1.752 ;
     RECT  112.165 1.728 112.229 2.232 ;
     RECT  112.229 1.728 112.313 2.28 ;
     RECT  112.069 22.752 112.321 23.928 ;
     RECT  112.313 1.728 112.493 2.232 ;
     RECT  112.321 23.904 112.781 23.928 ;
     RECT  112.493 1.728 112.837 1.752 ;
     RECT  111.769 3.312 112.924 5.16 ;
     RECT  112.924 3.312 112.925 5.064 ;
     RECT  112.321 22.752 112.925 22.776 ;
     RECT  112.837 1.152 112.979 1.752 ;
     RECT  112.837 24.48 113.393 24.504 ;
     RECT  112.925 3.312 113.411 4.968 ;
     RECT  113.411 3.408 113.429 4.968 ;
     RECT  113.701 25.056 113.825 25.08 ;
     RECT  112.979 1.728 113.968 1.752 ;
     RECT  113.968 1.728 114.131 1.8 ;
     RECT  113.429 3.408 114.185 4.92 ;
     RECT  113.677 23.376 114.469 23.4 ;
     RECT  114.469 23.376 114.581 23.736 ;
     RECT  114.821 23.904 114.905 23.928 ;
     RECT  114.185 3.696 115.009 4.92 ;
     RECT  115.009 3.696 115.196 5.16 ;
     RECT  115.196 3.312 115.225 5.16 ;
     RECT  115.225 3.312 115.285 5.208 ;
     RECT  114.937 0.096 115.379 0.12 ;
     RECT  115.333 25.056 115.589 25.08 ;
     RECT  114.131 1.728 115.808 1.752 ;
     RECT  115.285 3.312 115.808 5.544 ;
     RECT  114.085 21.648 115.808 21.672 ;
     RECT  115.261 22.8 115.808 22.824 ;
     RECT  115.808 1.728 116.101 23.772 ;
     RECT  116.101 1.728 116.104 23.928 ;
     RECT  116.104 1.728 116.201 1.992 ;
     RECT  116.104 3.312 116.243 5.496 ;
     RECT  115.717 25.776 116.243 25.8 ;
     RECT  116.104 22.224 116.461 23.928 ;
     RECT  116.461 22.224 116.489 22.824 ;
     RECT  116.489 22.224 116.669 22.248 ;
     RECT  116.461 23.904 116.965 23.928 ;
     RECT  116.243 3.696 117.065 5.496 ;
     RECT  116.965 23.904 117.533 24.504 ;
     RECT  117.065 3.696 117.644 4.968 ;
     RECT  117.349 21.648 117.677 21.672 ;
     RECT  117.644 3.36 118.22 4.968 ;
     RECT  117.533 24.48 118.297 24.504 ;
     RECT  118.22 3.36 118.357 5.16 ;
     RECT  118.321 23.424 118.453 23.448 ;
     RECT  118.357 3.312 118.547 5.16 ;
     RECT  118.429 0.096 118.643 0.12 ;
     RECT  118.547 3.312 118.685 5.112 ;
     RECT  118.597 22.128 119.005 22.152 ;
     RECT  118.961 25.776 119.045 25.8 ;
     RECT  119.005 21.648 119.117 22.152 ;
     RECT  116.201 1.728 119.324 1.752 ;
     RECT  119.117 21.648 119.369 21.672 ;
     RECT  118.453 23.376 119.401 23.448 ;
     RECT  119.401 22.8 119.507 23.448 ;
     RECT  119.507 23.376 119.845 23.448 ;
     RECT  119.845 23.376 120.161 23.928 ;
     RECT  118.685 3.744 120.373 5.112 ;
     RECT  120.373 3.696 120.709 5.112 ;
     RECT  120.613 24.48 120.773 24.504 ;
     RECT  119.324 1.728 121.208 2.28 ;
     RECT  120.709 3.696 121.208 5.496 ;
     RECT  120.188 22.128 121.208 22.152 ;
     RECT  120.161 23.376 121.208 23.496 ;
     RECT  121.208 1.728 121.312 23.772 ;
     RECT  121.453 25.104 121.477 25.128 ;
     RECT  121.312 1.728 121.504 23.592 ;
     RECT  121.477 25.104 121.619 25.8 ;
     RECT  121.504 1.728 121.907 2.28 ;
     RECT  121.504 23.376 121.955 23.592 ;
     RECT  121.504 21.648 121.997 22.344 ;
     RECT  121.504 3.36 122.105 5.496 ;
     RECT  121.997 22.176 122.177 22.344 ;
     RECT  121.619 25.104 122.291 25.128 ;
     RECT  122.105 3.408 122.465 5.496 ;
     RECT  122.177 22.32 122.681 22.344 ;
     RECT  122.629 24.48 122.753 25.08 ;
     RECT  121.955 23.376 123.013 23.4 ;
     RECT  122.821 0.096 123.155 0.12 ;
     RECT  122.465 3.408 123.253 5.304 ;
     RECT  123.253 2.832 123.365 5.304 ;
     RECT  123.365 3.696 123.653 5.304 ;
     RECT  123.653 3.696 123.797 5.208 ;
     RECT  122.753 25.056 124.265 25.08 ;
     RECT  124.009 22.8 124.589 22.824 ;
     RECT  125.084 25.104 125.171 25.128 ;
     RECT  121.907 1.728 125.273 1.752 ;
     RECT  123.797 3.744 125.365 5.208 ;
     RECT  125.365 3.744 125.411 5.448 ;
     RECT  123.461 23.904 125.509 23.928 ;
     RECT  125.509 23.904 125.665 23.976 ;
     RECT  125.411 4.944 125.773 5.448 ;
     RECT  125.665 23.376 125.989 23.976 ;
     RECT  125.413 2.256 126.373 2.28 ;
     RECT  126.373 1.728 126.608 2.28 ;
     RECT  125.521 3.312 126.608 3.72 ;
     RECT  125.773 4.944 126.608 5.688 ;
     RECT  125.989 23.376 126.608 24.504 ;
     RECT  126.608 1.728 126.904 24.504 ;
     RECT  126.904 23.376 127.141 24.504 ;
     RECT  127.141 23.376 127.469 24.552 ;
     RECT  126.904 3.312 127.667 5.496 ;
     RECT  127.667 3.312 128.149 5.304 ;
     RECT  128.149 2.832 128.435 5.304 ;
     RECT  128.435 3.552 128.441 5.304 ;
     RECT  126.904 1.728 128.761 1.752 ;
     RECT  128.441 3.552 129.053 5.208 ;
     RECT  129.053 3.696 129.269 5.208 ;
     RECT  128.761 1.104 129.299 1.752 ;
     RECT  127.469 23.376 129.299 23.928 ;
     RECT  129.299 23.856 130.169 23.928 ;
     RECT  129.269 3.696 130.211 5.016 ;
     RECT  130.211 3.696 130.385 4.632 ;
     RECT  129.299 1.728 130.46 1.752 ;
     RECT  130.46 1.728 130.547 2.28 ;
     RECT  130.46 21.648 130.547 21.672 ;
     RECT  130.385 3.84 131.276 4.632 ;
     RECT  130.169 23.904 131.537 23.928 ;
     RECT  130.547 1.728 132.008 1.752 ;
     RECT  131.276 3.84 132.008 4.872 ;
     RECT  132.008 1.728 132.304 23.772 ;
     RECT  132.229 25.056 132.581 25.08 ;
     RECT  132.997 23.904 133.121 23.928 ;
     RECT  133.669 25.776 133.877 25.8 ;
     RECT  132.304 3.84 134.093 4.536 ;
     RECT  134.093 3.84 134.485 4.488 ;
     RECT  134.485 3.408 134.489 4.488 ;
     RECT  134.437 25.056 134.525 25.08 ;
     RECT  134.489 3.408 134.737 4.392 ;
     RECT  135.205 23.904 135.605 23.928 ;
     RECT  134.737 3.312 135.781 4.392 ;
     RECT  135.932 24.528 136.019 24.552 ;
     RECT  136.645 23.904 136.793 23.928 ;
     RECT  132.304 1.728 137.408 1.752 ;
     RECT  135.781 3.312 137.408 4.536 ;
     RECT  137.365 25.056 137.459 25.08 ;
     RECT  137.408 1.728 137.512 23.772 ;
     RECT  137.512 1.728 137.704 23.502 ;
     RECT  138.181 25.776 138.341 25.8 ;
     RECT  137.704 3.312 138.515 4.584 ;
     RECT  138.515 3.84 138.697 4.584 ;
     RECT  138.949 23.904 139.097 23.928 ;
     RECT  138.697 3.84 139.597 4.632 ;
     RECT  139.453 25.104 139.667 25.128 ;
     RECT  139.597 3.408 139.745 4.632 ;
     RECT  139.745 3.84 140.821 4.632 ;
     RECT  140.821 3.792 140.933 4.632 ;
     RECT  140.389 23.904 141.221 23.928 ;
     RECT  140.933 3.792 141.437 3.816 ;
     RECT  137.704 1.728 141.977 1.752 ;
     RECT  141.925 21.648 142.012 21.672 ;
     RECT  142.652 0.528 142.739 0.552 ;
     RECT  142.513 24.528 142.739 24.552 ;
    LAYER M5 ;
     RECT  13.032 0.016 13.392 0.084 ;
     RECT  13.416 0.016 13.872 0.084 ;
     RECT  13.896 0.016 14.256 0.084 ;
     RECT  14.28 0.016 14.64 0.084 ;
     RECT  14.664 0.016 15.024 0.084 ;
     RECT  15.048 0.016 15.504 0.084 ;
     RECT  15.528 0.016 15.888 0.084 ;
     RECT  15.912 0.016 16.272 0.084 ;
     RECT  16.296 0.016 16.656 0.084 ;
     RECT  16.68 0.016 17.136 0.084 ;
     RECT  17.16 0.016 17.52 0.084 ;
     RECT  17.544 0.016 17.904 0.084 ;
     RECT  17.928 0.016 18.384 0.084 ;
     RECT  18.408 0.016 18.768 0.084 ;
     RECT  18.792 0.016 19.152 0.084 ;
     RECT  19.176 0.016 19.536 0.084 ;
     RECT  19.56 0.016 20.016 0.084 ;
     RECT  20.04 0.016 20.688 0.084 ;
     RECT  20.712 0.016 21.552 0.084 ;
     RECT  21.576 0.016 22.416 0.084 ;
     RECT  22.44 0.016 23.184 0.084 ;
     RECT  23.208 0.016 24.048 0.084 ;
     RECT  24.072 0.016 24.816 0.084 ;
     RECT  24.84 0.016 25.68 0.084 ;
     RECT  25.704 0.016 26.448 0.084 ;
     RECT  26.472 0.016 27.312 0.084 ;
     RECT  27.336 0.016 28.08 0.084 ;
     RECT  28.104 0.016 28.944 0.084 ;
     RECT  28.968 0.016 29.712 0.084 ;
     RECT  29.736 0.016 30.576 0.084 ;
     RECT  30.6 0.016 31.344 0.084 ;
     RECT  31.368 0.016 32.208 0.084 ;
     RECT  32.232 0.016 32.976 0.084 ;
     RECT  33 0.016 33.84 0.084 ;
     RECT  33.864 0.016 34.608 0.084 ;
     RECT  34.632 0.016 35.472 0.084 ;
     RECT  35.496 0.016 36.336 0.084 ;
     RECT  36.36 0.016 37.104 0.084 ;
     RECT  37.128 0.016 37.968 0.084 ;
     RECT  37.992 0.016 38.736 0.084 ;
     RECT  38.76 0.016 39.6 0.084 ;
     RECT  39.624 0.016 40.368 0.084 ;
     RECT  40.392 0.016 41.232 0.084 ;
     RECT  41.256 0.016 42 0.084 ;
     RECT  42.024 0.016 42.864 0.084 ;
     RECT  42.888 0.016 43.632 0.084 ;
     RECT  43.656 0.016 44.496 0.084 ;
     RECT  44.52 0.016 45.264 0.084 ;
     RECT  45.288 0.016 46.128 0.084 ;
     RECT  46.152 0.016 46.896 0.084 ;
     RECT  46.92 0.016 47.76 0.084 ;
     RECT  47.784 0.016 48.528 0.084 ;
     RECT  48.552 0.016 49.392 0.084 ;
     RECT  49.416 0.016 50.256 0.084 ;
     RECT  50.28 0.016 51.024 0.084 ;
     RECT  51.048 0.016 51.888 0.084 ;
     RECT  51.912 0.016 52.656 0.084 ;
     RECT  52.68 0.016 53.52 0.084 ;
     RECT  53.544 0.016 54.288 0.084 ;
     RECT  54.312 0.016 55.152 0.084 ;
     RECT  55.176 0.016 55.92 0.084 ;
     RECT  55.944 0.016 56.784 0.084 ;
     RECT  56.808 0.016 57.552 0.084 ;
     RECT  57.576 0.016 58.416 0.084 ;
     RECT  58.44 0.016 59.184 0.084 ;
     RECT  59.208 0.016 60.048 0.084 ;
     RECT  60.072 0.016 60.432 0.084 ;
     RECT  60.456 0.016 60.816 0.084 ;
     RECT  60.84 0.016 61.296 0.084 ;
     RECT  61.32 0.016 61.68 0.084 ;
     RECT  61.704 0.016 62.064 0.084 ;
     RECT  62.088 0.016 62.448 0.084 ;
     RECT  62.472 0.016 62.928 0.084 ;
     RECT  62.952 0.016 63.312 0.084 ;
     RECT  63.336 0.016 63.696 0.084 ;
     RECT  63.72 0.016 64.176 0.084 ;
     RECT  64.2 0.016 64.56 0.084 ;
     RECT  64.584 0.016 64.944 0.084 ;
     RECT  64.968 0.016 65.328 0.084 ;
     RECT  65.352 0.016 65.808 0.084 ;
     RECT  65.832 0.016 66.192 0.084 ;
     RECT  66.216 0.016 66.576 0.084 ;
     RECT  66.6 0.016 66.96 0.084 ;
     RECT  66.984 0.016 67.44 0.084 ;
     RECT  67.464 0.016 67.824 0.084 ;
     RECT  67.848 0.016 68.208 0.084 ;
     RECT  68.232 0.016 68.592 0.084 ;
     RECT  68.616 0.016 69.072 0.084 ;
     RECT  69.096 0.016 69.456 0.084 ;
     RECT  69.48 0.016 69.84 0.084 ;
     RECT  69.864 0.016 70.32 0.084 ;
     RECT  70.344 0.016 70.704 0.084 ;
     RECT  70.728 0.016 71.088 0.084 ;
     RECT  71.112 0.016 71.472 0.084 ;
     RECT  71.496 0.016 71.952 0.084 ;
     RECT  71.976 0.016 72.336 0.084 ;
     RECT  72.36 0.016 72.72 0.084 ;
     RECT  72.744 0.016 73.104 0.084 ;
     RECT  73.128 0.016 73.584 0.084 ;
     RECT  73.608 0.016 73.968 0.084 ;
     RECT  73.992 0.016 74.352 0.084 ;
     RECT  74.376 0.016 74.736 0.084 ;
     RECT  74.76 0.016 75.216 0.084 ;
     RECT  75.24 0.016 75.6 0.084 ;
     RECT  75.624 0.016 75.984 0.084 ;
     RECT  76.008 0.016 76.464 0.084 ;
     RECT  76.488 0.016 76.848 0.084 ;
     RECT  76.872 0.016 77.232 0.084 ;
     RECT  77.256 0.016 77.616 0.084 ;
     RECT  77.64 0.016 78.096 0.084 ;
     RECT  78.12 0.016 78.48 0.084 ;
     RECT  78.504 0.016 78.864 0.084 ;
     RECT  78.888 0.016 79.248 0.084 ;
     RECT  79.272 0.016 79.728 0.084 ;
     RECT  79.752 0.016 80.112 0.084 ;
     RECT  80.136 0.016 80.496 0.084 ;
     RECT  80.52 0.016 80.88 0.084 ;
     RECT  80.904 0.016 81.36 0.084 ;
     RECT  81.384 0.016 81.744 0.084 ;
     RECT  81.768 0.016 82.128 0.084 ;
     RECT  82.152 0.016 82.512 0.084 ;
     RECT  82.536 0.016 82.992 0.084 ;
     RECT  83.016 0.016 83.376 0.084 ;
     RECT  83.4 0.016 83.76 0.084 ;
     RECT  83.784 0.016 84.24 0.084 ;
     RECT  84.264 0.016 84.624 0.084 ;
     RECT  84.648 0.016 85.008 0.084 ;
     RECT  85.032 0.016 85.392 0.084 ;
     RECT  85.416 0.016 85.872 0.084 ;
     RECT  85.896 0.016 86.256 0.084 ;
     RECT  86.28 0.016 86.64 0.084 ;
     RECT  86.664 0.016 87.024 0.084 ;
     RECT  87.048 0.016 87.504 0.084 ;
     RECT  87.528 0.016 87.888 0.084 ;
     RECT  87.912 0.016 88.272 0.084 ;
     RECT  88.296 0.016 88.656 0.084 ;
     RECT  88.68 0.016 89.136 0.084 ;
     RECT  89.16 0.016 89.52 0.084 ;
     RECT  89.544 0.016 89.904 0.084 ;
     RECT  89.928 0.016 90.384 0.084 ;
     RECT  90.408 0.016 90.768 0.084 ;
     RECT  90.792 0.016 91.152 0.084 ;
     RECT  91.176 0.016 91.536 0.084 ;
     RECT  91.56 0.016 92.016 0.084 ;
     RECT  92.04 0.016 92.4 0.084 ;
     RECT  92.424 0.016 92.784 0.084 ;
     RECT  92.808 0.016 93.168 0.084 ;
     RECT  93.192 0.016 93.648 0.084 ;
     RECT  93.672 0.016 94.032 0.084 ;
     RECT  94.056 0.016 94.416 0.084 ;
     RECT  94.44 0.016 94.8 0.084 ;
     RECT  94.824 0.016 95.28 0.084 ;
     RECT  95.304 0.016 95.664 0.084 ;
     RECT  95.688 0.016 96.048 0.084 ;
     RECT  96.072 0.016 96.528 0.084 ;
     RECT  96.552 0.016 96.912 0.084 ;
     RECT  96.936 0.016 97.296 0.084 ;
     RECT  97.32 0.016 97.68 0.084 ;
     RECT  97.704 0.016 98.16 0.084 ;
     RECT  98.184 0.016 98.544 0.084 ;
     RECT  98.568 0.016 98.928 0.084 ;
     RECT  98.952 0.016 99.312 0.084 ;
     RECT  99.336 0.016 99.792 0.084 ;
     RECT  99.816 0.016 100.176 0.084 ;
     RECT  100.2 0.016 100.56 0.084 ;
     RECT  100.584 0.016 100.944 0.084 ;
     RECT  100.968 0.016 101.424 0.084 ;
     RECT  101.448 0.016 101.808 0.084 ;
     RECT  101.832 0.016 102.192 0.084 ;
     RECT  102.216 0.016 102.576 0.084 ;
     RECT  102.6 0.016 103.056 0.084 ;
     RECT  103.08 0.016 103.44 0.084 ;
     RECT  103.464 0.016 103.824 0.084 ;
     RECT  103.848 0.016 104.304 0.084 ;
     RECT  104.328 0.016 104.688 0.084 ;
     RECT  104.712 0.016 105.072 0.084 ;
     RECT  105.096 0.016 105.456 0.084 ;
     RECT  105.48 0.016 105.936 0.084 ;
     RECT  105.96 0.016 106.32 0.084 ;
     RECT  106.344 0.016 106.704 0.084 ;
     RECT  106.728 0.016 107.088 0.084 ;
     RECT  107.112 0.016 107.568 0.084 ;
     RECT  107.592 0.016 107.952 0.084 ;
     RECT  107.976 0.016 108.336 0.084 ;
     RECT  108.36 0.016 108.72 0.084 ;
     RECT  108.744 0.016 109.2 0.084 ;
     RECT  109.224 0.016 109.584 0.084 ;
     RECT  109.608 0.016 109.968 0.084 ;
     RECT  109.992 0.016 110.448 0.084 ;
     RECT  110.472 0.016 110.832 0.084 ;
     RECT  110.856 0.016 111.216 0.084 ;
     RECT  111.24 0.016 111.6 0.084 ;
     RECT  111.624 0.016 112.08 0.084 ;
     RECT  112.104 0.016 112.464 0.084 ;
     RECT  112.488 0.016 112.848 0.084 ;
     RECT  112.872 0.016 113.232 0.084 ;
     RECT  113.256 0.016 113.712 0.084 ;
     RECT  113.736 0.016 114.096 0.084 ;
     RECT  114.12 0.016 114.48 0.084 ;
     RECT  114.504 0.016 114.864 0.084 ;
     RECT  114.888 0.016 115.344 0.084 ;
     RECT  115.368 0.016 115.728 0.084 ;
     RECT  115.752 0.016 116.112 0.084 ;
     RECT  116.136 0.016 116.592 0.084 ;
     RECT  116.616 0.016 116.976 0.084 ;
     RECT  117 0.016 117.36 0.084 ;
     RECT  117.384 0.016 117.744 0.084 ;
     RECT  117.768 0.016 118.224 0.084 ;
     RECT  118.248 0.016 118.608 0.084 ;
     RECT  118.632 0.016 118.992 0.084 ;
     RECT  119.016 0.016 119.376 0.084 ;
     RECT  119.4 0.016 119.856 0.084 ;
     RECT  119.88 0.016 120.24 0.084 ;
     RECT  120.264 0.016 120.624 0.084 ;
     RECT  120.648 0.016 121.008 0.084 ;
     RECT  121.032 0.016 121.488 0.084 ;
     RECT  121.512 0.016 121.872 0.084 ;
     RECT  121.896 0.016 122.256 0.084 ;
     RECT  122.28 0.016 122.64 0.084 ;
     RECT  122.664 0.016 123.12 0.084 ;
     RECT  123.144 0.016 123.504 0.084 ;
     RECT  123.528 0.016 123.888 0.084 ;
     RECT  123.912 0.016 124.368 0.084 ;
     RECT  124.392 0.016 124.752 0.084 ;
     RECT  124.776 0.016 125.136 0.084 ;
     RECT  125.16 0.016 125.52 0.084 ;
     RECT  125.544 0.016 126 0.084 ;
     RECT  126.024 0.016 126.384 0.084 ;
     RECT  126.408 0.016 126.768 0.084 ;
     RECT  126.792 0.016 127.152 0.084 ;
     RECT  127.176 0.016 127.632 0.084 ;
     RECT  127.656 0.016 128.016 0.084 ;
     RECT  128.04 0.016 128.4 0.084 ;
     RECT  128.424 0.016 128.784 0.084 ;
     RECT  128.808 0.016 129.264 0.084 ;
     RECT  129.288 0.016 129.648 0.084 ;
     RECT  129.672 0.016 130.032 0.084 ;
     RECT  130.056 0.016 130.512 0.084 ;
     RECT  130.536 0.016 130.896 0.084 ;
     RECT  130.92 0.016 131.472 0.084 ;
     RECT  131.496 0.016 132.24 0.084 ;
     RECT  132.264 0.016 133.008 0.084 ;
     RECT  133.032 0.016 133.68 0.084 ;
     RECT  133.704 0.016 134.448 0.084 ;
     RECT  134.472 0.016 135.216 0.084 ;
     RECT  135.24 0.016 135.984 0.084 ;
     RECT  136.008 0.016 136.656 0.084 ;
     RECT  136.68 0.016 137.424 0.084 ;
     RECT  137.448 0.016 138.192 0.084 ;
     RECT  138.216 0.016 138.96 0.084 ;
     RECT  138.984 0.016 139.632 0.084 ;
     RECT  139.656 0.016 140.4 0.084 ;
     RECT  140.424 0.016 141.168 0.084 ;
     RECT  141.192 0.016 141.936 0.084 ;
     RECT  141.96 0.016 142.704 0.084 ;
     RECT  13.008 0.084 142.728 0.131 ;
     RECT  52.656 0.131 142.728 0.563 ;
     RECT  13.008 0.131 28.968 0.611 ;
     RECT  30.576 0.131 47.784 0.611 ;
     RECT  13.008 0.611 23.208 1.763 ;
     RECT  24.816 0.611 28.968 1.763 ;
     RECT  30.576 0.611 46.152 1.763 ;
     RECT  47.76 0.611 47.784 1.763 ;
     RECT  49.392 0.131 51.048 1.763 ;
     RECT  52.656 0.563 141.96 1.763 ;
     RECT  14.64 1.763 14.664 1.811 ;
     RECT  80.88 1.763 80.904 1.811 ;
     RECT  82.512 1.763 84.264 1.811 ;
     RECT  94.2 1.763 98.184 1.811 ;
     RECT  114.096 1.763 114.12 1.811 ;
     RECT  68.784 1.763 70.344 1.859 ;
     RECT  115.8 1.763 116.136 2.003 ;
     RECT  51 1.763 51.048 2.137 ;
     RECT  2.4 2.137 2.52 2.151 ;
     RECT  7.8 2.137 7.92 2.151 ;
     RECT  29.4 2.137 29.52 2.151 ;
     RECT  51 2.137 51.12 2.151 ;
     RECT  72.336 1.763 72.912 2.291 ;
     RECT  78 1.763 78.504 2.291 ;
     RECT  85.392 1.763 86.664 2.291 ;
     RECT  95.904 1.811 98.184 2.291 ;
     RECT  109.968 1.763 110.712 2.291 ;
     RECT  119.376 1.763 121.896 2.291 ;
     RECT  125.52 1.763 126.912 2.291 ;
     RECT  130.512 1.763 130.536 2.291 ;
     RECT  102.576 1.763 105.672 2.339 ;
     RECT  99.6 1.763 100.728 2.773 ;
     RECT  34.8 1.763 35.112 2.821 ;
     RECT  51 2.151 51.312 2.821 ;
     RECT  82.56 1.811 84.264 2.821 ;
     RECT  99.408 2.773 100.728 2.821 ;
     RECT  128.4 1.763 128.424 2.867 ;
     RECT  27.36 2.821 27.384 3.061 ;
     RECT  99.312 2.821 101.208 3.109 ;
     RECT  102.576 2.339 105.48 3.109 ;
     RECT  34.8 2.821 35.64 3.155 ;
     RECT  82.512 2.821 84.264 3.205 ;
     RECT  94.2 1.811 94.92 3.205 ;
     RECT  95.904 2.291 98.088 3.205 ;
     RECT  94.2 3.205 98.088 3.253 ;
     RECT  99.312 3.109 105.48 3.253 ;
     RECT  18.6 1.763 18.912 3.301 ;
     RECT  61.8 1.763 62.112 3.301 ;
     RECT  64.8 1.763 66.216 3.301 ;
     RECT  70.32 1.859 70.344 3.301 ;
     RECT  78 2.291 78.312 3.301 ;
     RECT  87.744 1.763 91.176 3.301 ;
     RECT  92.544 1.763 92.952 3.301 ;
     RECT  94.2 3.253 105.48 3.301 ;
     RECT  107.136 1.763 108.84 3.301 ;
     RECT  110.4 2.291 110.712 3.301 ;
     RECT  115.8 2.003 116.112 3.301 ;
     RECT  126.6 2.291 126.912 3.301 ;
     RECT  137.4 1.763 137.712 3.301 ;
     RECT  26.784 3.061 27.384 3.347 ;
     RECT  50.4 2.821 51.312 3.347 ;
     RECT  61.68 3.301 62.112 3.349 ;
     RECT  74.64 1.763 74.664 3.349 ;
     RECT  82.512 3.205 84.36 3.349 ;
     RECT  87.744 3.301 92.952 3.349 ;
     RECT  94.08 3.301 105.48 3.349 ;
     RECT  118.368 3.301 118.392 3.349 ;
     RECT  121.2 2.291 121.512 3.349 ;
     RECT  81.984 3.349 84.36 3.397 ;
     RECT  87.744 3.349 105.48 3.397 ;
     RECT  113.376 3.301 113.4 3.397 ;
     RECT  126.6 3.301 127.368 3.397 ;
     RECT  74.064 3.349 75.192 3.443 ;
     RECT  112.08 1.763 112.296 3.443 ;
     RECT  112.176 3.443 112.2 3.491 ;
     RECT  87.552 3.397 105.48 3.539 ;
     RECT  68.784 1.859 68.808 3.541 ;
     RECT  70.32 3.301 71.064 3.541 ;
     RECT  77.808 3.301 78.312 3.589 ;
     RECT  81.984 3.397 84.936 3.733 ;
     RECT  86.016 2.291 86.04 3.733 ;
     RECT  106.512 3.301 108.984 3.733 ;
     RECT  113.376 3.397 113.736 3.733 ;
     RECT  115.248 3.301 116.232 3.733 ;
     RECT  117.696 3.349 118.392 3.733 ;
     RECT  121.2 3.349 121.992 3.733 ;
     RECT  106.512 3.733 109.32 3.781 ;
     RECT  110.4 3.301 110.808 3.781 ;
     RECT  68.784 3.541 71.064 3.829 ;
     RECT  132 1.763 132.312 3.829 ;
     RECT  64.656 3.301 66.216 3.875 ;
     RECT  20.784 3.061 20.808 3.877 ;
     RECT  106.512 3.781 110.808 3.877 ;
     RECT  121.2 3.733 122.808 3.877 ;
     RECT  67.2 1.763 67.512 3.925 ;
     RECT  68.784 3.829 71.112 3.925 ;
     RECT  72.432 2.291 72.912 3.925 ;
     RECT  117.696 3.733 118.488 3.925 ;
     RECT  119.472 3.877 119.496 3.925 ;
     RECT  134.496 3.397 134.52 3.971 ;
     RECT  75.168 3.443 75.192 3.973 ;
     RECT  36.96 3.109 36.984 4.019 ;
     RECT  50.688 3.347 51.312 4.019 ;
     RECT  52.416 2.821 52.44 4.019 ;
     RECT  103.632 3.539 105.48 4.019 ;
     RECT  106.512 3.877 110.952 4.067 ;
     RECT  14.832 3.973 14.856 4.115 ;
     RECT  125.712 3.397 127.368 4.117 ;
     RECT  117.696 3.925 119.496 4.165 ;
     RECT  125.376 4.117 127.368 4.261 ;
     RECT  20.016 3.877 20.808 4.403 ;
     RECT  76.944 3.589 78.312 4.453 ;
     RECT  121.2 3.877 123 4.453 ;
     RECT  17.856 3.301 18.912 4.501 ;
     RECT  20.016 4.403 20.04 4.501 ;
     RECT  63.504 3.877 63.528 4.501 ;
     RECT  64.656 3.875 66.12 4.501 ;
     RECT  74.064 3.443 74.088 4.501 ;
     RECT  75.168 3.973 75.672 4.501 ;
     RECT  76.944 4.453 78.552 4.501 ;
     RECT  117.696 4.165 119.976 4.501 ;
     RECT  121.104 4.453 123 4.501 ;
     RECT  61.536 3.349 62.112 4.595 ;
     RECT  67.2 3.925 71.112 4.595 ;
     RECT  108.528 4.067 110.952 4.595 ;
     RECT  137.4 3.301 138.504 4.595 ;
     RECT  26.784 3.347 26.808 4.643 ;
     RECT  106.512 4.067 107.4 4.643 ;
     RECT  70.512 4.595 71.112 4.739 ;
     RECT  61.632 4.595 62.112 4.741 ;
     RECT  72.24 3.925 72.912 4.837 ;
     RECT  74.064 4.501 75.672 4.837 ;
     RECT  81.264 3.733 86.424 4.837 ;
     RECT  87.552 3.539 102.216 4.837 ;
     RECT  112.272 4.501 112.296 4.837 ;
     RECT  63.504 4.501 66.12 4.883 ;
     RECT  70.704 4.739 71.112 4.883 ;
     RECT  81.264 4.837 102.216 4.883 ;
     RECT  131.328 3.829 132.312 4.883 ;
     RECT  110.4 4.595 110.952 4.885 ;
     RECT  112.128 4.837 112.296 4.885 ;
     RECT  76.944 4.501 78.648 4.979 ;
     RECT  117.696 4.501 123 4.979 ;
     RECT  130.176 3.733 130.2 5.027 ;
     RECT  110.4 4.885 112.296 5.029 ;
     RECT  113.376 3.733 116.424 5.029 ;
     RECT  58.656 3.397 58.68 5.075 ;
     RECT  61.632 4.741 62.328 5.077 ;
     RECT  98.976 4.883 102.216 5.077 ;
     RECT  17.856 4.501 20.04 5.171 ;
     RECT  95.616 4.883 97.8 5.171 ;
     RECT  106.512 4.643 106.536 5.171 ;
     RECT  110.4 5.029 116.424 5.171 ;
     RECT  118.272 4.979 123 5.171 ;
     RECT  67.2 4.595 69.528 5.219 ;
     RECT  72.24 4.837 75.672 5.219 ;
     RECT  81.264 4.883 92.952 5.219 ;
     RECT  113.712 5.171 116.424 5.219 ;
     RECT  81.264 5.219 82.056 5.267 ;
     RECT  83.088 5.219 92.952 5.267 ;
     RECT  81.264 5.267 82.008 5.363 ;
     RECT  125.376 4.261 127.656 5.459 ;
     RECT  125.712 5.459 127.656 5.507 ;
     RECT  0.192 4.933 0.216 13.043 ;
     RECT  72.24 5.219 72.912 21.541 ;
     RECT  74.16 5.219 75.192 21.541 ;
     RECT  16.416 3.925 16.44 21.637 ;
     RECT  67.2 5.219 67.512 21.637 ;
     RECT  72.24 21.541 75.192 21.637 ;
     RECT  83.136 5.267 92.952 21.637 ;
     RECT  93.936 4.883 94.512 21.637 ;
     RECT  98.976 5.077 102.552 21.637 ;
     RECT  115.296 5.219 116.424 21.637 ;
     RECT  67.2 21.637 67.608 21.781 ;
     RECT  61.632 5.077 62.664 22.021 ;
     RECT  108.528 4.595 109.416 22.117 ;
     RECT  110.4 5.171 112.296 22.117 ;
     RECT  34.8 3.155 35.112 22.741 ;
     RECT  63.792 4.883 66.12 22.835 ;
     RECT  81.264 5.363 81.96 22.835 ;
     RECT  83.136 21.637 94.512 22.835 ;
     RECT  115.296 21.637 117.384 22.835 ;
     RECT  124.032 3.733 124.056 22.835 ;
     RECT  16.416 21.637 16.68 23.365 ;
     RECT  34.8 22.741 35.496 23.365 ;
     RECT  45.6 1.763 45.912 23.365 ;
     RECT  67.2 21.781 67.656 23.365 ;
     RECT  68.736 5.219 69.528 23.365 ;
     RECT  77.808 4.979 78.648 23.365 ;
     RECT  125.712 5.507 127.08 23.365 ;
     RECT  128.784 4.501 128.808 23.365 ;
     RECT  61.584 22.021 62.664 23.411 ;
     RECT  67.2 23.365 69.528 23.411 ;
     RECT  70.704 4.883 71.064 23.411 ;
     RECT  83.136 22.835 87.144 23.411 ;
     RECT  88.56 22.835 94.512 23.411 ;
     RECT  95.616 5.171 97.656 23.411 ;
     RECT  104.064 4.019 105.432 23.411 ;
     RECT  108.528 22.117 112.296 23.411 ;
     RECT  113.712 5.219 114.312 23.411 ;
     RECT  118.368 5.171 123 23.411 ;
     RECT  125.712 23.365 129.288 23.411 ;
     RECT  17.856 5.171 19.32 23.459 ;
     RECT  118.368 23.411 121.944 23.459 ;
     RECT  67.2 23.411 68.232 23.461 ;
     RECT  98.928 21.637 103.08 23.701 ;
     RECT  114.096 23.411 114.312 23.701 ;
     RECT  2.4 2.151 2.712 23.769 ;
     RECT  7.8 2.151 8.112 23.769 ;
     RECT  13.2 1.763 13.512 23.769 ;
     RECT  40.2 1.763 40.512 23.769 ;
     RECT  61.584 23.411 62.112 23.769 ;
     RECT  137.4 4.595 137.712 23.769 ;
     RECT  2.4 23.769 2.52 23.783 ;
     RECT  7.8 23.769 7.92 23.783 ;
     RECT  13.2 23.769 13.32 23.783 ;
     RECT  29.4 2.151 29.712 23.783 ;
     RECT  40.2 23.769 40.392 23.783 ;
     RECT  61.584 23.769 61.92 23.783 ;
     RECT  115.8 22.835 117.384 23.783 ;
     RECT  132 4.883 132.312 23.783 ;
     RECT  137.4 23.769 137.52 23.783 ;
     RECT  83.136 23.411 87.048 23.845 ;
     RECT  105 23.411 105.432 23.845 ;
     RECT  126.6 23.411 129.288 23.845 ;
     RECT  130.512 21.637 130.536 23.845 ;
     RECT  15.024 23.365 16.68 23.893 ;
     RECT  18.6 23.459 19.32 23.893 ;
     RECT  24 2.137 24.312 23.893 ;
     RECT  25.68 22.741 25.704 23.893 ;
     RECT  38.736 23.365 38.76 23.893 ;
     RECT  45.6 23.365 46.152 23.893 ;
     RECT  51 4.019 51.312 23.893 ;
     RECT  56.4 1.763 56.712 23.893 ;
     RECT  61.584 23.783 61.704 23.893 ;
     RECT  64.56 22.835 65.832 23.893 ;
     RECT  66.96 23.461 68.232 23.893 ;
     RECT  72.24 21.637 75.24 23.893 ;
     RECT  77.232 23.365 78.648 23.893 ;
     RECT  80.112 22.213 80.136 23.893 ;
     RECT  81.264 22.835 81.768 23.893 ;
     RECT  88.656 23.411 94.512 23.893 ;
     RECT  95.616 23.411 97.32 23.893 ;
     RECT  105 23.845 105.48 23.893 ;
     RECT  108.72 23.411 112.296 23.893 ;
     RECT  114.096 23.701 114.504 23.893 ;
     RECT  126.6 23.845 130.536 23.893 ;
     RECT  141.936 21.637 141.96 23.893 ;
     RECT  72.24 23.893 81.768 23.941 ;
     RECT  24 23.893 25.704 24.469 ;
     RECT  43.632 23.893 46.152 24.469 ;
     RECT  47.76 23.365 47.784 24.469 ;
     RECT  51 23.893 51.912 24.469 ;
     RECT  53.52 23.893 53.544 24.469 ;
     RECT  55.152 23.893 57.576 24.469 ;
     RECT  64.56 23.893 68.232 24.469 ;
     RECT  69.456 23.411 69.48 24.469 ;
     RECT  71.952 23.941 81.768 24.469 ;
     RECT  82.992 23.845 87.048 24.469 ;
     RECT  88.656 23.893 97.32 24.469 ;
     RECT  98.544 23.701 103.464 24.469 ;
     RECT  105 23.893 107.112 24.469 ;
     RECT  108.72 23.893 112.488 24.469 ;
     RECT  114.096 23.893 114.888 24.469 ;
     RECT  116.112 23.783 117.384 24.469 ;
     RECT  118.608 23.459 121.944 24.469 ;
     RECT  123.504 23.893 125.544 24.469 ;
     RECT  126.6 23.893 131.496 24.469 ;
     RECT  14.64 23.893 17.544 24.517 ;
     RECT  18.6 23.893 21.576 24.517 ;
     RECT  61.296 23.893 61.704 24.517 ;
     RECT  135.216 23.893 135.24 24.517 ;
     RECT  136.656 23.893 136.68 24.517 ;
     RECT  140.4 23.893 141.96 24.517 ;
     RECT  71.088 24.469 87.528 24.997 ;
     RECT  88.656 24.469 107.112 24.997 ;
     RECT  59.184 23.893 59.208 25.045 ;
     RECT  60.432 24.517 61.704 25.045 ;
     RECT  62.928 24.469 63.336 25.045 ;
     RECT  64.56 24.469 69.864 25.045 ;
     RECT  71.088 24.997 107.112 25.045 ;
     RECT  108.72 24.469 114.888 25.045 ;
     RECT  116.112 24.469 131.496 25.045 ;
     RECT  133.008 23.893 133.032 25.045 ;
     RECT  135.216 24.517 136.68 25.045 ;
     RECT  13.008 25.045 13.032 25.093 ;
     RECT  14.64 24.517 21.576 25.093 ;
     RECT  29.712 24.469 29.736 25.093 ;
     RECT  32.976 23.893 33 25.093 ;
     RECT  34.608 23.365 35.496 25.093 ;
     RECT  53.52 24.469 57.576 25.093 ;
     RECT  59.184 25.045 61.704 25.093 ;
     RECT  138.96 23.893 138.984 25.093 ;
     RECT  140.4 24.517 142.728 25.093 ;
     RECT  53.52 25.093 61.704 25.717 ;
     RECT  62.928 25.045 107.592 25.717 ;
     RECT  108.72 25.045 133.032 25.717 ;
     RECT  13.008 25.093 21.576 25.765 ;
     RECT  23.184 24.469 25.704 25.765 ;
     RECT  27.312 23.893 27.336 25.765 ;
     RECT  29.712 25.093 31.368 25.765 ;
     RECT  32.976 25.093 35.496 25.765 ;
     RECT  37.104 23.893 38.76 25.765 ;
     RECT  40.368 23.783 40.392 25.765 ;
     RECT  42 23.893 42.024 25.765 ;
     RECT  43.632 24.469 51.912 25.765 ;
     RECT  53.52 25.717 133.032 25.765 ;
     RECT  134.448 25.045 137.448 25.765 ;
     RECT  138.96 25.093 142.728 25.765 ;
     RECT  13.008 25.765 142.728 25.836 ;
     RECT  13.032 25.836 13.392 25.872 ;
     RECT  13.416 25.836 13.872 25.872 ;
     RECT  13.896 25.836 14.256 25.872 ;
     RECT  14.28 25.836 14.64 25.872 ;
     RECT  14.664 25.836 15.024 25.872 ;
     RECT  15.048 25.836 15.504 25.872 ;
     RECT  15.528 25.836 15.888 25.872 ;
     RECT  15.912 25.836 16.272 25.872 ;
     RECT  16.296 25.836 16.656 25.872 ;
     RECT  16.68 25.836 17.136 25.872 ;
     RECT  17.16 25.836 17.52 25.872 ;
     RECT  17.544 25.836 17.904 25.872 ;
     RECT  17.928 25.836 18.384 25.872 ;
     RECT  18.408 25.836 18.768 25.872 ;
     RECT  18.792 25.836 19.152 25.872 ;
     RECT  19.176 25.836 19.536 25.872 ;
     RECT  19.56 25.836 20.016 25.872 ;
     RECT  20.04 25.836 20.688 25.872 ;
     RECT  20.712 25.836 21.552 25.872 ;
     RECT  21.576 25.836 22.416 25.872 ;
     RECT  22.44 25.836 23.184 25.872 ;
     RECT  23.208 25.836 24.048 25.872 ;
     RECT  24.072 25.836 24.816 25.872 ;
     RECT  24.84 25.836 25.68 25.872 ;
     RECT  25.704 25.836 26.448 25.872 ;
     RECT  26.472 25.836 27.312 25.872 ;
     RECT  27.336 25.836 28.08 25.872 ;
     RECT  28.104 25.836 28.944 25.872 ;
     RECT  28.968 25.836 29.712 25.872 ;
     RECT  29.736 25.836 30.576 25.872 ;
     RECT  30.6 25.836 31.344 25.872 ;
     RECT  31.368 25.836 32.208 25.872 ;
     RECT  32.232 25.836 32.976 25.872 ;
     RECT  33 25.836 33.84 25.872 ;
     RECT  33.864 25.836 34.608 25.872 ;
     RECT  34.632 25.836 35.472 25.872 ;
     RECT  35.496 25.836 36.336 25.872 ;
     RECT  36.36 25.836 37.104 25.872 ;
     RECT  37.128 25.836 37.968 25.872 ;
     RECT  37.992 25.836 38.736 25.872 ;
     RECT  38.76 25.836 39.6 25.872 ;
     RECT  39.624 25.836 40.368 25.872 ;
     RECT  40.392 25.836 41.232 25.872 ;
     RECT  41.256 25.836 42 25.872 ;
     RECT  42.024 25.836 42.864 25.872 ;
     RECT  42.888 25.836 43.632 25.872 ;
     RECT  43.656 25.836 44.496 25.872 ;
     RECT  44.52 25.836 45.264 25.872 ;
     RECT  45.288 25.836 46.128 25.872 ;
     RECT  46.152 25.836 46.896 25.872 ;
     RECT  46.92 25.836 47.76 25.872 ;
     RECT  47.784 25.836 48.528 25.872 ;
     RECT  48.552 25.836 49.392 25.872 ;
     RECT  49.416 25.836 50.256 25.872 ;
     RECT  50.28 25.836 51.024 25.872 ;
     RECT  51.048 25.836 51.888 25.872 ;
     RECT  51.912 25.836 52.656 25.872 ;
     RECT  52.68 25.836 53.52 25.872 ;
     RECT  53.544 25.836 54.288 25.872 ;
     RECT  54.312 25.836 55.152 25.872 ;
     RECT  55.176 25.836 55.92 25.872 ;
     RECT  55.944 25.836 56.784 25.872 ;
     RECT  56.808 25.836 57.552 25.872 ;
     RECT  57.576 25.836 58.416 25.872 ;
     RECT  58.44 25.836 59.184 25.872 ;
     RECT  59.208 25.836 60.048 25.872 ;
     RECT  60.072 25.836 60.432 25.872 ;
     RECT  60.456 25.836 60.816 25.872 ;
     RECT  60.84 25.836 61.296 25.872 ;
     RECT  61.32 25.836 61.68 25.872 ;
     RECT  61.704 25.836 62.064 25.872 ;
     RECT  62.088 25.836 62.448 25.872 ;
     RECT  62.472 25.836 62.928 25.872 ;
     RECT  62.952 25.836 63.312 25.872 ;
     RECT  63.336 25.836 63.696 25.872 ;
     RECT  63.72 25.836 64.176 25.872 ;
     RECT  64.2 25.836 64.56 25.872 ;
     RECT  64.584 25.836 64.944 25.872 ;
     RECT  64.968 25.836 65.328 25.872 ;
     RECT  65.352 25.836 65.808 25.872 ;
     RECT  65.832 25.836 66.192 25.872 ;
     RECT  66.216 25.836 66.576 25.872 ;
     RECT  66.6 25.836 66.96 25.872 ;
     RECT  66.984 25.836 67.44 25.872 ;
     RECT  67.464 25.836 67.824 25.872 ;
     RECT  67.848 25.836 68.208 25.872 ;
     RECT  68.232 25.836 68.592 25.872 ;
     RECT  68.616 25.836 69.072 25.872 ;
     RECT  69.096 25.836 69.456 25.872 ;
     RECT  69.48 25.836 69.84 25.872 ;
     RECT  69.864 25.836 70.32 25.872 ;
     RECT  70.344 25.836 70.704 25.872 ;
     RECT  70.728 25.836 71.088 25.872 ;
     RECT  71.112 25.836 71.472 25.872 ;
     RECT  71.496 25.836 71.952 25.872 ;
     RECT  71.976 25.836 72.336 25.872 ;
     RECT  72.36 25.836 72.72 25.872 ;
     RECT  72.744 25.836 73.104 25.872 ;
     RECT  73.128 25.836 73.584 25.872 ;
     RECT  73.608 25.836 73.968 25.872 ;
     RECT  73.992 25.836 74.352 25.872 ;
     RECT  74.376 25.836 74.736 25.872 ;
     RECT  74.76 25.836 75.216 25.872 ;
     RECT  75.24 25.836 75.6 25.872 ;
     RECT  75.624 25.836 75.984 25.872 ;
     RECT  76.008 25.836 76.464 25.872 ;
     RECT  76.488 25.836 76.848 25.872 ;
     RECT  76.872 25.836 77.232 25.872 ;
     RECT  77.256 25.836 77.616 25.872 ;
     RECT  77.64 25.836 78.096 25.872 ;
     RECT  78.12 25.836 78.48 25.872 ;
     RECT  78.504 25.836 78.864 25.872 ;
     RECT  78.888 25.836 79.248 25.872 ;
     RECT  79.272 25.836 79.728 25.872 ;
     RECT  79.752 25.836 80.112 25.872 ;
     RECT  80.136 25.836 80.496 25.872 ;
     RECT  80.52 25.836 80.88 25.872 ;
     RECT  80.904 25.836 81.36 25.872 ;
     RECT  81.384 25.836 81.744 25.872 ;
     RECT  81.768 25.836 82.128 25.872 ;
     RECT  82.152 25.836 82.512 25.872 ;
     RECT  82.536 25.836 82.992 25.872 ;
     RECT  83.016 25.836 83.376 25.872 ;
     RECT  83.4 25.836 83.76 25.872 ;
     RECT  83.784 25.836 84.24 25.872 ;
     RECT  84.264 25.836 84.624 25.872 ;
     RECT  84.648 25.836 85.008 25.872 ;
     RECT  85.032 25.836 85.392 25.872 ;
     RECT  85.416 25.836 85.872 25.872 ;
     RECT  85.896 25.836 86.256 25.872 ;
     RECT  86.28 25.836 86.64 25.872 ;
     RECT  86.664 25.836 87.024 25.872 ;
     RECT  87.048 25.836 87.504 25.872 ;
     RECT  87.528 25.836 87.888 25.872 ;
     RECT  87.912 25.836 88.272 25.872 ;
     RECT  88.296 25.836 88.656 25.872 ;
     RECT  88.68 25.836 89.136 25.872 ;
     RECT  89.16 25.836 89.52 25.872 ;
     RECT  89.544 25.836 89.904 25.872 ;
     RECT  89.928 25.836 90.384 25.872 ;
     RECT  90.408 25.836 90.768 25.872 ;
     RECT  90.792 25.836 91.152 25.872 ;
     RECT  91.176 25.836 91.536 25.872 ;
     RECT  91.56 25.836 92.016 25.872 ;
     RECT  92.04 25.836 92.4 25.872 ;
     RECT  92.424 25.836 92.784 25.872 ;
     RECT  92.808 25.836 93.168 25.872 ;
     RECT  93.192 25.836 93.648 25.872 ;
     RECT  93.672 25.836 94.032 25.872 ;
     RECT  94.056 25.836 94.416 25.872 ;
     RECT  94.44 25.836 94.8 25.872 ;
     RECT  94.824 25.836 95.28 25.872 ;
     RECT  95.304 25.836 95.664 25.872 ;
     RECT  95.688 25.836 96.048 25.872 ;
     RECT  96.072 25.836 96.528 25.872 ;
     RECT  96.552 25.836 96.912 25.872 ;
     RECT  96.936 25.836 97.296 25.872 ;
     RECT  97.32 25.836 97.68 25.872 ;
     RECT  97.704 25.836 98.16 25.872 ;
     RECT  98.184 25.836 98.544 25.872 ;
     RECT  98.568 25.836 98.928 25.872 ;
     RECT  98.952 25.836 99.312 25.872 ;
     RECT  99.336 25.836 99.792 25.872 ;
     RECT  99.816 25.836 100.176 25.872 ;
     RECT  100.2 25.836 100.56 25.872 ;
     RECT  100.584 25.836 100.944 25.872 ;
     RECT  100.968 25.836 101.424 25.872 ;
     RECT  101.448 25.836 101.808 25.872 ;
     RECT  101.832 25.836 102.192 25.872 ;
     RECT  102.216 25.836 102.576 25.872 ;
     RECT  102.6 25.836 103.056 25.872 ;
     RECT  103.08 25.836 103.44 25.872 ;
     RECT  103.464 25.836 103.824 25.872 ;
     RECT  103.848 25.836 104.304 25.872 ;
     RECT  104.328 25.836 104.688 25.872 ;
     RECT  104.712 25.836 105.072 25.872 ;
     RECT  105.096 25.836 105.456 25.872 ;
     RECT  105.48 25.836 105.936 25.872 ;
     RECT  105.96 25.836 106.32 25.872 ;
     RECT  106.344 25.836 106.704 25.872 ;
     RECT  106.728 25.836 107.088 25.872 ;
     RECT  107.112 25.836 107.568 25.872 ;
     RECT  107.592 25.836 107.952 25.872 ;
     RECT  107.976 25.836 108.336 25.872 ;
     RECT  108.36 25.836 108.72 25.872 ;
     RECT  108.744 25.836 109.2 25.872 ;
     RECT  109.224 25.836 109.584 25.872 ;
     RECT  109.608 25.836 109.968 25.872 ;
     RECT  109.992 25.836 110.448 25.872 ;
     RECT  110.472 25.836 110.832 25.872 ;
     RECT  110.856 25.836 111.216 25.872 ;
     RECT  111.24 25.836 111.6 25.872 ;
     RECT  111.624 25.836 112.08 25.872 ;
     RECT  112.104 25.836 112.464 25.872 ;
     RECT  112.488 25.836 112.848 25.872 ;
     RECT  112.872 25.836 113.232 25.872 ;
     RECT  113.256 25.836 113.712 25.872 ;
     RECT  113.736 25.836 114.096 25.872 ;
     RECT  114.12 25.836 114.48 25.872 ;
     RECT  114.504 25.836 114.864 25.872 ;
     RECT  114.888 25.836 115.344 25.872 ;
     RECT  115.368 25.836 115.728 25.872 ;
     RECT  115.752 25.836 116.112 25.872 ;
     RECT  116.136 25.836 116.592 25.872 ;
     RECT  116.616 25.836 116.976 25.872 ;
     RECT  117 25.836 117.36 25.872 ;
     RECT  117.384 25.836 117.744 25.872 ;
     RECT  117.768 25.836 118.224 25.872 ;
     RECT  118.248 25.836 118.608 25.872 ;
     RECT  118.632 25.836 118.992 25.872 ;
     RECT  119.016 25.836 119.376 25.872 ;
     RECT  119.4 25.836 119.856 25.872 ;
     RECT  119.88 25.836 120.24 25.872 ;
     RECT  120.264 25.836 120.624 25.872 ;
     RECT  120.648 25.836 121.008 25.872 ;
     RECT  121.032 25.836 121.488 25.872 ;
     RECT  121.512 25.836 121.872 25.872 ;
     RECT  121.896 25.836 122.256 25.872 ;
     RECT  122.28 25.836 122.64 25.872 ;
     RECT  122.664 25.836 123.12 25.872 ;
     RECT  123.144 25.836 123.504 25.872 ;
     RECT  123.528 25.836 123.888 25.872 ;
     RECT  123.912 25.836 124.368 25.872 ;
     RECT  124.392 25.836 124.752 25.872 ;
     RECT  124.776 25.836 125.136 25.872 ;
     RECT  125.16 25.836 125.52 25.872 ;
     RECT  125.544 25.836 126 25.872 ;
     RECT  126.024 25.836 126.384 25.872 ;
     RECT  126.408 25.836 126.768 25.872 ;
     RECT  126.792 25.836 127.152 25.872 ;
     RECT  127.176 25.836 127.632 25.872 ;
     RECT  127.656 25.836 128.016 25.872 ;
     RECT  128.04 25.836 128.4 25.872 ;
     RECT  128.424 25.836 128.784 25.872 ;
     RECT  128.808 25.836 129.264 25.872 ;
     RECT  129.288 25.836 129.648 25.872 ;
     RECT  129.672 25.836 130.032 25.872 ;
     RECT  130.056 25.836 130.512 25.872 ;
     RECT  130.536 25.836 130.896 25.872 ;
     RECT  130.92 25.836 131.472 25.872 ;
     RECT  131.496 25.836 132.24 25.872 ;
     RECT  132.264 25.836 133.008 25.872 ;
     RECT  133.032 25.836 133.68 25.872 ;
     RECT  133.704 25.836 134.448 25.872 ;
     RECT  134.472 25.836 135.216 25.872 ;
     RECT  135.24 25.836 135.984 25.872 ;
     RECT  136.008 25.836 136.656 25.872 ;
     RECT  136.68 25.836 137.424 25.872 ;
     RECT  137.448 25.836 138.192 25.872 ;
     RECT  138.216 25.836 138.96 25.872 ;
     RECT  138.984 25.836 139.632 25.872 ;
     RECT  139.656 25.836 140.4 25.872 ;
     RECT  140.424 25.836 141.168 25.872 ;
     RECT  141.192 25.836 141.936 25.872 ;
     RECT  141.96 25.836 142.704 25.872 ;
     RECT  23.208 0.611 24.816 1.763 ;
     RECT  13.512 1.763 14.64 1.811 ;
     RECT  20.784 1.763 20.808 3.061 ;
     RECT  24 1.763 24.312 2.137 ;
     RECT  26.784 1.763 27.384 2.821 ;
     RECT  35.112 1.763 36.984 2.821 ;
     RECT  50.4 1.763 51 2.821 ;
     RECT  66.216 1.763 67.2 3.875 ;
     RECT  67.512 1.763 68.784 3.925 ;
     RECT  84.264 1.763 85.392 2.291 ;
     RECT  86.664 1.763 87.744 2.291 ;
     RECT  91.176 1.763 92.544 3.301 ;
     RECT  92.952 1.763 94.2 3.301 ;
     RECT  98.184 1.763 99.6 2.291 ;
     RECT  100.728 1.763 102.576 2.821 ;
     RECT  105.672 1.763 107.136 2.339 ;
     RECT  108.84 1.763 109.968 2.291 ;
     RECT  110.712 1.763 112.08 3.301 ;
     RECT  126.912 1.763 128.4 2.867 ;
     RECT  130.536 1.763 132 2.291 ;
     RECT  82.512 1.811 82.56 2.821 ;
     RECT  94.92 1.811 95.904 3.205 ;
     RECT  68.808 1.859 70.32 3.541 ;
     RECT  116.112 2.003 116.136 3.301 ;
     RECT  72.336 2.291 72.432 3.301 ;
     RECT  84.264 2.291 86.016 3.205 ;
     RECT  86.04 2.291 87.744 3.397 ;
     RECT  98.088 2.291 99.6 2.773 ;
     RECT  108.84 2.291 110.4 3.301 ;
     RECT  121.512 2.291 121.896 3.349 ;
     RECT  125.712 2.291 126.6 3.397 ;
     RECT  105.48 2.339 107.136 3.301 ;
     RECT  98.088 2.773 99.408 2.821 ;
     RECT  26.784 2.821 27.36 3.061 ;
     RECT  35.64 2.821 36.984 3.109 ;
     RECT  51.312 2.821 52.416 4.019 ;
     RECT  98.088 2.821 99.312 3.253 ;
     RECT  101.208 2.821 102.576 3.109 ;
     RECT  126.912 2.867 127.656 3.301 ;
     RECT  35.64 3.109 36.96 3.155 ;
     RECT  84.36 3.205 86.016 3.397 ;
     RECT  71.064 3.301 72.432 3.829 ;
     RECT  92.952 3.301 94.08 3.349 ;
     RECT  105.48 3.301 106.512 4.019 ;
     RECT  108.984 3.301 110.4 3.733 ;
     RECT  110.808 3.301 112.08 3.443 ;
     RECT  112.296 3.301 113.376 3.443 ;
     RECT  127.368 3.301 127.656 4.261 ;
     RECT  72.912 3.349 74.064 4.837 ;
     RECT  116.232 3.349 117.696 3.733 ;
     RECT  84.936 3.397 86.016 3.733 ;
     RECT  86.04 3.397 87.552 3.733 ;
     RECT  113.736 3.397 115.248 3.733 ;
     RECT  74.088 3.443 75.168 4.501 ;
     RECT  110.808 3.443 112.176 3.491 ;
     RECT  112.2 3.443 113.376 3.491 ;
     RECT  110.808 3.491 113.376 3.877 ;
     RECT  102.216 3.539 103.632 4.019 ;
     RECT  86.424 3.733 87.552 4.837 ;
     RECT  109.32 3.733 110.4 3.781 ;
     RECT  116.424 3.733 117.696 4.979 ;
     RECT  122.808 3.733 124.032 3.877 ;
     RECT  71.112 3.829 72.432 3.925 ;
     RECT  130.2 3.829 131.328 4.883 ;
     RECT  66.12 3.875 67.2 22.835 ;
     RECT  18.912 3.877 20.016 4.501 ;
     RECT  62.112 3.877 63.504 4.741 ;
     RECT  63.528 3.877 64.656 4.501 ;
     RECT  110.952 3.877 113.376 4.501 ;
     RECT  118.488 3.877 119.472 3.925 ;
     RECT  123 3.877 124.032 22.835 ;
     RECT  16.44 3.925 17.856 21.637 ;
     RECT  71.112 3.925 72.24 4.883 ;
     RECT  13.512 3.973 14.832 4.115 ;
     RECT  75.672 3.973 76.944 4.979 ;
     RECT  102.216 4.019 104.064 5.077 ;
     RECT  105.432 4.019 106.512 5.171 ;
     RECT  107.4 4.067 108.528 4.643 ;
     RECT  124.056 4.117 125.376 5.459 ;
     RECT  119.976 4.165 121.2 4.453 ;
     RECT  119.976 4.453 121.104 4.501 ;
     RECT  110.952 4.501 112.272 4.837 ;
     RECT  112.296 4.501 113.376 5.029 ;
     RECT  127.656 4.501 128.784 5.507 ;
     RECT  128.808 4.501 130.176 5.027 ;
     RECT  69.528 4.595 70.512 4.739 ;
     RECT  109.416 4.595 110.4 22.117 ;
     RECT  69.528 4.739 70.704 23.411 ;
     RECT  62.328 4.741 63.504 4.883 ;
     RECT  110.952 4.837 112.128 4.885 ;
     RECT  62.328 4.883 63.792 5.077 ;
     RECT  71.064 4.883 72.24 23.411 ;
     RECT  92.952 4.883 93.936 21.637 ;
     RECT  94.512 4.883 95.616 23.893 ;
     RECT  97.8 4.883 98.976 5.171 ;
     RECT  62.664 5.077 63.792 22.835 ;
     RECT  102.552 5.077 104.064 21.637 ;
     RECT  97.656 5.171 98.976 21.637 ;
     RECT  112.296 5.171 113.712 23.411 ;
     RECT  67.512 5.219 68.736 21.637 ;
     RECT  72.912 5.219 74.16 21.541 ;
     RECT  82.056 5.219 83.088 5.267 ;
     RECT  114.312 5.219 115.296 22.835 ;
     RECT  82.008 5.267 83.136 5.363 ;
     RECT  81.96 5.363 83.136 22.835 ;
     RECT  16.68 21.637 17.856 23.459 ;
     RECT  67.608 21.637 68.736 21.781 ;
     RECT  97.656 21.637 98.928 23.411 ;
     RECT  103.08 21.637 104.064 23.411 ;
     RECT  117.384 21.637 118.368 23.459 ;
     RECT  130.536 21.637 132 23.783 ;
     RECT  67.656 21.781 68.736 23.365 ;
     RECT  78.648 22.213 80.112 23.893 ;
     RECT  80.136 22.213 81.264 23.893 ;
     RECT  24.312 22.741 25.68 23.893 ;
     RECT  65.832 22.835 67.2 23.461 ;
     RECT  81.768 22.835 83.136 23.845 ;
     RECT  87.144 22.835 88.56 23.411 ;
     RECT  114.312 22.835 115.8 23.701 ;
     RECT  123 22.835 124.056 23.411 ;
     RECT  13.512 23.365 15.024 23.769 ;
     RECT  38.76 23.365 40.2 23.783 ;
     RECT  129.288 23.365 130.512 23.845 ;
     RECT  62.112 23.411 62.664 23.769 ;
     RECT  68.232 23.411 69.456 24.469 ;
     RECT  69.48 23.411 72.24 23.941 ;
     RECT  87.048 23.411 88.656 24.469 ;
     RECT  97.32 23.411 98.928 23.701 ;
     RECT  103.08 23.411 105 23.701 ;
     RECT  112.296 23.411 114.096 23.893 ;
     RECT  121.944 23.411 124.056 23.893 ;
     RECT  125.712 23.411 126.6 23.893 ;
     RECT  16.68 23.459 18.6 23.893 ;
     RECT  117.384 23.459 118.608 24.469 ;
     RECT  65.832 23.461 66.96 23.893 ;
     RECT  97.32 23.701 98.544 24.469 ;
     RECT  103.464 23.701 105 24.469 ;
     RECT  114.504 23.701 115.8 23.783 ;
     RECT  13.32 23.769 15.024 23.783 ;
     RECT  61.92 23.769 62.664 23.783 ;
     RECT  137.52 23.769 137.712 23.783 ;
     RECT  13.2 23.783 15.024 23.893 ;
     RECT  61.704 23.783 62.664 24.469 ;
     RECT  114.504 23.783 116.112 23.893 ;
     RECT  130.536 23.783 132.312 23.893 ;
     RECT  137.4 23.783 137.712 23.893 ;
     RECT  81.768 23.845 82.992 24.469 ;
     RECT  13.2 23.893 14.64 25.045 ;
     RECT  17.544 23.893 18.6 24.517 ;
     RECT  112.488 23.893 114.096 24.469 ;
     RECT  114.888 23.893 116.112 25.045 ;
     RECT  121.944 23.893 123.504 24.469 ;
     RECT  125.544 23.893 126.6 24.469 ;
     RECT  131.496 23.893 133.008 25.045 ;
     RECT  135.24 23.893 136.656 24.517 ;
     RECT  136.68 23.893 138.96 25.045 ;
     RECT  138.984 23.893 140.4 25.093 ;
     RECT  69.48 23.941 71.952 24.469 ;
     RECT  61.704 24.469 62.928 25.717 ;
     RECT  63.336 24.469 64.56 25.045 ;
     RECT  69.864 24.469 71.088 25.045 ;
     RECT  87.528 24.469 88.656 24.997 ;
     RECT  59.208 24.517 60.432 25.045 ;
     RECT  13.032 25.045 14.64 25.093 ;
     RECT  107.592 25.045 108.72 25.717 ;
     RECT  133.032 25.045 134.448 25.765 ;
     RECT  137.448 25.045 138.96 25.765 ;
  END
END ot_s81_hc_ctrn_par_e
END LIBRARY
